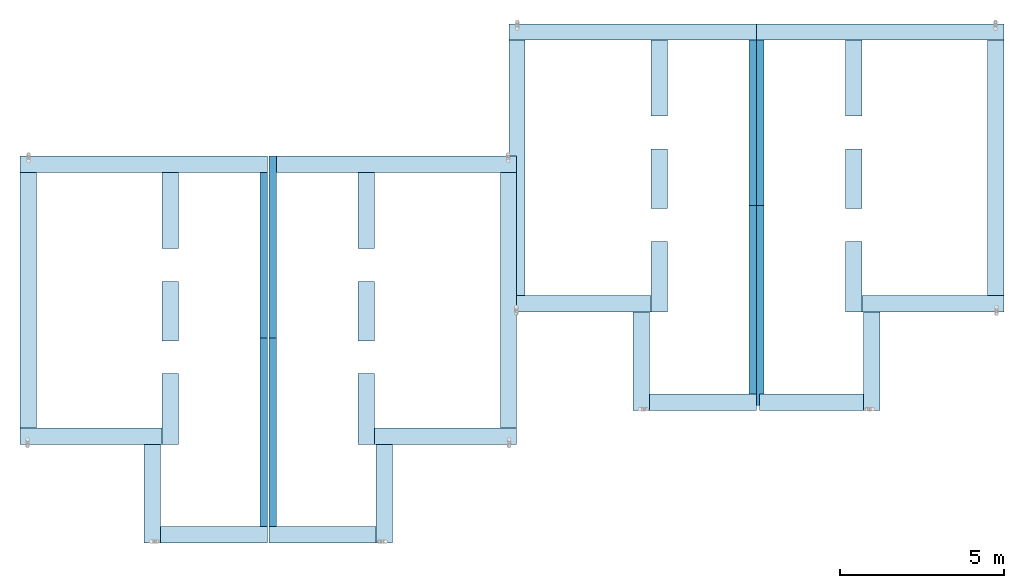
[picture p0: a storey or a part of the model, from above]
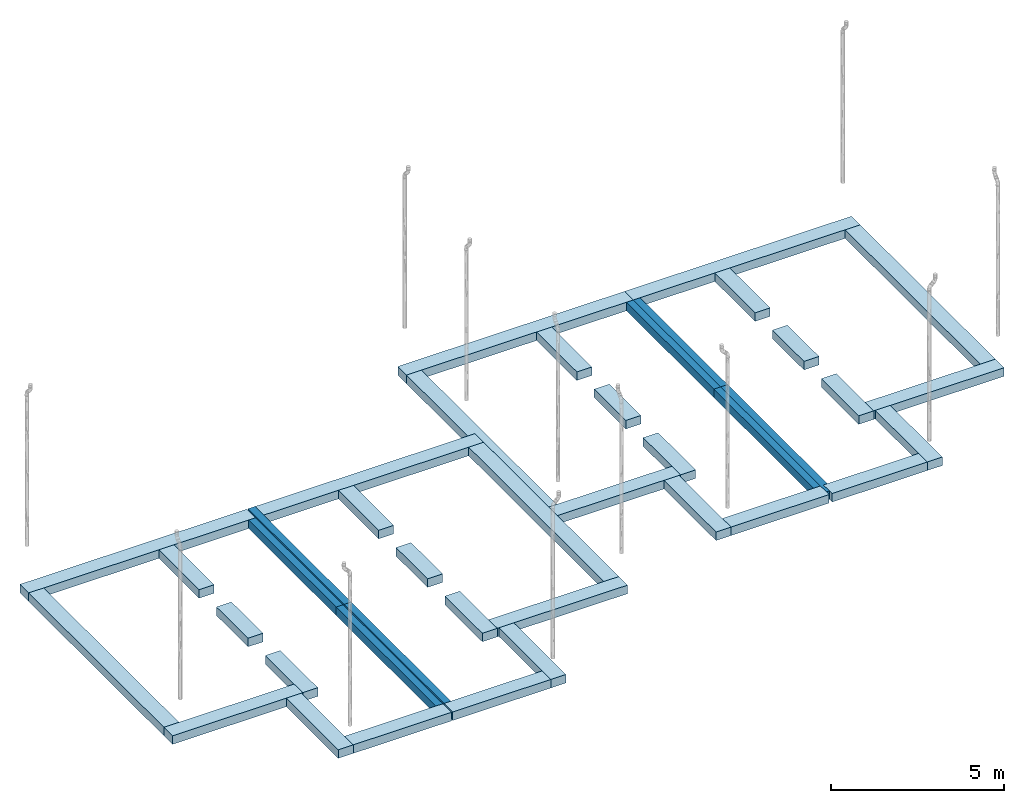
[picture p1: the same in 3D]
Properties of the parts of a building model (IFC2X3), part 1 of 3

# File
Description: ViewDefinition [CoordinationView]
Time: 2020-01-27T23:21:47
Written by: The EXPRESS Data Manager Version 5.02.0100.07 : 28 Aug 2013
Made in: 20150220_1215(x64) - Exporter 16.0.428.0 - Default UI
Comment: STEP Physical File produced by: The EXPRESS Data Manager Version 5.02.0100.07 : 28 Aug 2013 * Module: EDMstepFileFactory/EDMstandAlone * Creation date: Mon Jan 27 23:21:47 2020 * Host: Khodri-Mohamed * Database: C:\Users\KHODRI~1\AppData\Local\Temp\{C74B5687-D98A-45EB-B727-983E96799452}\ifc * Database version: 5507 * Database creation date: Mon Jan 27 23:21:04 2020 * Schema: IFC2X3 * Model: DataRepository.ifc * Model creation date: Mon Jan 27 23:21:07 2020 * Header model: DataRepository.ifc_HeaderModel * Header model creation date: Mon Jan 27 23:21:07 2020 * EDMuser: sdai-user * EDMgroup: sdai-group * License ID and type: 5605 : Permanent license. Expiry date: * EDMstepFileFactory options: 020000

# IfcProject
LongName: F:\sujet 0 CAP PEINTRE 2019\DOSSIER TECHNIQUE LUCE\PROJET DE 4 MAISONS A ROINVILLE DU 26 NOVEMBRE 2019.ifc

# IfcSite, Surface:1258945
RefLatitude: 48, 52, 53, 759999; RefLongitude: 2, 25, 58, 79999; RefElevation: 0 m
Autre - Catégorie: Topographie; Déblais: 0 m3; Déblais/remblais net: 0 m3; Remblais: 0 m3
Cotes - Surface: 126.205 m2; Surface projetée: 126.205 m2
Phase de construction - Phase de création: Nouvelle construction

# IfcBuilding
Pset_BuildingCommon - NumberOfStoreys: 8
Autre - Catégorie: Informations sur le projet

# IfcBuildingStorey (6)
Autre - Catégorie: Niveaux; Famille: Niveau: Ligne du Niveau; Famille et type: Niveau: Ligne du Niveau; ID du type: Niveau: Ligne du Niveau; Type: Niveau: Ligne du Niveau; Nom de la famille: Niveau
Cotes - Hauteur de calcul: 0 m
Données d'identification - Structure: no; Etage de bâtiment: yes; Nom du type: Ligne du Niveau
Contraintes - Base de l'élévation: Point de base du projet
Graphismes - Couleur: 12632256; Epaisseur des lignes: 1; Motif des lignes: Tiret point; Symbole: FR_Marqueur de niveau - Point triangulaire: FR_Marqueur de niveau - Point triangulaire; Valeur par défaut du symbole à l'extrémité 1: no; Valeur par défaut du symbole à l'extrémité 2: yes
Name | LongName = Nom | Elevation (m) = Elévation (m)
Plan de fondation | Plan de fondation | -1
vs | vs | -0.8
TN | TN | -0.05
Plan des fondations Maisons 1 et 2 | Plan des fondations Maisons 1 et 2 | 0
ETAGE | ETAGE | 2.82
Egout | Egout | 5.64

# IfcSpace (12)
InteriorOrExteriorSpace: INTERNAL
Analyse d'énergie - Charge d'éclairage basse sur: <Par défaut>; Charge d'éclairage réelle par surface: 0; Charge d'éclairage spécifiée: 0 W; Charge d'éclairage spécifiée par surface: 10.7639; Charge de puissance basse sur: <Par défaut>; Charge de puissance réelle: 0 W; Charge de puissance réelle par surface: 0; Charge de puissance spécifiée: 0 W; Charge de puissance spécifiée par surface: 13.9931; Charge réelle d'éclairage: 0 W; Contribution à l'éclairage du plénum: 0.2; Gain de chaleur latente par personne: 630.918; Gain de chaleur perceptible par personne: 788.648; Gain de chaleur total par personne: 1419.57; Nombre de personnes: 0; Surface par personne: 28.5714 m2; Unités de charge d'éclairage: Densité de puissance; Unités de charge de puissance: Densité de puissance; Valeurs de charge de chauffage: <Par défaut>
Autre - Catégorie: Pièces; ID de phase: Nouvelle construction
Contraintes - Décalage inférieur: 0 m; Décalage limite: 2.4384 m
Cotes - Hauteur de calcul: 0 m; Hauteur non liée: 2.4384 m
Phase de construction - Phase: Nouvelle construction
Name | In | LongName = Nom | GSA Space Areas (m2) = Surface (m2) | Reference | Limite supérieure | Niveau | Périmètre (m) | Numéro
470 | Plan des fondations Maisons 1 et 2 | SALON - CUISINE | 38.933 | SALON - CUISINE 470 | Niveau: RDC | Niveau: RDC | 31.5901 | 470
471 | Plan des fondations Maisons 1 et 2 | WC | 4.07214 | WC 471 | Niveau: RDC | RDC | 8.47736 | 471
472 | Plan des fondations Maisons 1 et 2 | GARAGE | 15.6284 | GARAGE 472 | Niveau: RDC | RDC | 17.23 | 472
473 | ETAGE | Ch 2 | 12.0823 | Ch 2 473 | Niveau: ETAGE | Niveau: ETAGE | 13.9765 | 473
474 | ETAGE | Ch 1 | 11.1072 | Ch 1 474 | Niveau: ETAGE | ETAGE | 13.3323 | 474
475 | ETAGE | SDB | 9.78736 | SDB 475 | Niveau: ETAGE | Niveau: ETAGE | 14.2316 | 475
476 | ETAGE | WC | 1.59787 | WC 476 | Niveau: ETAGE | Niveau: ETAGE | 5.22997 | 476
477 | ETAGE | Suite parentale | 13.4744 | Suite parentale 477 | Niveau: ETAGE | ETAGE | 18.1208 | 477
478 | ETAGE | Dégt | 3.93396 | Dégt 478 | Niveau: ETAGE | Niveau: ETAGE | 9.4721 | 478
479 | ETAGE | PL | 0.843565 | PL 479 | Niveau: ETAGE | Niveau: ETAGE | 4.24326 | 479
480 | ETAGE | PL | 0.782615 | PL 480 | Niveau: ETAGE | Niveau: ETAGE | 4.01326 | 480
482 | Plan des fondations Maisons 1 et 2 | PL | 0.732961 | PL 482 | Niveau: RDC | Niveau: RDC | 3.45584 | 482

# IfcAnnotation (62)
Name | In
11 x  | Plan des fondations Maisons 1 et 2
8 x  | ETAGE
 | Plan des fondations Maisons 1 et 2 | Group: Groupe de modèles:Pavillon type:1258082
 | Plan des fondations Maisons 1 et 2 | Group: Groupe de modèles:Pavillon type:1258309
39 x  | vs
 | ETAGE | Group: Groupe de modèles:Pavillon type:1258082
 | ETAGE | Group: Groupe de modèles:Pavillon type:1258309

# IfcBeam: Poutre rectangulaire - Béton:20 x 35 ht:892716 (4)
In: Egout
Material: Béton - Béton coulé sur place
Pset_BeamCommon - IsExternal: no; LoadBearing: yes; Slope: 0 deg; Reference: 20 x 35 ht; Span: 3.39 m
Autre - Catégorie: Ossature; Famille: Poutre rectangulaire - Béton: 20 x 35 ht; Famille et type: Poutre rectangulaire - Béton: 20 x 35 ht; ID du type: Poutre rectangulaire - Béton: 20 x 35 ht; Type: Poutre rectangulaire - Béton: 20 x 35 ht; Nom de la famille: Poutre rectangulaire - Béton
Contraintes - Décalage du niveau d'arrivée: 0.07 m; Décalage du niveau de départ: 0.07 m; Elévation du niveau de référence: 5.64 m; Niveau de référence: Niveau: Egout; Rotation de la section: 0 deg
Cotes - Elévation à la base: 5.36 m; Elévation en haut: 5.71 m; Longueur: 3.39 m; Surface: 1.94847 m2; Volume: 0.239078 m3; b: 0.2 m; h: 0.35 m
Matériaux et finitions - Matériau structurel: Béton - Béton coulé sur place
Phase de construction - Phase de création: Nouvelle construction
Position géométrique - Etat de la jonction: Deux jonctions activées; Justification Y: Origine; Justification YZ: Uniforme; Justification Z: Haut; Valeur de décalage Y: 0 m; Valeur de décalage Z: 0 m
Structure - Activer le modèle analytique: yes; Enrobage d'armature - Autres faces: Paramètres de l'enrobage d'armature: Enrobage d'armature 1; Enrobage d'armature - Face inférieure: Paramètres de l'enrobage d'armature: Enrobage d'armature 1; Enrobage d'armature - Face supérieure: Paramètres de l'enrobage d'armature: Enrobage d'armature 1; Longueur de coupe: 3.4154 m; Utilisation structurelle: Autre; Forme de coupe: 0
Données d'identification - Nom du type: 20 x 35 ht
Name (Poutre rectangulaire - Béton:20 x 35 ht:...) | Group
1344637
1344690 | Groupe de modèles:Pavillon type:1258082
1344694 | Groupe de modèles:Pavillon type:1258309
1360945 | Groupe de modèles:Pavillon type:1360776

# IfcBuildingElementProxy: 1372 mm (4)
Type - Material: Métal - Chrome, Métal - Acier, Poli, Métal - Finition peinture - Ivoire, Mat, Peinture - Ivoire, Plastique - Noir, Bois - Mélaminé blanc, Bois - Mélaminé hêtre
Type - Autre - Catégorie: Equipement spécialisé; Nom de la famille: Kitchenette - Moyenne
Type - Cotes - Hauteur: 0.9 m; Hauteur de l'empattement: 0.16 m; Hauteur du lave-vaisselle: 0.9 m; Hauteur du réfrigérateur: 2 m; Largeur: 1.372 m; Largeur de la plaque de cuisson: 0.55 m; Largeur de l'évier: 0.45 m; Largeur du lave-vaisselle: 0.71 m; Largeur du réfrigérateur: 0.66 m; Profondeur: 0.61 m; Profondeur de la plaque de cuisson: 0.45 m; Profondeur de l'empattement: 0.035 m; Profondeur de l'évier: 0.45 m; Profondeur du lave-vaisselle: 0.61 m; Profondeur du réfrigérateur: 0.76 m
Type - Données d'identification - Nom du type: 1372 mm
Type - Matériaux et finitions - Placard: Bois - Mélaminé blanc; Poignée: Plastique - Noir; Porte/tiroir: Bois - Mélaminé blanc
Pset_BuildingElementProxyCommon - Reference: 1372 mm
Autre - Famille: Kitchenette - Moyenne: 1372 mm; Famille et type: Kitchenette - Moyenne: 1372 mm; ID du type: Kitchenette - Moyenne: 1372 mm; Type: Kitchenette - Moyenne: 1372 mm
Contraintes - Niveau: Niveau: Plan des fondations Maisons 1 et 2; Décalage: 0 m; Se déplace avec les éléments voisins: no; Hôte: Niveau : Plan des fondations Maisons 1 et 2
Cotes - Surface: 16.7862 m2; Volume: 1.07185 m3
Phase de construction - Phase de création: Nouvelle construction
Name (Kitchenette - Moyenne:1372 mm:...) | In | Group
1278551 | Plan des fondations Maisons 1 et 2 | Groupe de modèles:Pavillon type:1258082
1278757 | Plan des fondations Maisons 1 et 2 | Groupe de modèles:Pavillon type:1258309
1283199 | 470
1360808 | Plan des fondations Maisons 1 et 2 | Groupe de modèles:Pavillon type:1360776

# IfcBuildingElementProxy: 1455639399409- Car (2)
In: Plan des fondations Maisons 1 et 2
Pset_BuildingElementProxyCommon - Reference: 1455639399409- Car
Autre - Catégorie: Site; Famille: 1455639399409- Car: 1455639399409- Car; Famille et type: 1455639399409- Car: 1455639399409- Car; ID du type: 1455639399409- Car: 1455639399409- Car; Type: 1455639399409- Car: 1455639399409- Car; Nom de la famille: 1455639399409- Car
Contraintes - Niveau: Niveau: Plan des fondations Maisons 1 et 2; Décalage: 0 m; Se déplace avec les éléments voisins: no; Hôte: Niveau : Plan des fondations Maisons 1 et 2
Phase de construction - Phase de création: Nouvelle construction
Données d'identification - Nom du type: 1455639399409- Car
Name (1455639399409- Car:1455639399409- Car:...)
1369798
1369803

# IfcBuildingElementProxy: 3,00 x 1,50 ht portail blanc (4)
In: Plan des fondations Maisons 1 et 2
Material: Peinture - Or, Portail - Chapeaux piliers, PVC - Blanc, Portail - Piliers
Pset_BuildingElementProxyCommon - Reference: 3,00 x 1,50 ht portail blanc
Autre - Catégorie: Site; Famille: Portail métal - Double: 3,00 x 1,50 ht portail blanc; Famille et type: Portail métal - Double: 3,00 x 1,50 ht portail blanc; ID du type: Portail métal - Double: 3,00 x 1,50 ht portail blanc; Type: Portail métal - Double: 3,00 x 1,50 ht portail blanc; Nom de la famille: Portail métal - Double
Contraintes - Décalage: 0 m; Se déplace avec les éléments voisins: no
Cotes - Surface: 5.45238 m2; Volume: 0.174554 m3; Hauteur: 1.5 m; Hauteur de la poignée: 0.9 m; Largeur: 3 m
Phase de construction - Phase de création: Nouvelle construction
Données d'identification - Nom du type: 3,00 x 1,50 ht portail blanc
Graphismes - Cache opaque: yes
Matériaux et finitions - Barrière: PVC - Blanc; Chapeaux: Portail - Chapeaux piliers; Piliers: Portail - Piliers; Poignée: PVC - Blanc; Volutes: Peinture - Or
Name (Portail métal - Double:3,00 x 1,50 ht portail blanc:...) | Hôte | Niveau
1258368 | Niveau : RDC | Niveau: RDC
1258405 | Niveau : RDC | Niveau: RDC
1258469 | Niveau : RDC | Niveau: RDC
1298929 | Niveau : Plan des fondations Maisons 1 et 2 | Niveau: Plan des fondations Maisons 1 et 2

# IfcBuildingElementProxy: 35 x 93 x 19.7 cm (4)
In: Plan des fondations Maisons 1 et 2
Material: Polyester - Beige
Pset_BuildingElementProxyCommon - Reference: 35 x 93 x 19.7 cm
Autre - Catégorie: Site; Famille: Boîtier de raccordement électrique sur base: 35 x 93 x 19.7 cm; Famille et type: Boîtier de raccordement électrique sur base: 35 x 93 x 19.7 cm; ID du type: Boîtier de raccordement électrique sur base: 35 x 93 x 19.7 cm; Type: Boîtier de raccordement électrique sur base: 35 x 93 x 19.7 cm; Nom de la famille: Boîtier de raccordement électrique sur base
Contraintes - Niveau: Niveau: Plan des fondations Maisons 1 et 2; Décalage: 0 m; Se déplace avec les éléments voisins: no; Hôte: Niveau : Plan des fondations Maisons 1 et 2
Cotes - Surface: 0.977252 m2; Volume: 0.0639235 m3
Phase de construction - Phase de création: Nouvelle construction
Données d'identification - Nom du type: 35 x 93 x 19.7 cm
Matériaux et finitions - Caisson: Polyester - Beige
Name (Boîtier de raccordement électrique sur base:35 x 93 x 19.7 cm:...) | Group
1304810 | Groupe de modèles:muret technique:1301639
1304963 | Groupe de modèles:muret technique:1304961
1305110 | Groupe de modèles:muret technique:1305108
1305403 | Groupe de modèles:muret technique:1305401

# IfcBuildingElementProxy: 350mm x 500mm beige (4)
In: Plan des fondations Maisons 1 et 2
Material: Peinture - Noir brillant, Peinture - Gris
Pset_BuildingElementProxyCommon - Reference: 350mm x 500mm beige
Autre - Catégorie: Site; Famille: Boîte aux lettres encastrée: 350mm x 500mm beige; Famille et type: Boîte aux lettres encastrée: 350mm x 500mm beige; ID du type: Boîte aux lettres encastrée: 350mm x 500mm beige; ID hôte: Mur de base: Ext. Parpaing 20 + 2 x 1.5; Type: Boîte aux lettres encastrée: 350mm x 500mm beige; Nom de la famille: Boîte aux lettres encastrée
Contraintes - Niveau: Niveau: Plan des fondations Maisons 1 et 2; Elévation: 0.787402 m
Cotes - Surface: 0.749968 m2; Volume: 0.00726675 m3; Décalage du mur: 0.03 m; Haut de la boîte: 1.1 m; Hauteur de la boîte aux lettres: 0.5 m; Hauteur de la fente: 0.05 m; Largeur de la boîte aux lettres: 0.35 m; Largeur de la fente: 0.25 m; Profondeur de la boîte aux lettres: 0.25 m
Phase de construction - Phase de création: Nouvelle construction
Données d'identification - Nom du type: 350mm x 500mm beige
Matériaux et finitions - Matériau - Boîte aux lettres: Peinture - Gris
Name (Boîte aux lettres encastrée:350mm x 500mm beige:...) | Group
1302522 | Groupe de modèles:muret technique:1301639
1304962 | Groupe de modèles:muret technique:1304961
1305109 | Groupe de modèles:muret technique:1305108
1305402 | Groupe de modèles:muret technique:1305401

# IfcBuildingElementProxy: 600mm x 590mm x 820mm (8)
Type - Material: Peinture - Ivoire, Verre
Type - Autre - Catégorie: Equipement spécialisé; Nom de la famille: Lave linge - Chargement frontal
Type - Cotes - Hauteur: 0.82 m; Largeur: 0.6 m; Profondeur: 0.59 m
Type - Données d'identification - Nom du type: 600mm x 590mm x 820mm
Type - Matériaux et finitions - Finition: Peinture - Ivoire
Pset_BuildingElementProxyCommon - Reference: 600mm x 590mm x 820mm
Autre - Famille: Lave linge - Chargement frontal: 600mm x 590mm x 820mm; Famille et type: Lave linge - Chargement frontal: 600mm x 590mm x 820mm; ID du type: Lave linge - Chargement frontal: 600mm x 590mm x 820mm; Type: Lave linge - Chargement frontal: 600mm x 590mm x 820mm
Contraintes - Décalage: 0 m; Se déplace avec les éléments voisins: no; Niveau: Niveau: ETAGE; Hôte: Niveau : ETAGE
Cotes - Surface: 2.15169 m2; Volume: 0.247328 m3
Phase de construction - Phase de création: Nouvelle construction
Name (Lave linge - Chargement frontal:600mm x 590mm x 820mm:...) | In | Group
1273171 | ETAGE | Groupe de modèles:Pavillon type:1258082
1273182 | ETAGE | Groupe de modèles:Pavillon type:1258309
1281591 | ETAGE | Groupe de modèles:Pavillon type:1258082
1281603 | ETAGE | Groupe de modèles:Pavillon type:1258309
1283187 | 475
1283206 | 475
1360799 | ETAGE | Groupe de modèles:Pavillon type:1360776
1360811 | ETAGE | Groupe de modèles:Pavillon type:1360776

# IfcBuildingElementProxy: Epicéa - 4 m (8)
In: Plan des fondations Maisons 1 et 2
Type - Autre - Catégorie: Plantes; Nom de la famille: Arbre 3D - Epicéa
Type - Cotes - Hauteur: 4 m
Type - Données d'identification - Apparence de rendu: RPC-16-FXGW-0XFX-PJ97-W000-ST1L-LVER-AU; Nom du type: Epicéa - 4 m; Numéro OmniClass: 23.40.05.00; Titre OmniClass: Plants and Planting Products
Pset_BuildingElementProxyCommon - Reference: Epicéa - 4 m
Autre - Famille: Arbre 3D - Epicéa: Epicéa - 4 m; Famille et type: Arbre 3D - Epicéa: Epicéa - 4 m; ID du type: Arbre 3D - Epicéa: Epicéa - 4 m; Type: Arbre 3D - Epicéa: Epicéa - 4 m
Contraintes - Décalage: 0 m; Se déplace avec les éléments voisins: no; Hôte: Surface
Phase de construction - Phase de création: Nouvelle construction
Name (Arbre 3D - Epicéa:Epicéa - 4 m:...) | Niveau
1260726 | Niveau: RDC
1260787 | Niveau: RDC
1260814 | Niveau: RDC
1260837 | Niveau: RDC
1328711 | Niveau: Plan des fondations Maisons 1 et 2
1328720 | Niveau: Plan des fondations Maisons 1 et 2
1328731 | Niveau: Plan des fondations Maisons 1 et 2
1328740 | Niveau: Plan des fondations Maisons 1 et 2

# IfcBuildingElementProxy: seat-ibiza(6j-cupra) (2)
In: Plan des fondations Maisons 1 et 2
Pset_BuildingElementProxyCommon - Reference: seat-ibiza(6j-cupra)
Autre - Catégorie: Site; Famille: seat-ibiza(6j-cupra): seat-ibiza(6j-cupra); Famille et type: seat-ibiza(6j-cupra): seat-ibiza(6j-cupra); ID du type: seat-ibiza(6j-cupra): seat-ibiza(6j-cupra); Type: seat-ibiza(6j-cupra): seat-ibiza(6j-cupra); Nom de la famille: seat-ibiza(6j-cupra)
Contraintes - Niveau: Niveau: Plan des fondations Maisons 1 et 2; Décalage: 0 m; Se déplace avec les éléments voisins: no; Hôte: Niveau : Plan des fondations Maisons 1 et 2
Phase de construction - Phase de création: Nouvelle construction
Données d'identification - Nom du type: seat-ibiza(6j-cupra)
Name (seat-ibiza(6j-cupra):seat-ibiza(6j-cupra):...)
1369801
1369804

# IfcColumn: 20 X 20 (12)
In: TN
Type - ElementType: 20 X 20; PredefinedType: COLUMN; Material: Béton - Béton coulé sur place
Type - Autre - Catégorie: Poteaux porteurs; Nom de la famille: M_Béton-Carré-Poteau
Type - Cotes - b: 0.2 m
Type - Données d'identification - Nom du type: 20 X 20
Type - Structure - Forme de coupe: 0
Pset_ColumnCommon - IsExternal: no; LoadBearing: yes; Reference: 20 X 20
Autre - Famille: M_Béton-Carré-Poteau: 20 X 20; Famille et type: M_Béton-Carré-Poteau: 20 X 20; ID du type: M_Béton-Carré-Poteau: 20 X 20; Type: M_Béton-Carré-Poteau: 20 X 20
Contraintes - Limite de pièce: yes; Niveau: Niveau: TN; Niveau de base: Niveau: TN; Se déplace avec les quadrillages: yes; Style de poteau: Vertical
Matériaux et finitions - Matériau structurel: Béton - Béton coulé sur place
Phase de construction - Phase de création: Nouvelle construction
Structure - Activer le modèle analytique: yes; Enrobage d'armature - Autres faces: Paramètres de l'enrobage d'armature: Enrobage d'armature 1; Enrobage d'armature - Face inférieure: Paramètres de l'enrobage d'armature: Enrobage d'armature 1; Enrobage d'armature - Face supérieure: Paramètres de l'enrobage d'armature: Enrobage d'armature 1
Name (M_Béton-Carré-Poteau:20 X 20:...) | Décalage inférieur (m) | Décalage supérieur (m) | Niveau supérieur | Longueur (m) | Surface (m2) | Volume (m3) | Group
1285215 | 0 | 0 | Niveau: RDC | 0.05 | 0.06 | 0.002 | Pset_ColumnCommon - Slope: 0 deg
1285443 | 0 | 0 | Niveau: Plan des fondations Maisons 1 et 2 | 0.05 | 0.06 | 0.002 | Groupe de modèles:Pavillon type:1258082 | Pset_ColumnCommon - Slope: 0 deg
1285460 | 0 | 0 | Niveau: Plan des fondations Maisons 1 et 2 | 0.05 | 0.06 | 0.002 | Groupe de modèles:Pavillon type:1258309 | Pset_ColumnCommon - Slope: 0 deg
1333031 | -0.95 | 2.8 | Niveau: RDC | 3.8 | 1.56 | 0.152 | Pset_ColumnCommon - Slope: 0 deg
1333209 | -0.95 | 2.8 | Niveau: Plan des fondations Maisons 1 et 2 | 3.8 | 1.56 | 0.152 | Groupe de modèles:Pavillon type:1258082 | Pset_ColumnCommon - Slope: 0 deg
1333213 | -0.95 | 2.8 | Niveau: Plan des fondations Maisons 1 et 2 | 3.8 | 1.56 | 0.152 | Groupe de modèles:Pavillon type:1258309 | Pset_ColumnCommon - Slope: 0 deg
1342184 | -0.95 | 2.8 | Niveau: Plan des fondations Maisons 1 et 2 | 3.8 | 1.56 | 0.152
1343042 | -0.95 | 2.8 | Niveau: Plan des fondations Maisons 1 et 2 | 3.8 | 1.56 | 0.152 | Groupe de modèles:Pavillon type:1258082
1343055 | -0.95 | 2.8 | Niveau: Plan des fondations Maisons 1 et 2 | 3.8 | 1.56 | 0.152 | Groupe de modèles:Pavillon type:1258309
1360830 | 0 | 0 | Niveau: Plan des fondations Maisons 1 et 2 | 0.05 | 0.06 | 0.002 | Groupe de modèles:Pavillon type:1360776
1360924 | -0.95 | 2.8 | Niveau: Plan des fondations Maisons 1 et 2 | 3.8 | 1.56 | 0.152 | Groupe de modèles:Pavillon type:1360776
1360941 | -0.95 | 2.8 | Niveau: Plan des fondations Maisons 1 et 2 | 3.8 | 1.56 | 0.152 | Groupe de modèles:Pavillon type:1360776

# IfcCovering: Plafond composé:Plafond avec isolation (10)
In: ETAGE
PredefinedType: CEILING; Material: Isolant 0.3 m, Faux-Plafond par Défaut 0.02 m
Pset_CoveringCommon - Reference: Plafond avec isolation; TotalThickness: 0.32 m
Autre - Catégorie: Plafonds; Famille: Plafond composé: Plafond avec isolation; Famille et type: Plafond composé: Plafond avec isolation; ID du type: Plafond composé: Plafond avec isolation; Type: Plafond composé: Plafond avec isolation; Nom de la famille: Plafond composé
Contraintes - Limite de pièce: yes; Niveau: Niveau: ETAGE
Phase de construction - Phase de création: Nouvelle construction
Construction - Epaisseur: 0.32 m
Données d'identification - Nom du type: Plafond avec isolation
Graphismes - Couleur vue détail faible: 0
Propriétés analytiques - Rugosité: 1; Coefficient d'absorbance: 0.1
Name (Plafond composé:Plafond avec isolation:...) | Décalage par rapport au niveau (m) | Périmètre (m) | Surface (m2) | Volume (m3)
1265254 | 2.5 | 29.6165 | 45.4142 | 14.5325
1287873 | 2.5 | 18.2558 | 18.3395 | 5.86864
1353384 | 2.52 | 14.2316 | 9.78736 | 3.13195
1353394 | 2.4 | 13.3323 | 11.1072 | 3.5543
1353450 | 2.5 | 13.9765 | 12.0823 | 3.86634
1353458 | 2.5 | 4.01326 | 0.782615 | 0.250437
1353466 | 2.5 | 4.24326 | 0.843565 | 0.269941
1353513 | 2.52 | 5.22997 | 1.59787 | 0.511317
1356266 | 2.52 | 18.11 | 18.0802 | 5.78566
1356773 | 2.52 | 13.255 | 8.2521 | 2.64067

# IfcDoor: 0.70m x 2.04m 2 (2)
In: ETAGE
Type - OperationType: SLIDING_TO_LEFT; ParameterTakesPrecedence: no; Sizeable: no; Material: Porte - Poignée, Porte - Panneau, Porte - Cadre
Type - Autre - Catégorie: Portes; Nom de la famille: Coulissante - Encastrée
Type - Construction - Fonction: Intérieur; Fermeture du mur: Aucun
Type - Cotes - Elév. Poignée: 0.9 m; Epaisseur: 0.04 m; Hauteur: 2.04 m; Largeur: 0.7 m; Largeur du cadre: 0.015 m; Retour: 0.01 m
Type - Données d'identification - Marque de type: 97; Nom du type: 0.70m x 2.04m 2
Type - Matériaux et finitions - Dormants: Porte - Cadre; Panneau: Porte - Panneau; Poignée: Porte - Poignée
Type - Propriétés analytiques - Construction analytique: <Aucun>
Type - Coulissante - Encastrée:0.70m x 2.04m 2:1277804 - PanelOperation: SLIDING
OverallHeight: 2.065 m; OverallWidth: 1.44 m
Pset_DoorCommon - IsExternal: no; Reference: 0.70m x 2.04m 2
Autre - ID hôte: Mur de base: Int. Platre 70 mm en blanc; Famille: Coulissante - Encastrée: 0.70m x 2.04m 2; Famille et type: Coulissante - Encastrée: 0.70m x 2.04m 2; ID du type: Coulissante - Encastrée: 0.70m x 2.04m 2; Type: Coulissante - Encastrée: 0.70m x 2.04m 2; Hauteur sous linteau: 2.04 m
Contraintes - Hauteur de l'appui: 0 m; Niveau: Niveau: ETAGE
Cotes - Surface: 1.9845 m2; Volume: 0.0630189 m3
Phase de construction - Phase de création: Nouvelle construction
Name (Coulissante - Encastrée:0.70m x 2.04m 2:...) | Identifiant | Group
1277804 | 618 | Groupe de modèles:Pavillon type:1258309
1360802 | 641 | Groupe de modèles:Pavillon type:1360776

# IfcDoor: 0.70m x 2.04m 2 (2)
In: ETAGE
Type - OperationType: SLIDING_TO_LEFT; ParameterTakesPrecedence: no; Sizeable: no; Material: Porte - Poignée, Porte - Panneau, Porte - Cadre
Type - Coulissante - Encastrée:0.70m x 2.04m 2:1277792 - PanelOperation: SLIDING
Type - Autre - Catégorie: Portes; Nom de la famille: Coulissante - Encastrée
Type - Construction - Fonction: Intérieur; Fermeture du mur: Aucun
Type - Cotes - Elév. Poignée: 0.9 m; Epaisseur: 0.04 m; Hauteur: 2.04 m; Largeur: 0.7 m; Largeur du cadre: 0.015 m; Retour: 0.01 m
Type - Données d'identification - Marque de type: 97; Nom du type: 0.70m x 2.04m 2
Type - Matériaux et finitions - Dormants: Porte - Cadre; Panneau: Porte - Panneau; Poignée: Porte - Poignée
Type - Propriétés analytiques - Construction analytique: <Aucun>
OverallHeight: 2.065 m; OverallWidth: 1.44 m
Pset_DoorCommon - IsExternal: no; Reference: 0.70m x 2.04m 2
Autre - ID hôte: Mur de base: Int. Platre 70 mm en blanc; Famille: Coulissante - Encastrée: 0.70m x 2.04m 2; Famille et type: Coulissante - Encastrée: 0.70m x 2.04m 2; Hauteur sous linteau: 2.04 m; ID du type: Coulissante - Encastrée: 0.70m x 2.04m 2; Type: Coulissante - Encastrée: 0.70m x 2.04m 2
Contraintes - Hauteur de l'appui: 0 m; Niveau: Niveau: ETAGE
Cotes - Surface: 1.9845 m2; Volume: 0.0630189 m3
Phase de construction - Phase de création: Nouvelle construction
Name (Coulissante - Encastrée:0.70m x 2.04m 2:...) | Identifiant
1277792 | 605 | Group: Groupe de modèles:Pavillon type:1258082
1283190 | 629

# IfcDoor: 100 - 215 - Blanc (4)
In: Plan des fondations Maisons 1 et 2
Type - ParameterTakesPrecedence: no; Sizeable: no; Material: Peinture époxy - Blanc, Verre - Opaque Blanc
Type - Autre - Catégorie: Portes; Nom de la famille: Avec panneau latéral
Type - Construction - Fonction: Extérieur; Fermeture du mur: Extérieur
Type - Cotes - Epaisseur: 0.05 m; Epaisseur d'isolation: 0.1 m; Hauteur: 2.15 m; Hauteur de la poignée: 1 m; Largeur: 1.4 m; Largeur de l'ouverture: 1 m; Largeur du cadre: 0.06 m
Type - Données d'identification - Marque de type: 92; Nom du type: 100 - 215 - Blanc; Numéro OmniClass: 23.30.10.00; Titre OmniClass: Doors
Type - Matériaux et finitions - Cadre: Peinture époxy - Blanc; Panneau: Peinture époxy - Blanc; Poignée: Peinture époxy - Blanc; Vitrage: Verre - Opaque Blanc
Type - Propriétés analytiques - Construction analytique: <Aucun>
OverallHeight: 2.225 m; OverallWidth: 1.52 m
Pset_DoorCommon - IsExternal: yes; Reference: 100 - 215 - Blanc
Autre - Famille: Avec panneau latéral: 100 - 215 - Blanc; Famille et type: Avec panneau latéral: 100 - 215 - Blanc; Hauteur sous linteau: 2.15 m; ID du type: Avec panneau latéral: 100 - 215 - Blanc; ID hôte: Mur de base: Ext. Parpaing 20 + Isolant 10 enduit blanc cassé; Type: Avec panneau latéral: 100 - 215 - Blanc
Contraintes - Hauteur de l'appui: 0 m; Niveau: Niveau: Plan des fondations Maisons 1 et 2
Cotes - Surface: 3.59301 m2; Volume: 0.118016 m3
Graphismes - Angle d'ouverture 2D fixé: yes; Angle d'ouverture 3D: 0 deg
Phase de construction - Phase de création: Nouvelle construction
Name (Avec panneau latéral:100 - 215 - Blanc:...) | Identifiant | Group
1257907 | 595 | Groupe de modèles:Pavillon type:1258082
1258141 | 608 | Groupe de modèles:Pavillon type:1258309
1283007 | 620
1360638 | 632 | Groupe de modèles:Pavillon type:1360776

# IfcDoor: 2.4m x 2m (2)
In: Plan des fondations Maisons 1 et 2
Type - OperationType: ROLLINGUP; ParameterTakesPrecedence: no; Sizeable: no; Material: Plastique - Noir, Peinture - Grise
Type - Autre - Catégorie: Portes; Nom de la famille: Garage basculante
Type - Construction - Fonction: Extérieur; Fermeture du mur: Par hôte
Type - Cotes - Hauteur: 2 m; Hauteur de la poignée: 0.5 m; Largeur: 2.37 m; Largeur du cadre: 0.06 m
Type - Données d'identification - Marque de type: 96; Nom du type: 2.4m x 2m
Type - Matériaux et finitions - Cadre: Peinture - Grise; Panneau: Peinture - Grise; Poignée: Plastique - Noir
Type - Propriétés analytiques - Coefficient d'apport thermique solaire: 0; Coefficient de transfert de chaleur (U): 3.7021; Construction analytique: Métal; Résistance thermique (R): 0.270117; Transmission de la lumière visible: 0
Type - Garage basculante:2.4m x 2m:1258139 - PanelOperation: ROLLINGUP
OverallHeight: 2.015 m; OverallWidth: 2.4 m
Pset_DoorCommon - IsExternal: yes; Reference: 2.4m x 2m; ThermalTransmittance: 3.7021 kg/K/s3
Autre - Famille: Garage basculante: 2.4m x 2m; Famille et type: Garage basculante: 2.4m x 2m; ID du type: Garage basculante: 2.4m x 2m; ID hôte: Mur de base: Ext. Parpaing 2 + 20 + 2 gris; Type: Garage basculante: 2.4m x 2m; Hauteur sous linteau: 2 m
Contraintes - Hauteur de l'appui: 0 m; Niveau: Niveau: Plan des fondations Maisons 1 et 2
Cotes - Surface: 5.6317 m2; Volume: 0.20907 m3
Phase de construction - Phase de création: Nouvelle construction
Name (Garage basculante:2.4m x 2m:...) | Identifiant | Group
1258139 | 606 | Groupe de modèles:Pavillon type:1258309
1360636 | 630 | Groupe de modèles:Pavillon type:1360776

# IfcDoor: 2.4m x 2m (2)
In: Plan des fondations Maisons 1 et 2
Type - OperationType: ROLLINGUP; ParameterTakesPrecedence: no; Sizeable: no; Material: Plastique - Noir, Peinture - Grise
Type - Garage basculante:2.4m x 2m:1257905 - PanelOperation: ROLLINGUP
Type - Autre - Catégorie: Portes; Nom de la famille: Garage basculante
Type - Construction - Fonction: Extérieur; Fermeture du mur: Par hôte
Type - Cotes - Hauteur: 2 m; Hauteur de la poignée: 0.5 m; Largeur: 2.37 m; Largeur du cadre: 0.06 m
Type - Données d'identification - Marque de type: 96; Nom du type: 2.4m x 2m
Type - Matériaux et finitions - Cadre: Peinture - Grise; Panneau: Peinture - Grise; Poignée: Plastique - Noir
Type - Propriétés analytiques - Coefficient d'apport thermique solaire: 0; Coefficient de transfert de chaleur (U): 3.7021; Construction analytique: Métal; Résistance thermique (R): 0.270117; Transmission de la lumière visible: 0
OverallHeight: 2.4 m; OverallWidth: 2.015 m
Pset_DoorCommon - IsExternal: yes; Reference: 2.4m x 2m; ThermalTransmittance: 3.7021 kg/K/s3
Autre - Famille: Garage basculante: 2.4m x 2m; Famille et type: Garage basculante: 2.4m x 2m; Hauteur sous linteau: 2 m; ID du type: Garage basculante: 2.4m x 2m; ID hôte: Mur de base: Ext. Parpaing 2 + 20 + 2 gris; Type: Garage basculante: 2.4m x 2m
Contraintes - Hauteur de l'appui: 0 m; Niveau: Niveau: Plan des fondations Maisons 1 et 2
Cotes - Surface: 5.6317 m2; Volume: 0.20907 m3
Phase de construction - Phase de création: Nouvelle construction
Name (Garage basculante:2.4m x 2m:...) | Identifiant
1257905 | 593 | Group: Groupe de modèles:Pavillon type:1258082
1283005 | 610

# IfcDoor: 73 x 204 - (70) (12)
Type - OperationType: SINGLE_SWING_LEFT; ParameterTakesPrecedence: no; Sizeable: no; Material: Poignée Porte, Dormants Portes, Panneaux Portes
Type - FR_Simple (R):73 x 204 - (70):1257987 - PanelOperation: SWINGING
Type - Autre - Catégorie: Portes; Nom de la famille: FR_Simple (R)
Type - Construction - Fonction: Intérieur; Fermeture du mur: Aucun
Type - Cotes - Elev. Poignée: 0.9 m; Epaisseur: 0.04 m; Hauteur: 2.04 m; Larg. Dormants: 0.035 m; Largeur: 0.73 m; Retour: 0.01 m
Type - Données d'identification - Marque de type: 8; Nom du type: 73 x 204 - (70)
Type - Matériaux et finitions - Dormants: Dormants Portes; Panneau: Panneaux Portes; Poignée: Poignée Porte
Type - Propriétés analytiques - Construction analytique: <Aucun>
OverallHeight: 2.075 m; OverallWidth: 0.8 m
Pset_DoorCommon - IsExternal: no; Reference: 73 x 204 - (70)
Autre - Famille: FR_Simple (R): 73 x 204 - (70); Famille et type: FR_Simple (R): 73 x 204 - (70); Hauteur sous linteau: 2.04 m; ID du type: FR_Simple (R): 73 x 204 - (70); ID hôte: Mur de base: Int. Platre 70 mm en blanc; Type: FR_Simple (R): 73 x 204 - (70)
Contraintes - Hauteur de l'appui: 0 m
Cotes - Surface: 2.19349 m2; Volume: 0.0742568 m3
Phase de construction - Phase de création: Nouvelle construction
Name (FR_Simple (R):73 x 204 - (70):...) | In | Niveau | Identifiant | Group
1257987 | Plan des fondations Maisons 1 et 2 | Niveau: Plan des fondations Maisons 1 et 2 | 596 | Groupe de modèles:Pavillon type:1258082
1258042 | ETAGE | Niveau: ETAGE | 598 | Groupe de modèles:Pavillon type:1258082
1258044 | ETAGE | Niveau: ETAGE | 600 | Groupe de modèles:Pavillon type:1258082
1258045 | ETAGE | Niveau: ETAGE | 601 | Groupe de modèles:Pavillon type:1258082
1258270 | ETAGE | Niveau: ETAGE | 612 | Groupe de modèles:Pavillon type:1258309
1258273 | ETAGE | Niveau: ETAGE | 615 | Groupe de modèles:Pavillon type:1258309
1283086 | Plan des fondations Maisons 1 et 2 | Niveau: Plan des fondations Maisons 1 et 2 | 621
1283125 | ETAGE | Niveau: ETAGE | 622
1283127 | ETAGE | Niveau: ETAGE | 624
1283128 | ETAGE | Niveau: ETAGE | 625
1360746 | ETAGE | Niveau: ETAGE | 635 | Groupe de modèles:Pavillon type:1360776
1360749 | ETAGE | Niveau: ETAGE | 638 | Groupe de modèles:Pavillon type:1360776

# IfcDoor: 73 x 204 - (70) (12)
Type - OperationType: SINGLE_SWING_RIGHT; ParameterTakesPrecedence: no; Sizeable: no; Material: Poignée Porte, Dormants Portes, Panneaux Portes
Type - Autre - Catégorie: Portes; Nom de la famille: FR_Simple (R)
Type - Construction - Fonction: Intérieur; Fermeture du mur: Aucun
Type - Cotes - Elev. Poignée: 0.9 m; Epaisseur: 0.04 m; Hauteur: 2.04 m; Larg. Dormants: 0.035 m; Largeur: 0.73 m; Retour: 0.01 m
Type - Données d'identification - Marque de type: 8; Nom du type: 73 x 204 - (70)
Type - Matériaux et finitions - Dormants: Dormants Portes; Panneau: Panneaux Portes; Poignée: Poignée Porte
Type - Propriétés analytiques - Construction analytique: <Aucun>
Type - FR_Simple (R):73 x 204 - (70):1258043 - PanelOperation: SWINGING
OverallHeight: 2.075 m; OverallWidth: 0.8 m
Pset_DoorCommon - IsExternal: no; Reference: 73 x 204 - (70)
Autre - Famille: FR_Simple (R): 73 x 204 - (70); Famille et type: FR_Simple (R): 73 x 204 - (70); ID du type: FR_Simple (R): 73 x 204 - (70); ID hôte: Mur de base: Int. Platre 70 mm en blanc; Type: FR_Simple (R): 73 x 204 - (70); Hauteur sous linteau: 2.04 m
Contraintes - Hauteur de l'appui: 0 m
Cotes - Surface: 2.19349 m2; Volume: 0.0742568 m3
Phase de construction - Phase de création: Nouvelle construction
Name (FR_Simple (R):73 x 204 - (70):...) | In | Niveau | Identifiant | Group
1258043 | ETAGE | Niveau: ETAGE | 599 | Groupe de modèles:Pavillon type:1258082
1258046 | ETAGE | Niveau: ETAGE | 602 | Groupe de modèles:Pavillon type:1258082
1258220 | Plan des fondations Maisons 1 et 2 | Niveau: Plan des fondations Maisons 1 et 2 | 609 | Groupe de modèles:Pavillon type:1258309
1258269 | ETAGE | Niveau: ETAGE | 611 | Groupe de modèles:Pavillon type:1258309
1258271 | ETAGE | Niveau: ETAGE | 613 | Groupe de modèles:Pavillon type:1258309
1258272 | ETAGE | Niveau: ETAGE | 614 | Groupe de modèles:Pavillon type:1258309
1283126 | ETAGE | Niveau: ETAGE | 623
1283129 | ETAGE | Niveau: ETAGE | 626
1360710 | Plan des fondations Maisons 1 et 2 | Niveau: Plan des fondations Maisons 1 et 2 | 633 | Groupe de modèles:Pavillon type:1360776
1360745 | ETAGE | Niveau: ETAGE | 634 | Groupe de modèles:Pavillon type:1360776
1360747 | ETAGE | Niveau: ETAGE | 636 | Groupe de modèles:Pavillon type:1360776
1360748 | ETAGE | Niveau: ETAGE | 637 | Groupe de modèles:Pavillon type:1360776

# IfcDoor: 83 x 204 - (80) (2)
In: Plan des fondations Maisons 1 et 2
Type - OperationType: SINGLE_SWING_LEFT; ParameterTakesPrecedence: no; Sizeable: no; Material: Poignée Porte, Dormants Portes, Panneaux Portes
Type - Autre - Catégorie: Portes; Nom de la famille: FR_Simple (R)
Type - Construction - Fonction: Intérieur; Fermeture du mur: Par hôte
Type - Cotes - Elev. Poignée: 0.9 m; Epaisseur: 0.04 m; Hauteur: 2.04 m; Larg. Dormants: 0.035 m; Largeur: 0.83 m; Retour: 0.01 m
Type - Données d'identification - Marque de type: 9; Nom du type: 83 x 204 - (80)
Type - Matériaux et finitions - Dormants: Dormants Portes; Panneau: Panneaux Portes; Poignée: Poignée Porte
Type - Propriétés analytiques - Construction analytique: <Aucun>
Type - FR_Simple (R):83 x 204 - (80):1258140 - PanelOperation: SWINGING
OverallHeight: 2.075 m; OverallWidth: 0.9 m
Pset_DoorCommon - IsExternal: no; Reference: 83 x 204 - (80)
Autre - Famille: FR_Simple (R): 83 x 204 - (80); Famille et type: FR_Simple (R): 83 x 204 - (80); ID du type: FR_Simple (R): 83 x 204 - (80); ID hôte: Mur de base: Int. Platre 100 mm en blanc 2; Type: FR_Simple (R): 83 x 204 - (80); Hauteur sous linteau: 2.04 m
Contraintes - Hauteur de l'appui: 0 m; Niveau: Niveau: Plan des fondations Maisons 1 et 2
Cotes - Surface: 2.56404 m2; Volume: 0.0879468 m3
Phase de construction - Phase de création: Nouvelle construction
Name (FR_Simple (R):83 x 204 - (80):...) | Identifiant | Group
1258140 | 607 | Groupe de modèles:Pavillon type:1258309
1360637 | 631 | Groupe de modèles:Pavillon type:1360776

# IfcDoor: 83 x 204 - (80) (2)
In: Plan des fondations Maisons 1 et 2
Type - OperationType: SINGLE_SWING_RIGHT; ParameterTakesPrecedence: no; Sizeable: no; Material: Poignée Porte, Dormants Portes, Panneaux Portes
Type - FR_Simple (R):83 x 204 - (80):1257906 - PanelOperation: SWINGING
Type - Autre - Catégorie: Portes; Nom de la famille: FR_Simple (R)
Type - Construction - Fonction: Intérieur; Fermeture du mur: Par hôte
Type - Cotes - Elev. Poignée: 0.9 m; Epaisseur: 0.04 m; Hauteur: 2.04 m; Larg. Dormants: 0.035 m; Largeur: 0.83 m; Retour: 0.01 m
Type - Données d'identification - Marque de type: 9; Nom du type: 83 x 204 - (80)
Type - Matériaux et finitions - Dormants: Dormants Portes; Panneau: Panneaux Portes; Poignée: Poignée Porte
Type - Propriétés analytiques - Construction analytique: <Aucun>
OverallHeight: 2.075 m; OverallWidth: 0.9 m
Pset_DoorCommon - IsExternal: no; Reference: 83 x 204 - (80)
Autre - Famille: FR_Simple (R): 83 x 204 - (80); Famille et type: FR_Simple (R): 83 x 204 - (80); Hauteur sous linteau: 2.04 m; ID du type: FR_Simple (R): 83 x 204 - (80); ID hôte: Mur de base: Int. Platre 100 mm en blanc 2; Type: FR_Simple (R): 83 x 204 - (80)
Contraintes - Hauteur de l'appui: 0 m; Niveau: Niveau: Plan des fondations Maisons 1 et 2
Cotes - Surface: 2.56404 m2; Volume: 0.0879468 m3
Phase de construction - Phase de création: Nouvelle construction
Name (FR_Simple (R):83 x 204 - (80):...) | Identifiant
1257906 | 594 | Group: Groupe de modèles:Pavillon type:1258082
1283006 | 619

# IfcDoor: Placard coulissante - 2 panneaux (4)
In: ETAGE
Type - OperationType: SLIDING_TO_RIGHT; ParameterTakesPrecedence: no; Sizeable: no; Material: Placard - Profil, Placard - Encadrement, Placard - Porte
Type - Autre - Catégorie: Portes; Nom de la famille: Placard coulissante - 2 panneaux
Type - Construction - Fonction: Intérieur; Fermeture du mur: Aucun
Type - Cotes - Epaisseur: 0.02 m; Hauteur: 2.1 m; Largeur: 1.2 m; Largeur de l'encadrement: 0.05 m
Type - Données d'identification - Marque de type: 62; Nom du type: Placard coulissante - 2 panneaux
Type - Graphismes - Profils: yes
Type - Matériaux et finitions - Encadrement: Placard - Encadrement; Panneau: Placard - Porte; Profil: Placard - Profil
Type - Propriétés analytiques - Construction analytique: <Aucun>
Type - Placard coulissante - 2 panneaux:Placard coulissante - 2 panneaux:1258284 - PanelOperation: SLIDING
OverallHeight: 2.1 m; OverallWidth: 1.2 m
Pset_DoorCommon - IsExternal: no; Reference: Placard coulissante - 2 panneaux
Autre - ID hôte: Mur de base: Int. Platre 70 mm en blanc; Famille: Placard coulissante - 2 panneaux: Placard coulissante - 2 panneaux; Famille et type: Placard coulissante - 2 panneaux: Placard coulissante - 2 panneaux; ID du type: Placard coulissante - 2 panneaux: Placard coulissante - 2 panneaux; Type: Placard coulissante - 2 panneaux: Placard coulissante - 2 panneaux; Hauteur sous linteau: 2.1 m
Contraintes - Hauteur de l'appui: 0 m; Niveau: Niveau: ETAGE
Cotes - Surface: 2.734 m2; Volume: 0.0525 m3
Phase de construction - Phase de création: Nouvelle construction
Name (Placard coulissante - 2 panneaux:Placard coulissante - 2 panneaux:...) | Identifiant | Group
1258284 | 616 | Groupe de modèles:Pavillon type:1258309
1258285 | 617 | Groupe de modèles:Pavillon type:1258309
1360757 | 639 | Groupe de modèles:Pavillon type:1360776
1360758 | 640 | Groupe de modèles:Pavillon type:1360776

# IfcDoor: Placard coulissante - 2 panneaux (4)
In: ETAGE
Type - OperationType: SLIDING_TO_RIGHT; ParameterTakesPrecedence: no; Sizeable: no; Material: Placard - Profil, Placard - Encadrement, Placard - Porte
Type - Placard coulissante - 2 panneaux:Placard coulissante - 2 panneaux:1258057 - PanelOperation: SLIDING
Type - Autre - Catégorie: Portes; Nom de la famille: Placard coulissante - 2 panneaux
Type - Construction - Fonction: Intérieur; Fermeture du mur: Aucun
Type - Cotes - Epaisseur: 0.02 m; Hauteur: 2.1 m; Largeur: 1.2 m; Largeur de l'encadrement: 0.05 m
Type - Données d'identification - Marque de type: 62; Nom du type: Placard coulissante - 2 panneaux
Type - Graphismes - Profils: yes
Type - Matériaux et finitions - Encadrement: Placard - Encadrement; Panneau: Placard - Porte; Profil: Placard - Profil
Type - Propriétés analytiques - Construction analytique: <Aucun>
OverallHeight: 2.1 m; OverallWidth: 1.2 m
Pset_DoorCommon - IsExternal: no; Reference: Placard coulissante - 2 panneaux
Autre - ID hôte: Mur de base: Int. Platre 70 mm en blanc; Famille: Placard coulissante - 2 panneaux: Placard coulissante - 2 panneaux; Famille et type: Placard coulissante - 2 panneaux: Placard coulissante - 2 panneaux; Hauteur sous linteau: 2.1 m; ID du type: Placard coulissante - 2 panneaux: Placard coulissante - 2 panneaux; Type: Placard coulissante - 2 panneaux: Placard coulissante - 2 panneaux
Contraintes - Hauteur de l'appui: 0 m; Niveau: Niveau: ETAGE
Cotes - Surface: 2.734 m2; Volume: 0.0525 m3
Phase de construction - Phase de création: Nouvelle construction
Name (Placard coulissante - 2 panneaux:Placard coulissante - 2 panneaux:...) | Identifiant
1258057 | 603 | Group: Groupe de modèles:Pavillon type:1258082
1258058 | 604 | Group: Groupe de modèles:Pavillon type:1258082
1283138 | 627
1283139 | 628

# IfcFlowTerminal: Baignoire rectangulaire - Mur 70 x 170 (4)
Material: Céramique - Blanche
Pset_DistributionFlowElementCommon - Reference: Baignoire rectangulaire - Mur 70 x 170
Autre - Catégorie: Appareils sanitaires; Famille: Baignoire rectangulaire - Mur: Baignoire rectangulaire - Mur 70 x 170; Famille et type: Baignoire rectangulaire - Mur: Baignoire rectangulaire - Mur 70 x 170; ID du type: Baignoire rectangulaire - Mur: Baignoire rectangulaire - Mur 70 x 170; ID hôte: Mur de base: MITOYEN. Parpaing 10 + Isolant 10+ PLACO 2; Type: Baignoire rectangulaire - Mur: Baignoire rectangulaire - Mur 70 x 170; Nom de la famille: Baignoire rectangulaire - Mur
Contraintes - Niveau: Niveau: ETAGE
Cotes - Surface: 4.39661 m2; Volume: 0.0907752 m3; Hauteur: 0.38 m; Largeur: 1.7 m; Profondeur: 0.7 m
Phase de construction - Phase de création: Nouvelle construction
Données d'identification - Nom du type: Baignoire rectangulaire - Mur 70 x 170
Matériaux et finitions - Baignoire: Céramique - Blanche
Name (Baignoire rectangulaire - Mur:Baignoire rectangulaire - Mur 70 x 170:...) | In | Identifiant | Group
1308454 | 475 | 159
1308814 | ETAGE | 134 | Groupe de modèles:Pavillon type:1258082
1308817 | ETAGE | 143 | Groupe de modèles:Pavillon type:1258309
1360898 | ETAGE | 165 | Groupe de modèles:Pavillon type:1360776

# IfcFlowTerminal: Chauffe eau (4)
In: Plan des fondations Maisons 1 et 2
Pset_DistributionFlowElementCommon - Reference: Chauffe eau
Autre - Catégorie: Appareils sanitaires; Famille: Chauffe eau: Chauffe eau; Famille et type: Chauffe eau: Chauffe eau; ID du type: Chauffe eau: Chauffe eau; Type: Chauffe eau: Chauffe eau; Nom de la famille: Chauffe eau
Contraintes - Niveau: Niveau: Plan des fondations Maisons 1 et 2; Décalage: 0 m; Se déplace avec les éléments voisins: no; Hôte: Niveau : Plan des fondations Maisons 1 et 2
Cotes - Surface: 1.75347 m2; Volume: 0.44567 m3; Diamètre: 0.61 m; Hauteur: 1.525 m
Phase de construction - Phase de création: Nouvelle construction
Données d'identification - Nom du type: Chauffe eau
Texte - Libellé: .
Name (Chauffe eau:Chauffe eau:...) | Identifiant | Group
1278550 | 136 | Groupe de modèles:Pavillon type:1258082
1278756 | 142 | Groupe de modèles:Pavillon type:1258309
1283198 | 145
1360807 | 160 | Groupe de modèles:Pavillon type:1360776

# IfcFlowTerminal: FR_Lavabos (4)
Material: Lavabos - Porcelaine Vitrifiée Blanc, Robinet - Chrome
Pset_DistributionFlowElementCommon - Reference: FR_Lavabos
Autre - Catégorie: Appareils sanitaires; Famille: FR_Lavabos: FR_Lavabos; Famille et type: FR_Lavabos: FR_Lavabos; ID du type: FR_Lavabos: FR_Lavabos; Type: FR_Lavabos: FR_Lavabos; Nom de la famille: FR_Lavabos
Contraintes - Décalage: 0 m; Se déplace avec les éléments voisins: no; Niveau: Niveau: ETAGE; Hôte: Sol : Dalle Béton - 20 cm + FAUX PLAFOND
Cotes - Surface: 1.00609 m2; Volume: 0.023909 m3
Graphismes - Afficher la colonne: yes; Afficher le cache siphon: no
Phase de construction - Phase de création: Nouvelle construction
Données d'identification - Nom du type: FR_Lavabos
Matériaux et finitions - Colonne - Cache: Lavabos - Porcelaine Vitrifiée Blanc; Lavabos: Lavabos - Porcelaine Vitrifiée Blanc; Robinet: Robinet - Chrome
Name (FR_Lavabos:FR_Lavabos:...) | In | Identifiant | Group
1281590 | ETAGE | 133 | Groupe de modèles:Pavillon type:1258082
1281602 | ETAGE | 138 | Groupe de modèles:Pavillon type:1258309
1283205 | 475 | 146
1360810 | ETAGE | 161 | Groupe de modèles:Pavillon type:1360776

# IfcFlowTerminal: Gouttière 5.60 m blanc cassé 2 (12)
In: Plan de fondation
Material: Enduit blanc cassé
Pset_DistributionFlowElementCommon - Reference: Gouttière 5.60 m blanc cassé 2
Autre - Catégorie: Appareils sanitaires; Famille: Gouttière: Gouttière 5.60 m blanc cassé 2; Famille et type: Gouttière: Gouttière 5.60 m blanc cassé 2; ID du type: Gouttière: Gouttière 5.60 m blanc cassé 2; Type: Gouttière: Gouttière 5.60 m blanc cassé 2; Nom de la famille: Gouttière
Contraintes - Se déplace avec les éléments voisins: no; Hôte: Niveau : Terrain naturel; Niveau: Niveau: Terrain naturel
Cotes - Surface: 1.11825 m2; Volume: 0.0664135 m3; Débord toiture: 0.2 m; Diamètre: 0.12 m; Hauteur: 5.8 m; Larg. Regard: 0.2 m
Phase de construction - Phase de création: Nouvelle construction
Données d'identification - Nom du type: Gouttière 5.60 m blanc cassé 2
Matériaux et finitions - Tuyaux: Enduit blanc cassé
Name (Gouttière:Gouttière 5.60 m blanc cassé 2:...) | Décalage (m) | Identifiant | Group
1289670 | 1.25 | 147
1289789 | 0.7 | 148
1289950 | 1.25 | 149
1292380 | 1.25 | 153 | Groupe de modèles:Pavillon type:1258082
1292381 | 0.7 | 154 | Groupe de modèles:Pavillon type:1258082
1292382 | 1.25 | 155 | Groupe de modèles:Pavillon type:1258082
1292481 | 1.25 | 156 | Groupe de modèles:Pavillon type:1258309
1292482 | 0.7 | 157 | Groupe de modèles:Pavillon type:1258309
1292483 | 1.25 | 158 | Groupe de modèles:Pavillon type:1258309
1360838 | 1.25 | 162 | Groupe de modèles:Pavillon type:1360776
1360839 | 0.7 | 163 | Groupe de modèles:Pavillon type:1360776
1360840 | 1.25 | 164 | Groupe de modèles:Pavillon type:1360776

# IfcFlowTerminal: Lavabo encastrable (4)
Material: Métal - Chrome poli, Porcelaine - Blanche
Pset_DistributionFlowElementCommon - Reference: Lavabo encastrable
Autre - Catégorie: Appareils sanitaires; Famille: Lavabo encastrable: Lavabo encastrable; Famille et type: Lavabo encastrable: Lavabo encastrable; ID du type: Lavabo encastrable: Lavabo encastrable; Type: Lavabo encastrable: Lavabo encastrable; Nom de la famille: Lavabo encastrable
Contraintes - Niveau: Niveau: Plan des fondations Maisons 1 et 2; Décalage: 0 m; Se déplace avec les éléments voisins: no; Hôte: Niveau : Plan des fondations Maisons 1 et 2
Cotes - Surface: 0.294456 m2; Volume: 0.00257494 m3
Phase de construction - Phase de création: Nouvelle construction
Données d'identification - Nom du type: Lavabo encastrable
Matériaux et finitions - Matériau - Evier: Porcelaine - Blanche; Matériau - Robinet: Métal - Chrome poli
Name (Lavabo encastrable:Lavabo encastrable:...) | In | Identifiant | Group
1257989 | Plan des fondations Maisons 1 et 2 | 127 | Groupe de modèles:Pavillon type:1258082
1258222 | Plan des fondations Maisons 1 et 2 | 132 | Groupe de modèles:Pavillon type:1258309
1283088 | 471 | 140
1360712 | Plan des fondations Maisons 1 et 2 | 151 | Groupe de modèles:Pavillon type:1360776

# IfcFlowTerminal: M_Cuvette réservoir-3D (8)
Material: Porcelaine - Lin, Stratifié - Lin,Mat
Pset_DistributionFlowElementCommon - Reference: M_Cuvette réservoir-3D
Autre - Catégorie: Appareils sanitaires; Famille: M_Cuvette réservoir-3D: M_Cuvette réservoir-3D; Famille et type: M_Cuvette réservoir-3D: M_Cuvette réservoir-3D; ID du type: M_Cuvette réservoir-3D: M_Cuvette réservoir-3D; Type: M_Cuvette réservoir-3D: M_Cuvette réservoir-3D; Nom de la famille: M_Cuvette réservoir-3D
Contraintes - Décalage: 0 m; Se déplace avec les éléments voisins: no
Cotes - Surface: 1.88455 m2; Volume: 0.0312525 m3
Phase de construction - Phase de création: Nouvelle construction
Données d'identification - Nom du type: M_Cuvette réservoir-3D
Matériaux et finitions - Cuvette: Porcelaine - Lin; Siège: Stratifié - Lin,Mat
Name (M_Cuvette réservoir-3D:M_Cuvette réservoir-3D:...) | In | Niveau | Hôte | Identifiant | Group
1257988 | Plan des fondations Maisons 1 et 2 | Niveau: Plan des fondations Maisons 1 et 2 | Niveau : Plan des fondations Maisons 1 et 2 | 126 | Groupe de modèles:Pavillon type:1258082
1258052 | ETAGE | Niveau: ETAGE | Sol : Dalle Béton - 20 cm + FAUX PLAFOND | 130 | Groupe de modèles:Pavillon type:1258082
1258221 | Plan des fondations Maisons 1 et 2 | Niveau: Plan des fondations Maisons 1 et 2 | Niveau : Plan des fondations Maisons 1 et 2 | 131 | Groupe de modèles:Pavillon type:1258309
1258279 | ETAGE | Niveau: ETAGE | Sol : Dalle Béton - 20 cm + FAUX PLAFOND | 135 | Groupe de modèles:Pavillon type:1258309
1283087 | 471 | Niveau: Plan des fondations Maisons 1 et 2 | Niveau : Plan des fondations Maisons 1 et 2 | 139
1283133 | 476 | Niveau: ETAGE | Sol : Dalle Béton - 20 cm + FAUX PLAFOND | 144
1360711 | Plan des fondations Maisons 1 et 2 | Niveau: Plan des fondations Maisons 1 et 2 | Niveau : Plan des fondations Maisons 1 et 2 | 150 | Groupe de modèles:Pavillon type:1360776
1360752 | ETAGE | Niveau: ETAGE | Sol : Dalle Béton - 20 cm + FAUX PLAFOND | 152 | Groupe de modèles:Pavillon type:1360776

# IfcFooting: Semelle filante:semelle excentrée ht 30 cm larg 40 cm (8)
In: Plan de fondation
PredefinedType: STRIP_FOOTING; Material: Béton
Autre - Catégorie: Fondations; Famille: Semelle filante: semelle excentrée ht 30 cm larg 40 cm; Famille et type: Semelle filante: semelle excentrée ht 30 cm larg 40 cm; ID du type: Semelle filante: semelle excentrée ht 30 cm larg 40 cm; Type: Semelle filante: semelle excentrée ht 30 cm larg 40 cm; Nom de la famille: Semelle filante
Cotes - Elévation à la base: -1.3 m; Elévation en haut: -1 m; Largeur: 0.23 m; Longueur de l'extension de fin par défaut: 0 m; Ne pas couper aux insertions: no; Epaisseur de fondation: 0.3 m; Largeur côté extérieur: 0.13 m; Largeur côté intérieur: 0 m
Phase de construction - Phase de création: Nouvelle construction
Structure - Activer le modèle analytique: no; Enrobage d'armature - Autres faces: Paramètres de l'enrobage d'armature: Enrobage d'armature 1; Enrobage d'armature - Face inférieure: Paramètres de l'enrobage d'armature: Enrobage d'armature 1; Enrobage d'armature - Face supérieure: Paramètres de l'enrobage d'armature: Enrobage d'armature 1; Utilisation structurelle: Soutènement
Données d'identification - Nom du type: semelle excentrée ht 30 cm larg 40 cm
Matériaux et finitions - Matériau structurel: Béton
Name (Semelle filante:semelle excentrée ht 30 cm larg 40 cm:...) | Longueur (m) | Surface (m2) | Volume (m3) | Group
1332323 | 5.19619 | 1.16062 | 0.348187
1332336 | 6.10381 | 1.35838 | 0.407513
1332529 | 5.19619 | 1.27562 | 0.382687 | Groupe de modèles:Pavillon type:1258082
1332531 | 6.10381 | 1.32338 | 0.397013 | Groupe de modèles:Pavillon type:1258082
1332549 | 5.19619 | 1.16062 | 0.348187 | Groupe de modèles:Pavillon type:1258309
1332551 | 6.10381 | 1.32338 | 0.397013 | Groupe de modèles:Pavillon type:1258309
1360920 | 5.19619 | 1.13926 | 0.341779 | Groupe de modèles:Pavillon type:1360776
1360922 | 5.90381 | 1.29902 | 0.389706 | Groupe de modèles:Pavillon type:1360776

# IfcFooting: Semelle filante:semelle ht 30 cm larg 50 cm (24)
In: Plan de fondation
PredefinedType: STRIP_FOOTING; Material: Béton
Autre - Catégorie: Fondations; Famille: Semelle filante: semelle ht 30 cm larg 50 cm; Famille et type: Semelle filante: semelle ht 30 cm larg 50 cm; ID du type: Semelle filante: semelle ht 30 cm larg 50 cm; Type: Semelle filante: semelle ht 30 cm larg 50 cm; Nom de la famille: Semelle filante
Cotes - Elévation à la base: -1.3 m; Elévation en haut: -1 m; Largeur: 0.5 m; Epaisseur de fondation: 0.3 m; Largeur côté extérieur: 0.15 m; Largeur côté intérieur: 0.15 m; Longueur de l'extension de fin par défaut: 0 m; Ne pas couper aux insertions: no
Phase de construction - Phase de création: Nouvelle construction
Structure - Activer le modèle analytique: no; Enrobage d'armature - Autres faces: Paramètres de l'enrobage d'armature: Enrobage d'armature 1; Enrobage d'armature - Face inférieure: Paramètres de l'enrobage d'armature: Enrobage d'armature 1; Enrobage d'armature - Face supérieure: Paramètres de l'enrobage d'armature: Enrobage d'armature 1; Utilisation structurelle: Soutènement
Données d'identification - Nom du type: semelle ht 30 cm larg 50 cm
Matériaux et finitions - Matériau structurel: Béton
Name (Semelle filante:semelle ht 30 cm larg 50 cm:...) | Longueur (m) | Surface (m2) | Volume (m3) | Group
1332244 | 7.40826 | 3.77913 | 1.13374
1332257 | 8.1 | 3.15 | 0.945
1332279 | 4.33826 | 2.16913 | 0.650739
1332292 | 2.8 | 1.5 | 0.45
1332301 | 3.52 | 1.585 | 0.4755
1332310 | 8.3 | 3.9 | 1.17
1332515 | 7.40826 | 3.66413 | 1.09924 | Groupe de modèles:Pavillon type:1258082
1332517 | 8.1 | 3.15 | 0.945 | Groupe de modèles:Pavillon type:1258082
1332521 | 4.33826 | 2.16913 | 0.650739 | Groupe de modèles:Pavillon type:1258082
1332523 | 2.8 | 1.5 | 0.45 | Groupe de modèles:Pavillon type:1258082
1332525 | 3.52 | 1.635 | 0.4905 | Groupe de modèles:Pavillon type:1258082
1332527 | 8.3 | 3.9 | 1.17 | Groupe de modèles:Pavillon type:1258082
1332535 | 7.40826 | 3.77913 | 1.13374 | Groupe de modèles:Pavillon type:1258309
1332537 | 8.1 | 3.15 | 0.945 | Groupe de modèles:Pavillon type:1258309
1332541 | 4.33826 | 2.16913 | 0.650739 | Groupe de modèles:Pavillon type:1258309
1332543 | 2.8 | 1.5 | 0.45 | Groupe de modèles:Pavillon type:1258309
1332545 | 3.52 | 1.635 | 0.4905 | Groupe de modèles:Pavillon type:1258309
1332547 | 8.3 | 3.9 | 1.17 | Groupe de modèles:Pavillon type:1258309
1360908 | 7.40403 | 3.77701 | 1.1331 | Groupe de modèles:Pavillon type:1360776
1360910 | 8.1 | 3.15 | 0.945 | Groupe de modèles:Pavillon type:1360776
1360912 | 4.33826 | 2.04906 | 0.614719 | Groupe de modèles:Pavillon type:1360776
1360914 | 2.8 | 1.5 | 0.45 | Groupe de modèles:Pavillon type:1360776
1360916 | 3.61577 | 1.63288 | 0.489865 | Groupe de modèles:Pavillon type:1360776
1360918 | 8.3 | 2.87698 | 0.863093 | Groupe de modèles:Pavillon type:1360776

# IfcFurnishingElement: 1000 mm x 2000 mm 3 (8)
Type - ElementType: 1000 mm x 2000 mm 3; Material: Textile - Bleu pâle, Bois - Teck, Plastique - Noir
Type - Autre - Catégorie: Mobilier; Nom de la famille: Lit à lattes
Type - Cotes - Largeur: 1 m
Type - Données d'identification - Nom du type: 1000 mm x 2000 mm 3
Type - Matériaux et finitions - Matériau des lattes: Bois - Teck; Matériau des pieds: Plastique - Noir
Autre - Famille: Lit à lattes: 1000 mm x 2000 mm 3; Famille et type: Lit à lattes: 1000 mm x 2000 mm 3; ID du type: Lit à lattes: 1000 mm x 2000 mm 3; Type: Lit à lattes: 1000 mm x 2000 mm 3
Contraintes - Décalage: 0 m; Se déplace avec les éléments voisins: no; Niveau: Niveau: ETAGE; Hôte: Sol : Dalle Béton - 20 cm + FAUX PLAFOND
Cotes - Surface: 5.00052 m2; Volume: 0.343232 m3
Matériaux et finitions - Matériau de matelas: Textile - Bleu pâle
Phase de construction - Phase de création: Nouvelle construction
Name (Lit à lattes:1000 mm x 2000 mm 3:...) | In | Group
1273169 | ETAGE | Groupe de modèles:Pavillon type:1258082
1273180 | ETAGE | Groupe de modèles:Pavillon type:1258309
1277797 | ETAGE | Groupe de modèles:Pavillon type:1258082
1277809 | ETAGE | Groupe de modèles:Pavillon type:1258309
1283186 | 474
1283193 | 473
1360798 | ETAGE | Groupe de modèles:Pavillon type:1360776
1360803 | ETAGE | Groupe de modèles:Pavillon type:1360776

# IfcFurnishingElement: 1100 mm x 1100 mm x 760 mm (4)
Type - ElementType: 1100 mm x 1100 mm x 760 mm; Material: Bois - Exotique
Type - Autre - Catégorie: Mobilier; Nom de la famille: MS-Table et chaises
Type - Contraintes - C1: yes; C2: no
Type - Cotes - Hauteur: 0.76 m; Largeur: 1.1 m; Profondeur: 1.1 m
Type - Données d'identification - Nom du type: 1100 mm x 1100 mm x 760 mm
Type - Matériaux et finitions - Finition: Bois - Exotique
Autre - Famille: MS-Table et chaises: 1100 mm x 1100 mm x 760 mm; Famille et type: MS-Table et chaises: 1100 mm x 1100 mm x 760 mm; ID du type: MS-Table et chaises: 1100 mm x 1100 mm x 760 mm; Type: MS-Table et chaises: 1100 mm x 1100 mm x 760 mm
Contraintes - Niveau: Niveau: Plan des fondations Maisons 1 et 2; Décalage: 0 m; Se déplace avec les éléments voisins: no; Hôte: Niveau : Plan des fondations Maisons 1 et 2
Cotes - Surface: 7.6208 m2; Volume: 0.153515 m3
Phase de construction - Phase de création: Nouvelle construction
Name (MS-Table et chaises:1100 mm x 1100 mm x 760 mm:...) | In | Group
1278547 | Plan des fondations Maisons 1 et 2 | Groupe de modèles:Pavillon type:1258082
1278753 | Plan des fondations Maisons 1 et 2 | Groupe de modèles:Pavillon type:1258309
1283196 | 470
1360805 | Plan des fondations Maisons 1 et 2 | Groupe de modèles:Pavillon type:1360776

# IfcFurnishingElement: 1400 mm x 2000 mm 2, Lit à lattes:1400 mm x 2000 mm 2:1283183
In: 477
Type - ElementType: 1400 mm x 2000 mm 2; Material: Textile - Bleu pâle, Bois - Teck, Plastique - Noir
Type - Autre - Catégorie: Mobilier; Nom de la famille: Lit à lattes
Type - Cotes - Largeur: 1.4 m
Type - Données d'identification - Nom du type: 1400 mm x 2000 mm 2
Type - Matériaux et finitions - Matériau des lattes: Bois - Teck; Matériau des pieds: Plastique - Noir
Autre - Famille: Lit à lattes: 1400 mm x 2000 mm 2; Famille et type: Lit à lattes: 1400 mm x 2000 mm 2; ID du type: Lit à lattes: 1400 mm x 2000 mm 2; Type: Lit à lattes: 1400 mm x 2000 mm 2
Contraintes - Se déplace avec les éléments voisins: no; Niveau: Niveau: ETAGE; Décalage: 0.02 m; Hôte: Sol : Dalle Béton - 20 cm + FAUX PLAFOND
Cotes - Surface: 6.85102 m2; Volume: 0.507944 m3
Matériaux et finitions - Matériau de matelas: Textile - Bleu pâle
Phase de construction - Phase de création: Nouvelle construction

# IfcFurnishingElement: 1525 mm x 600 mm (4)
Type - ElementType: 1525 mm x 600 mm; Material: Bois - Mélaminé ivoire, Métal - Chrome, Bois - Cerisier
Type - Autre - Catégorie: Mobilier; Nom de la famille: Bureau commun
Type - Cotes - Hauteur: 0.762 m; Hauteur de pied: 0.152 m; Largeur: 0.6 m; Longueur: 1.45 m
Type - Données d'identification - Nom du type: 1525 mm x 600 mm
Type - Matériaux et finitions - Bureau: Bois - Mélaminé ivoire; HAUT: Bois - Cerisier; Poignées - pieds: Métal - Chrome
Autre - Famille: Bureau commun: 1525 mm x 600 mm; Famille et type: Bureau commun: 1525 mm x 600 mm; ID du type: Bureau commun: 1525 mm x 600 mm; Type: Bureau commun: 1525 mm x 600 mm
Contraintes - Se déplace avec les éléments voisins: no; Niveau: Niveau: ETAGE; Hôte: Sol : Dalle Béton - 20 cm + FAUX PLAFOND
Cotes - Surface: 3.60045 m2; Volume: 0.343137 m3
Phase de construction - Phase de création: Nouvelle construction
Name (Bureau commun:1525 mm x 600 mm:...) | In | Group
1273168 | ETAGE | Groupe de modèles:Pavillon type:1258082
1273179 | ETAGE | Groupe de modèles:Pavillon type:1258309
1283185 | 474
1360797 | ETAGE | Groupe de modèles:Pavillon type:1360776

# IfcFurnishingElement: 1525 mm x 762 mm (4)
Type - ElementType: 1525 mm x 762 mm; Material: Bois - Mélaminé ivoire, Métal - Chrome, Bois - Cerisier
Type - Autre - Catégorie: Mobilier; Nom de la famille: Bureau commun
Type - Cotes - Hauteur: 0.762 m; Hauteur de pied: 0.152 m; Largeur: 0.762 m; Longueur: 1.525 m
Type - Données d'identification - Nom du type: 1525 mm x 762 mm
Type - Matériaux et finitions - Bureau: Bois - Mélaminé ivoire; HAUT: Bois - Cerisier; Poignées - pieds: Métal - Chrome
Autre - Famille: Bureau commun: 1525 mm x 762 mm; Famille et type: Bureau commun: 1525 mm x 762 mm; ID du type: Bureau commun: 1525 mm x 762 mm; Type: Bureau commun: 1525 mm x 762 mm
Contraintes - Se déplace avec les éléments voisins: no; Niveau: Niveau: ETAGE; Hôte: Sol : Dalle Béton - 20 cm + FAUX PLAFOND
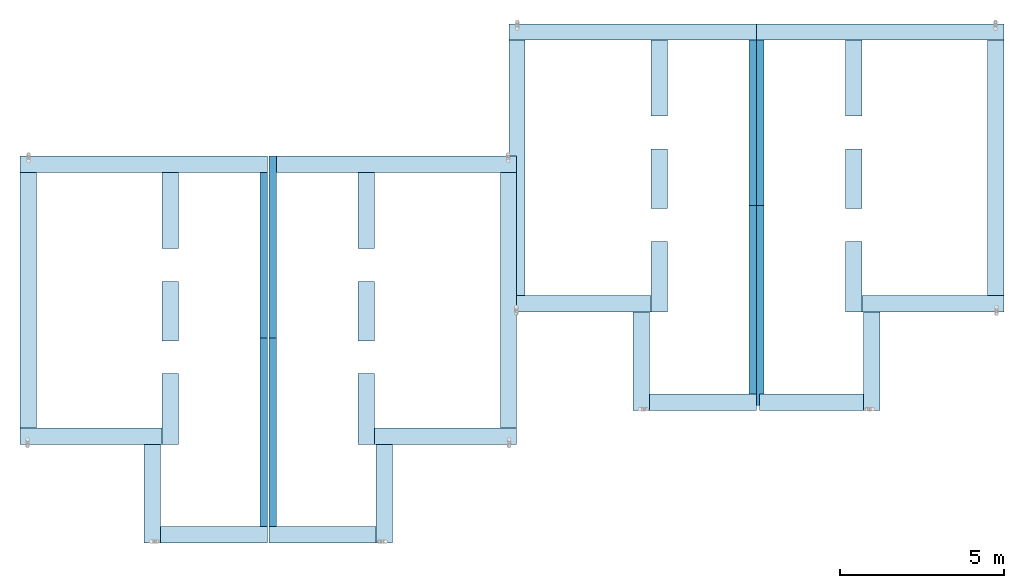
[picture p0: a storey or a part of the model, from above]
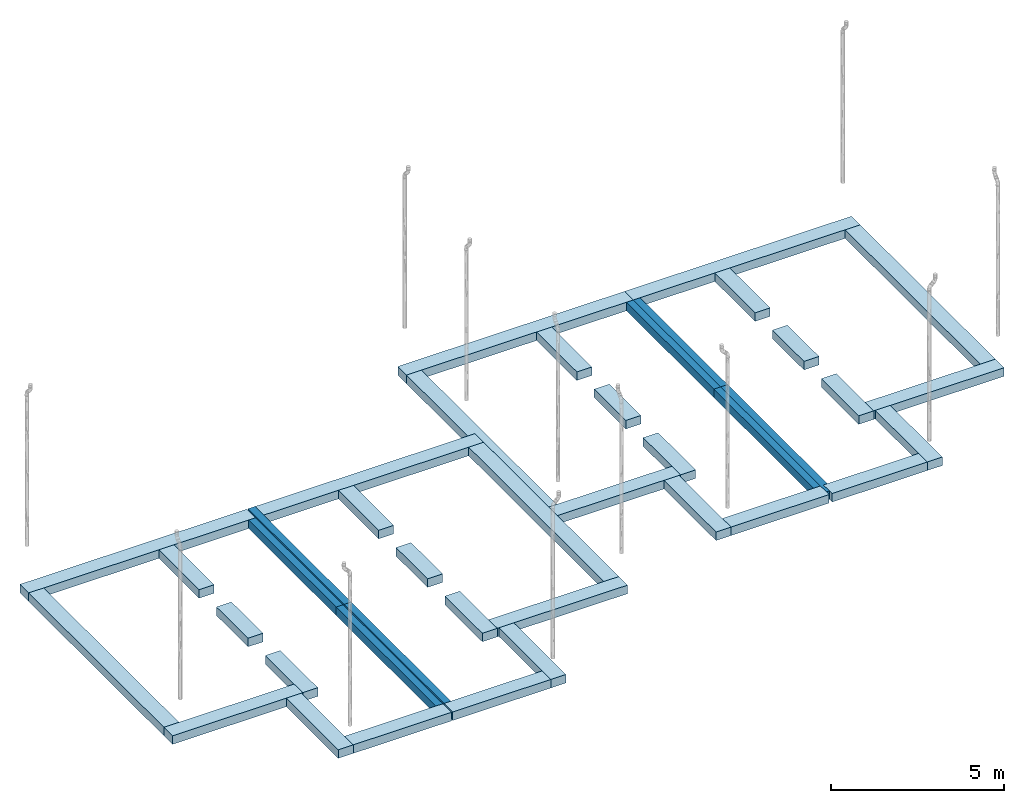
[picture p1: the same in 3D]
Properties of the parts of a building model (IFC2X3), part 2 of 3

# IfcFurnishingElement: 1525 mm x 762 mm (4)
Cotes - Surface: 4.27423 m2; Volume: 0.432091 m3
Phase de construction - Phase de création: Nouvelle construction
Name (Bureau commun:1525 mm x 762 mm:...) | In | Group
1273166 | ETAGE | Groupe de modèles:Pavillon type:1258082
1273177 | ETAGE | Groupe de modèles:Pavillon type:1258309
1283184 | 473
1360796 | ETAGE | Groupe de modèles:Pavillon type:1360776

# IfcFurnishingElement: 1900 mm x 2000 mm (3)
In: ETAGE
Type - ElementType: 1900 mm x 2000 mm; Material: Textile - Bleu pâle, Bois - Teck, Plastique - Noir
Type - Autre - Catégorie: Mobilier; Nom de la famille: Lit à lattes
Type - Cotes - Largeur: 1.9 m
Type - Données d'identification - Nom du type: 1900 mm x 2000 mm
Type - Matériaux et finitions - Matériau des lattes: Bois - Teck; Matériau des pieds: Plastique - Noir
Autre - Famille: Lit à lattes: 1900 mm x 2000 mm; Famille et type: Lit à lattes: 1900 mm x 2000 mm; ID du type: Lit à lattes: 1900 mm x 2000 mm; Type: Lit à lattes: 1900 mm x 2000 mm
Contraintes - Décalage: 0 m; Se déplace avec les éléments voisins: no; Niveau: Niveau: ETAGE; Hôte: Sol : Dalle Béton - 20 cm + FAUX PLAFOND
Cotes - Surface: 9.16415 m2; Volume: 0.713835 m3
Matériaux et finitions - Matériau de matelas: Textile - Bleu pâle
Phase de construction - Phase de création: Nouvelle construction
Name (Lit à lattes:1900 mm x 2000 mm:...) | Group
1273162 | Groupe de modèles:Pavillon type:1258082
1273173 | Groupe de modèles:Pavillon type:1258309
1360795 | Groupe de modèles:Pavillon type:1360776

# IfcFurnishingElement: 3 emplacements (230 x 92 cm) (4)
Type - ElementType: 3 emplacements (230 x 92 cm); Material: Métal - Chrome, Cuir - Bordeaux
Type - Autre - Catégorie: Mobilier; Nom de la famille: Banquette - 3 places
Type - Données d'identification - Nom du type: 3 emplacements (230 x 92 cm)
Type - Matériaux et finitions - Matériau de jambe: Métal - Chrome
Autre - Famille: Banquette - 3 places: 3 emplacements (230 x 92 cm); Famille et type: Banquette - 3 places: 3 emplacements (230 x 92 cm); ID du type: Banquette - 3 places: 3 emplacements (230 x 92 cm); Type: Banquette - 3 places: 3 emplacements (230 x 92 cm)
Contraintes - Niveau: Niveau: Plan des fondations Maisons 1 et 2; Décalage: 0 m; Se déplace avec les éléments voisins: no; Hôte: Niveau : Plan des fondations Maisons 1 et 2
Cotes - Surface: 3.41489 m2; Volume: 0.41266 m3
Matériaux et finitions - Matériau de sofa: Cuir - Bordeaux
Phase de construction - Phase de création: Nouvelle construction
Name (Banquette - 3 places:3 emplacements (230 x 92 cm):...) | In | Group
1278549 | Plan des fondations Maisons 1 et 2 | Groupe de modèles:Pavillon type:1258082
1278755 | Plan des fondations Maisons 1 et 2 | Groupe de modèles:Pavillon type:1258309
1283197 | 470
1360806 | Plan des fondations Maisons 1 et 2 | Groupe de modèles:Pavillon type:1360776

# IfcFurnishingElement: Table basse - Verre (4)
Type - ElementType: Table basse - Verre; Material: Verre - Givré, Métal - Alu brossé
Type - Autre - Catégorie: Mobilier; Nom de la famille: Table basse - Verre
Type - Cotes - Hauteur: 0.385 m; Largeur: 1 m; Profondeur: 0.53 m
Type - Données d'identification - Nom du type: Table basse - Verre
Type - Matériaux et finitions - Structure tubulaire: Métal - Alu brossé; Verre: Verre - Givré
Autre - Famille: Table basse - Verre: Table basse - Verre; Famille et type: Table basse - Verre: Table basse - Verre; ID du type: Table basse - Verre: Table basse - Verre; Type: Table basse - Verre: Table basse - Verre
Contraintes - Niveau: Niveau: Plan des fondations Maisons 1 et 2; Décalage: 0 m; Se déplace avec les éléments voisins: no; Hôte: Niveau : Plan des fondations Maisons 1 et 2
Cotes - Surface: 1.38525 m2; Volume: 0.0150136 m3
Phase de construction - Phase de création: Nouvelle construction
Name (Table basse - Verre:Table basse - Verre:...) | In | Group
1278546 | Plan des fondations Maisons 1 et 2 | Groupe de modèles:Pavillon type:1258082
1278752 | Plan des fondations Maisons 1 et 2 | Groupe de modèles:Pavillon type:1258309
1283195 | 470
1360804 | Plan des fondations Maisons 1 et 2 | Groupe de modèles:Pavillon type:1360776

# IfcGroup: Groupe de modèles:Pavillon type (3)
Autre - Catégorie: Groupes de modèles; Famille: Groupe de modèles: Pavillon type; Famille et type: Groupe de modèles: Pavillon type; ID du type: Groupe de modèles: Pavillon type; Type: Groupe de modèles: Pavillon type; Nom de la famille: Groupe de modèles
Contraintes - Décalage du niveau de l'origine: 0 m; Niveau de référence: Niveau: Plan des fondations Maisons 1 et 2
Données d'identification - Nom du type: Pavillon type
Name (Groupe de modèles:Pavillon type:...)
1258082
1258309
1360776

# IfcGroup: Groupe de modèles:muret technique (4)
Autre - Catégorie: Groupes de modèles; Famille: Groupe de modèles: muret technique; Famille et type: Groupe de modèles: muret technique; ID du type: Groupe de modèles: muret technique; Type: Groupe de modèles: muret technique; Nom de la famille: Groupe de modèles
Contraintes - Décalage du niveau de l'origine: 0 m
Données d'identification - Nom du type: muret technique
Name (Groupe de modèles:muret technique:...) | Niveau de référence
1301639 | Niveau: RDC
1304961 | Niveau: Plan des fondations Maisons 1 et 2
1305108 | Niveau: Plan des fondations Maisons 1 et 2
1305401 | Niveau: Plan des fondations Maisons 1 et 2

# IfcOpeningElement: Opening (93)
Name | In
 | ETAGE | Group: Groupe de modèles:Pavillon type:1258082
 | ETAGE | Group: Groupe de modèles:Pavillon type:1258309
 | ETAGE
2 x Mur de base:modénateurs ep 2 cm gris:804914 | Plan des fondations Maisons 1 et 2
2 x Mur de base:modénateurs ep 2 cm gris:804914 | Plan des fondations Maisons 1 et 2 | Group: Groupe de modèles:Pavillon type:1258082
2 x Mur de base:modénateurs ep 2 cm gris:804914 | Plan des fondations Maisons 1 et 2 | Group: Groupe de modèles:Pavillon type:1258309
Mur de base:Ext. Parpaing 20:1330094 | vs | Autre - Catégorie: Ouverture de mur rectiligne rectangulaire; Contraintes - Contrainte inférieure: Niveau: vs; Contrainte supérieure: Niveau: RDC; Décalage inférieur: -0.193146 m; Décalage supérieur: -0.2 m; Hauteur non contrainte: 0.793146 m; Phase de construction - Phase de création: Nouvelle construction
Mur de base:Ext. Parpaing 20:1332173 | vs | Group: Groupe de modèles:Pavillon type:1258082; Autre - Catégorie: Ouverture de mur rectiligne rectangulaire; Contraintes - Contrainte inférieure: Niveau: vs; Contrainte supérieure: Niveau: Plan des fondations Maisons 1 et 2; Décalage inférieur: -0.193146 m; Décalage supérieur: -0.2 m; Hauteur non contrainte: 0.793146 m; Phase de construction - Phase de création: Nouvelle construction
Mur de base:Ext. Parpaing 20:1332186 | vs | Group: Groupe de modèles:Pavillon type:1258309; Autre - Catégorie: Ouverture de mur rectiligne rectangulaire; Contraintes - Contrainte inférieure: Niveau: vs; Contrainte supérieure: Niveau: Plan des fondations Maisons 1 et 2; Décalage inférieur: -0.193146 m; Décalage supérieur: -0.2 m; Hauteur non contrainte: 0.793146 m; Phase de construction - Phase de création: Nouvelle construction
 | ETAGE | Group: Groupe de modèles:Pavillon type:1360776
2 x Mur de base:modénateurs ep 2 cm gris:804914 | Plan des fondations Maisons 1 et 2 | Group: Groupe de modèles:Pavillon type:1360776
Mur de base:Ext. Parpaing 20:1360907 | vs | Group: Groupe de modèles:Pavillon type:1360776; Autre - Catégorie: Ouverture de mur rectiligne rectangulaire; Contraintes - Contrainte inférieure: Niveau: vs; Contrainte supérieure: Niveau: Plan des fondations Maisons 1 et 2; Décalage inférieur: -0.193146 m; Décalage supérieur: -0.2 m; Hauteur non contrainte: 0.793146 m; Phase de construction - Phase de création: Nouvelle construction
 | Plan des fondations Maisons 1 et 2 | Group: Groupe de modèles:Pavillon type:1360776
2 x Mur de base:Ext. Parpaing 20 + Isolant 10 enduit blanc cassé:1257898 | Plan des fondations Maisons 1 et 2
2 x Mur de base:Ext. Parpaing 20 + Isolant 10 enduit blanc cassé:1257900 | Plan des fondations Maisons 1 et 2
Mur de base:Ext. Parpaing 2 + 20 + 2 gris:1257904 | Plan des fondations Maisons 1 et 2
FR_Simple (R):83 x 204 - (80):1257906:1 | Plan des fondations Maisons 1 et 2
FR_Simple (R):73 x 204 - (70):1257987:1 | Plan des fondations Maisons 1 et 2
2 x Mur de base:Ext. Parpaing 20 + Isolant 10 enduit blanc cassé:1258029 | ETAGE
Mur de base:Ext. Parpaing 20 + Isolant 10 enduit blanc cassé:1258031 | ETAGE
Mur de base:Ext. Parpaing 20 + Isolant 10 enduit gris:1258033 | ETAGE
FR_Simple (R):73 x 204 - (70):1258044:1 | ETAGE
FR_Simple (R):73 x 204 - (70):1258045:1 | ETAGE
FR_Simple (R):73 x 204 - (70):1258043:1 | ETAGE
Placard coulissante - 2 panneaux:Placard coulissante - 2 panneaux:1258058:1 | ETAGE
FR_Simple (R):73 x 204 - (70):1258046:1 | ETAGE
FR_Simple (R):73 x 204 - (70):1258042:1 | ETAGE
Placard coulissante - 2 panneaux:Placard coulissante - 2 panneaux:1258057:1 | ETAGE
2 x Mur de base:Ext. Parpaing 20 + Isolant 10 enduit blanc cassé:1258132 | Plan des fondations Maisons 1 et 2
2 x Mur de base:Ext. Parpaing 20 + Isolant 10 enduit blanc cassé:1258134 | Plan des fondations Maisons 1 et 2
Mur de base:Ext. Parpaing 2 + 20 + 2 gris:1258138 | Plan des fondations Maisons 1 et 2
FR_Simple (R):83 x 204 - (80):1258140:1 | Plan des fondations Maisons 1 et 2
FR_Simple (R):73 x 204 - (70):1258220:1 | Plan des fondations Maisons 1 et 2
2 x Mur de base:Ext. Parpaing 20 + Isolant 10 enduit blanc cassé:1258256 | ETAGE
Mur de base:Ext. Parpaing 20 + Isolant 10 enduit blanc cassé:1258258 | ETAGE
Mur de base:Ext. Parpaing 20 + Isolant 10 enduit gris:1258260 | ETAGE
FR_Simple (R):73 x 204 - (70):1258271:1 | ETAGE
FR_Simple (R):73 x 204 - (70):1258272:1 | ETAGE
FR_Simple (R):73 x 204 - (70):1258270:1 | ETAGE
Placard coulissante - 2 panneaux:Placard coulissante - 2 panneaux:1258285:1 | ETAGE
FR_Simple (R):73 x 204 - (70):1258273:1 | ETAGE
FR_Simple (R):73 x 204 - (70):1258269:1 | ETAGE
Placard coulissante - 2 panneaux:Placard coulissante - 2 panneaux:1258284:1 | ETAGE
Mur de base:Int. Platre 70 mm en blanc:1277791 | ETAGE
Mur de base:Int. Platre 70 mm en blanc:1277803 | ETAGE
2 x Mur de base:Ext. Parpaing 20 + Isolant 10 enduit blanc cassé:1282998 | Plan des fondations Maisons 1 et 2
2 x Mur de base:Ext. Parpaing 20 + Isolant 10 enduit blanc cassé:1283000 | Plan des fondations Maisons 1 et 2
Mur de base:Ext. Parpaing 2 + 20 + 2 gris:1283004 | Plan des fondations Maisons 1 et 2
FR_Simple (R):83 x 204 - (80):1283006:1 | Plan des fondations Maisons 1 et 2
FR_Simple (R):73 x 204 - (70):1283086:1 | Plan des fondations Maisons 1 et 2
2 x Mur de base:Ext. Parpaing 20 + Isolant 10 enduit blanc cassé:1283112 | ETAGE
Mur de base:Ext. Parpaing 20 + Isolant 10 enduit blanc cassé:1283114 | ETAGE
Mur de base:Ext. Parpaing 20 + Isolant 10 enduit gris:1283116 | ETAGE
FR_Simple (R):73 x 204 - (70):1283127:1 | ETAGE
FR_Simple (R):73 x 204 - (70):1283128:1 | ETAGE
FR_Simple (R):73 x 204 - (70):1283126:1 | ETAGE
Placard coulissante - 2 panneaux:Placard coulissante - 2 panneaux:1283139:1 | ETAGE
FR_Simple (R):73 x 204 - (70):1283129:1 | ETAGE
FR_Simple (R):73 x 204 - (70):1283125:1 | ETAGE
Placard coulissante - 2 panneaux:Placard coulissante - 2 panneaux:1283138:1 | ETAGE
Mur de base:Int. Platre 70 mm en blanc:1283189 | ETAGE
2 x Mur de base:Ext. Parpaing 20 + Isolant 10 enduit blanc cassé:1360629 | Plan des fondations Maisons 1 et 2
2 x Mur de base:Ext. Parpaing 20 + Isolant 10 enduit blanc cassé:1360631 | Plan des fondations Maisons 1 et 2
Mur de base:Ext. Parpaing 2 + 20 + 2 gris:1360635 | Plan des fondations Maisons 1 et 2
FR_Simple (R):83 x 204 - (80):1360637:1 | Plan des fondations Maisons 1 et 2
FR_Simple (R):73 x 204 - (70):1360710:1 | Plan des fondations Maisons 1 et 2
2 x Mur de base:Ext. Parpaing 20 + Isolant 10 enduit blanc cassé:1360732 | ETAGE
Mur de base:Ext. Parpaing 20 + Isolant 10 enduit blanc cassé:1360734 | ETAGE
Mur de base:Ext. Parpaing 20 + Isolant 10 enduit gris:1360736 | ETAGE
FR_Simple (R):73 x 204 - (70):1360747:1 | ETAGE
FR_Simple (R):73 x 204 - (70):1360748:1 | ETAGE
FR_Simple (R):73 x 204 - (70):1360746:1 | ETAGE
Placard coulissante - 2 panneaux:Placard coulissante - 2 panneaux:1360758:1 | ETAGE
FR_Simple (R):73 x 204 - (70):1360749:1 | ETAGE
FR_Simple (R):73 x 204 - (70):1360745:1 | ETAGE
Placard coulissante - 2 panneaux:Placard coulissante - 2 panneaux:1360757:1 | ETAGE
Mur de base:Int. Platre 70 mm en blanc:1360801 | ETAGE

# IfcOpeningElement: Recess (4)
In: Plan des fondations Maisons 1 et 2
Autre - Catégorie: Site; Famille: Boîte aux lettres encastrée: 350mm x 500mm beige; Famille et type: Boîte aux lettres encastrée: 350mm x 500mm beige; ID du type: Boîte aux lettres encastrée: 350mm x 500mm beige; ID hôte: Mur de base: Ext. Parpaing 20 + 2 x 1.5; Type: Boîte aux lettres encastrée: 350mm x 500mm beige; Nom de la famille: Boîte aux lettres encastrée
Contraintes - Niveau: Niveau: Plan des fondations Maisons 1 et 2; Elévation: 0.787402 m
Cotes - Surface: 0.749968 m2; Volume: 0.00726675 m3; Décalage du mur: 0.03 m; Haut de la boîte: 1.1 m; Hauteur de la boîte aux lettres: 0.5 m; Hauteur de la fente: 0.05 m; Largeur de la boîte aux lettres: 0.35 m; Largeur de la fente: 0.25 m; Profondeur de la boîte aux lettres: 0.25 m
Phase de construction - Phase de création: Nouvelle construction
Données d'identification - Nom du type: 350mm x 500mm beige
Matériaux et finitions - Matériau - Boîte aux lettres: Peinture - Gris
Name (Mur de base:Ext. Parpaing 20 + 2 x 1.5:...) | Group
1300698 | Groupe de modèles:muret technique:1301639
1304946 | Groupe de modèles:muret technique:1304961
1305093 | Groupe de modèles:muret technique:1305108
1305386 | Groupe de modèles:muret technique:1305401

# IfcRailing: Garde-corps:Type Bateau 1,25 m (4)
In: ETAGE
Material: noir acier, Finition Peinture Grise
Pset_RailingCommon - IsExternal: no; Reference: Type Bateau 1,25 m; Height: 1.2192 m
Autre - Catégorie: Garde-corps; Famille: Garde-corps: Type Bateau 1,25 m; Famille et type: Garde-corps: Type Bateau 1,25 m; ID du type: Garde-corps: Type Bateau 1,25 m; Type: Garde-corps: Type Bateau 1,25 m; Nom de la famille: Garde-corps
Contraintes - Décalage marche/limon à la française: 0 m; Décalage inférieur: -0.1 m; Niveau de base: Niveau: ETAGE
Cotes - Longueur: 0.872481 m
Phase de construction - Phase de création: Nouvelle construction
Construction - Connexion des traverses: Ajuster; Joints d'angle: Ajouter des segments verticaux/horizontaux; Joints tangents: Prolonger la traverse jusqu'à; Réglage de la hauteur du palier: 0 m; Utiliser le réglage de la hauteur du palier: Non; Décalage des barreaux: -0.03 m; Hauteur du garde-corps: 1.25 m
Données d'identification - Nom du type: Type Bateau 1,25 m
Main courante 1 - Position: Aucune; sets with these values: 2
Traverse haute - Hauteur: 1.2192 m
Name (Garde-corps:Type Bateau 1,25 m:...) | Group
1356151
1356236 | Groupe de modèles:Pavillon type:1258082
1356243 | Groupe de modèles:Pavillon type:1258309
1360964 | Groupe de modèles:Pavillon type:1360776

# IfcRailing: Garde-corps:Type Bateau 1,50 m (21)
In: Plan des fondations Maisons 1 et 2
Material: Bois, Finition Peinture Grise
Pset_RailingCommon - IsExternal: no; Reference: Type Bateau 1,50 m; Height: 1.2192 m
Autre - Catégorie: Garde-corps; Famille: Garde-corps: Type Bateau 1,50 m; Famille et type: Garde-corps: Type Bateau 1,50 m; ID du type: Garde-corps: Type Bateau 1,50 m; Type: Garde-corps: Type Bateau 1,50 m; Nom de la famille: Garde-corps
Phase de construction - Phase de création: Nouvelle construction
Construction - Connexion des traverses: Ajuster; Décalage des barreaux: -0.03 m; Hauteur du garde-corps: 1.5 m; Joints d'angle: Ajouter des segments verticaux/horizontaux; Joints tangents: Prolonger la traverse jusqu'à; Réglage de la hauteur du palier: 0 m; Utiliser le réglage de la hauteur du palier: Non
Données d'identification - Nom du type: Type Bateau 1,50 m
Main courante 1 - Position: Aucune; sets with these values: 2
Traverse haute - Hauteur: 1.2192 m
Name (Garde-corps:Type Bateau 1,50 m:...) | Décalage inférieur (m) | Décalage marche/limon à la française (m) | Niveau de base | Longueur (m)
1234129 | -0.1 | 0 | Niveau: RDC | 34.1961
1234277 | -0.1 | 0 | Niveau: RDC | 8.05934
1234325 | -0.1 | 0 | Niveau: RDC | 6.19853
1234450 | -0.1 | 0 | Niveau: RDC | 22.3634
1234554 | -0.1 | 0 | Niveau: RDC | 19.2
1234602 | -0.1 | 0 | Niveau: RDC | 14.5
1234641 | -0.1 | 0 | Niveau: RDC | 8.4646
1234711 | -0.1 | 0 | Niveau: RDC | 8.71964
1234797 | -0.1 | 0 | Niveau: RDC | 8.5
1234925 | -0.1 | 0 | Niveau: RDC | 10
1257930 | 0 | 0.0254 |  | 4.38375
1257934 | 0 | 0.0254 |  | 7.4619
1258164 | 0 | 0.0254 |  | 4.38375
1258168 | 0 | 0.0254 |  | 7.4619
1262855 | -0.1 | 0 | Niveau: RDC | 23.6531
1263026 | -0.1 | 0 | Niveau: RDC | 15.2378
1263073 | -0.1 | 0 | Niveau: RDC | 32.0586
1283030 | 0 | 0.0254 |  | 4.38375
1318380 | -0.1 | 0 | Niveau: RDC | 1.28872
1318442 | -0.1 | 0 | Niveau: RDC | 1.34
1360661 | 0 | 0.0254 |  | 4.38375

# IfcRoof: Toit de base:Toit - 100 brun gris (12)
Pset_RoofCommon - IsExternal: yes; Reference: Toit - 100 brun gris
Autre - Catégorie: Toits; Famille: Toit de base: Toit - 100 brun gris; Famille et type: Toit de base: Toit - 100 brun gris; ID du type: Toit de base: Toit - 100 brun gris; Type: Toit de base: Toit - 100 brun gris; Nom de la famille: Toit de base
Construction - Coupe en chevron: Coupe verticale; Profondeur du bord de toiture: 0 m; Epaisseur par défaut: 0.05 m
Contraintes - Lié au volume: no; Limite de pièce: yes; Décalage de la coupure: 0 m
Cotes - Epaisseur: 0.05 m
Phase de construction - Phase de création: Nouvelle construction
Données d'identification - Nom du type: Toit - 100 brun gris
Graphismes - Couleur vue détail faible: 4210816; Motif vue détail faible: Acier
Propriétés analytiques - Rugosité: 1; Coefficient d'absorbance: 0.1
Name (Toit de base:Toit - 100 brun gris:...) | In | TotalArea (m2) = Surface (m2) | ProjectedArea (m2) | Chevron ou ferme | Hauteur maximale de l'arrête (m) | Décalage inférieur à partir du niveau (m) | Niveau de base | Inclinaison | Volume (m3) | Group
1258065 | Egout | 81.1386 | 66.4648 | Ferme | 9.19092 | 0.5 | Niveau: Egout | 0.700208 | 4.05693 | Groupe de modèles:Pavillon type:1258082
1258072 | Egout | 12.5815 | 12.1857 | Ferme | 6.44469 | -0.1 | Niveau: Egout | 0.256949 | 0.629075 | Groupe de modèles:Pavillon type:1258082
1258292 | Egout | 81.1386 | 66.4648 | Ferme | 9.19092 | 0.5 | Niveau: Egout | 0.700208 | 4.05693 | Groupe de modèles:Pavillon type:1258309
1258299 | Egout | 12.5815 | 12.1857 | Ferme | 6.44469 | -0.1 | Niveau: Egout | 0.256949 | 0.629075 | Groupe de modèles:Pavillon type:1258309
1260396 | Plan des fondations Maisons 1 et 2 | 1.52504 | 1.47308 |  | 2.58779 | 2.25 | Niveau: Plan des fondations Maisons 1 et 2 | 0.267949 | 0.0762521 | Groupe de modèles:Pavillon type:1258082
1260408 | Plan des fondations Maisons 1 et 2 | 1.52504 | 1.47308 |  | 2.58779 | 2.25 | Niveau: Plan des fondations Maisons 1 et 2 | 0.267949 | 0.0762521 | Groupe de modèles:Pavillon type:1258309
1283145 | Egout | 81.1386 | 66.4648 | Ferme | 9.19092 | 0.5 | Niveau: Egout | 0.700208 | 4.05693
1283152 | Egout | 12.5815 | 12.1857 | Ferme | 6.44469 | -0.1 | Niveau: Egout | 0.256949 | 0.629075
1283167 | Plan des fondations Maisons 1 et 2 | 1.52504 | 1.47308 |  | 2.58779 | 2.25 | Niveau: Plan des fondations Maisons 1 et 2 | 0.267949 | 0.0762521
1360764 | Egout | 81.1386 | 66.4648 | Ferme | 9.19092 | 0.5 | Niveau: Egout | 0.700208 | 4.05693 | Groupe de modèles:Pavillon type:1360776
1360771 | Egout | 12.5815 | 12.1857 | Ferme | 6.44469 | -0.1 | Niveau: Egout | 0.256949 | 0.629075 | Groupe de modèles:Pavillon type:1360776
1360779 | Plan des fondations Maisons 1 et 2 | 1.52504 | 1.47308 |  | 2.58779 | 2.25 | Niveau: Plan des fondations Maisons 1 et 2 | 0.267949 | 0.0762521 | Groupe de modèles:Pavillon type:1360776

# IfcSlab: Base rectangulaire:1.00 x 1.00 x .30 (8)
In: vs
PredefinedType: FLOOR; Material: Béton - Béton coulé sur place
Pset_SlabCommon - IsExternal: no; LoadBearing: yes; Reference: 1.00 x 1.00 x .30
Autre - Catégorie: Fondations; Famille: Base rectangulaire: 1.00 x 1.00 x .30; Famille et type: Base rectangulaire: 1.00 x 1.00 x .30; ID du type: Base rectangulaire: 1.00 x 1.00 x .30; Type: Base rectangulaire: 1.00 x 1.00 x .30; Nom de la famille: Base rectangulaire
Contraintes - Se déplace avec les quadrillages: yes; Décalage: -0.2 m; Hôte: Niveau : vs; Niveau: Niveau: vs
Cotes - Elévation à la base: -1.3 m; Elévation en haut: -1 m; Largeur: 1 m; Longueur: 1 m; Surface: 2 m2; Volume: 0.6 m3; Epaisseur: 0.3 m
Matériaux et finitions - Matériau structurel: Béton - Béton coulé sur place
Phase de construction - Phase de création: Nouvelle construction
Structure - Activer le modèle analytique: yes; Enrobage d'armature - Autres faces: Paramètres de l'enrobage d'armature: Enrobage d'armature 1; Enrobage d'armature - Face inférieure: Paramètres de l'enrobage d'armature: Enrobage d'armature 1; Enrobage d'armature - Face supérieure: Paramètres de l'enrobage d'armature: Enrobage d'armature 1
Données d'identification - Nom du type: 1.00 x 1.00 x .30
Name (Base rectangulaire:1.00 x 1.00 x .30:...) | Group
1333656
1333931 | Groupe de modèles:Pavillon type:1258082
1333937 | Groupe de modèles:Pavillon type:1258309
1343296
1343491 | Groupe de modèles:Pavillon type:1258082
1343496 | Groupe de modèles:Pavillon type:1258309
1360935 | Groupe de modèles:Pavillon type:1360776
1360943 | Groupe de modèles:Pavillon type:1360776

# IfcSlab: Sol:Dalle Béton - 10 cm, Sol:Dalle Béton - 10 cm:1262435
In: Plan des fondations Maisons 1 et 2
PredefinedType: FLOOR; Material: Béton 0.1 m
Pset_SlabCommon - IsExternal: no; LoadBearing: yes; PitchAngle: 0 deg; Reference: Dalle Béton - 10 cm
Autre - Catégorie: Sols; Famille: Sol: Dalle Béton - 10 cm; Famille et type: Sol: Dalle Béton - 10 cm; ID du type: Sol: Dalle Béton - 10 cm; Type: Sol: Dalle Béton - 10 cm; Nom de la famille: Sol
Contraintes - Lié au volume: no; Limite de pièce: yes; Niveau: Niveau: RDC; Décalage par rapport au niveau: -0.05 m
Cotes - Elévation à la base: -0.15 m; Elévation en haut: -0.05 m; Epaisseur: 0.1 m; Périmètre: 71.6684 m; Surface: 198.967 m2; Volume: 19.8967 m3
Phase de construction - Phase de création: Nouvelle construction
Structure - Activer le modèle analytique: no; Structure: no
Construction - Fonction: Intérieur; Epaisseur par défaut: 0.1 m
Données d'identification - Nom du type: Dalle Béton - 10 cm
Graphismes - Couleur vue détail faible: 0
Matériaux et finitions - Matériau structurel: Béton
Propriétés analytiques - Rugosité: 1; Coefficient d'absorbance: 0.1

# IfcSlab: Sol:Dalle Béton - 20 cm (4)
In: Plan des fondations Maisons 1 et 2
PredefinedType: FLOOR; Material: Béton 0.2 m
Pset_SlabCommon - IsExternal: no; LoadBearing: yes; Reference: Dalle Béton - 20 cm
Autre - Catégorie: Sols; Famille: Sol: Dalle Béton - 20 cm; Famille et type: Sol: Dalle Béton - 20 cm; ID du type: Sol: Dalle Béton - 20 cm; Type: Sol: Dalle Béton - 20 cm; Nom de la famille: Sol
Contraintes - Lié au volume: no; Limite de pièce: yes; Décalage par rapport au niveau: 0.02 m
Cotes - Elévation à la base: -0.18 m; Elévation en haut: 0.02 m; Epaisseur: 0.2 m; Périmètre: 36.3465 m
Phase de construction - Phase de création: Nouvelle construction
Structure - Activer le modèle analytique: no; Structure: no
Construction - Fonction: Intérieur; Epaisseur par défaut: 0.2 m
Données d'identification - Nom du type: Dalle Béton - 20 cm
Graphismes - Couleur vue détail faible: 0
Matériaux et finitions - Matériau structurel: Béton
Propriétés analytiques - Rugosité: 1; Coefficient d'absorbance: 0.1
Name (Sol:Dalle Béton - 20 cm:...) | PitchAngle (deg) | Niveau | Surface (m2) | Volume (m3) | Group
1333265 | 0 | Niveau: RDC | 67.2286 | 13.4457
1333589 | 0 | Niveau: Plan des fondations Maisons 1 et 2 | 67.2286 | 13.4457 | Groupe de modèles:Pavillon type:1258082
1333599 | 0 | Niveau: Plan des fondations Maisons 1 et 2 | 67.2286 | 13.4457 | Groupe de modèles:Pavillon type:1258309
1360928 |  | Niveau: Plan des fondations Maisons 1 et 2 | 66.9786 | 13.3957 | Groupe de modèles:Pavillon type:1360776

# IfcSlab: Sol:Dalle Béton - 20 cm + FAUX PLAFOND (4)
In: ETAGE
PredefinedType: FLOOR; Material: Béton 0.2 m, Isolant 0.1 m, Plastique - Blanc 0.02 m
Pset_SlabCommon - IsExternal: no; Reference: Dalle Béton - 20 cm + FAUX PLAFOND; LoadBearing: yes
Autre - Catégorie: Sols; Famille: Sol: Dalle Béton - 20 cm + FAUX PLAFOND; Famille et type: Sol: Dalle Béton - 20 cm + FAUX PLAFOND; ID du type: Sol: Dalle Béton - 20 cm + FAUX PLAFOND; Type: Sol: Dalle Béton - 20 cm + FAUX PLAFOND; Nom de la famille: Sol
Contraintes - Lié au volume: no; Limite de pièce: yes; Décalage par rapport au niveau: 0.02 m; Niveau: Niveau: ETAGE
Cotes - Elévation à la base: 2.52 m; Elévation en haut: 2.84 m; Epaisseur: 0.32 m; Périmètre: 36.3965 m; Surface: 63.5384 m2; Volume: 20.3323 m3
Modification de la forme de dalle - Condition de bord incurvé: 0
Phase de construction - Phase de création: Nouvelle construction
Structure - Activer le modèle analytique: no; Structure: no
Construction - Fonction: Intérieur; Epaisseur par défaut: 0.32 m
Données d'identification - Nom du type: Dalle Béton - 20 cm + FAUX PLAFOND
Graphismes - Couleur vue détail faible: 0
Matériaux et finitions - Matériau structurel: Béton
Propriétés analytiques - Rugosité: 1; Coefficient d'absorbance: 0.1
Name (Sol:Dalle Béton - 20 cm + FAUX PLAFOND:...) | Group
1257996 | Groupe de modèles:Pavillon type:1258082
1258229 | Groupe de modèles:Pavillon type:1258309
1283094
1360718 | Groupe de modèles:Pavillon type:1360776

# IfcSlab: Sol:Dalle Béton butume rouge - 10 cm (9)
In: Plan des fondations Maisons 1 et 2
PredefinedType: FLOOR; Material: Métal 0.1 m
Pset_SlabCommon - IsExternal: no; LoadBearing: yes; Reference: Dalle Béton butume rouge - 10 cm; PitchAngle: 0 deg
Autre - Catégorie: Sols; Famille: Sol: Dalle Béton butume rouge - 10 cm; Famille et type: Sol: Dalle Béton butume rouge - 10 cm; ID du type: Sol: Dalle Béton butume rouge - 10 cm; Type: Sol: Dalle Béton butume rouge - 10 cm; Nom de la famille: Sol
Contraintes - Lié au volume: no; Limite de pièce: yes
Cotes - Epaisseur: 0.1 m
Phase de construction - Phase de création: Nouvelle construction
Structure - Activer le modèle analytique: no; Structure: no
Construction - Fonction: Intérieur; Epaisseur par défaut: 0.1 m
Données d'identification - Nom du type: Dalle Béton butume rouge - 10 cm
Graphismes - Couleur vue détail faible: 8388863
Matériaux et finitions - Matériau structurel: Métal
Propriétés analytiques - Rugosité: 1; Coefficient d'absorbance: 0.1
Name (Sol:Dalle Béton butume rouge - 10 cm:...) | Niveau | Décalage par rapport au niveau (m) = Elévation en haut (m) | Elévation à la base (m) | Périmètre (m) | Surface (m2) | Volume (m3)
1259101 | Niveau: RDC | 0 | -0.1 | 37.6127 | 57.2314 | 5.72314
1259423 | Niveau: RDC | 0 | -0.1 | 32.6377 | 44.1606 | 4.41606
1259624 | Niveau: RDC | 0 | -0.1 | 34.7183 | 49.825 | 4.9825
1259930 | Niveau: RDC | 0 | -0.1 | 45.3095 | 74.8456 | 7.48456
1260664 | Niveau: Plan des fondations Maisons 1 et 2 | -0.05 | -0.15 | 20.7565 | 22.1348 | 2.21348 | Group: Groupe de modèles:Pavillon type:1258082
1260672 | Niveau: Plan des fondations Maisons 1 et 2 | -0.05 | -0.15 | 20.7565 | 22.1348 | 2.21348 | Group: Groupe de modèles:Pavillon type:1258309
1283178 | Niveau: Plan des fondations Maisons 1 et 2 | -0.05 | -0.15 | 20.7565 | 22.1348 | 2.21348
1305559 | Niveau: RDC | -0.05 | -0.15 | 40.3614 | 39.4029 | 3.94029
1360790 | Niveau: Plan des fondations Maisons 1 et 2 | -0.05 | -0.15 | 20.7565 | 22.1348 | 2.21348 | Group: Groupe de modèles:Pavillon type:1360776

# IfcSlab: Sol:LAME DE BAMBOU (279)
In: ETAGE
PredefinedType: FLOOR; Material: PARQUET BAMBOU 0.01 m
Pset_SlabCommon - IsExternal: no; LoadBearing: yes; PitchAngle: 0 deg; Reference: LAME DE BAMBOU
Autre - Catégorie: Sols; Famille: Sol: LAME DE BAMBOU; Famille et type: Sol: LAME DE BAMBOU; ID du type: Sol: LAME DE BAMBOU; Type: Sol: LAME DE BAMBOU; Nom de la famille: Sol
Contraintes - Lié au volume: no; Limite de pièce: yes; Niveau: Niveau: ETAGE; Décalage par rapport au niveau: 0.05 m
Cotes - Elévation à la base: 2.86 m; Elévation en haut: 2.87 m; Epaisseur: 0.01 m
Phase de construction - Phase de création: Nouvelle construction
Structure - Activer le modèle analytique: no; Structure: no
Construction - Fonction: Intérieur; Epaisseur par défaut: 0.01 m
Données d'identification - Nom du type: LAME DE BAMBOU
Graphismes - Couleur vue détail faible: 8388863
Matériaux et finitions - Matériau structurel: PARQUET BAMBOU
Propriétés analytiques - Rugosité: 1; Coefficient d'absorbance: 0.1
Name (Sol:LAME DE BAMBOU:...) | Périmètre (m) | Surface (m2) | Volume (m3)
1376428 | 2.18 | 0.09 | 0.0009
1377877 | 2.18 | 0.09 | 0.0009
1377894 | 2.18 | 0.09 | 0.0009
1377908 | 1.13916 | 0.0431622 | 0.000431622
1377965 | 0.86 | 0.0306 | 0.000306
1378024 | 2.18 | 0.09 | 0.0009
1378038 | 2.18 | 0.09 | 0.0009
1378054 | 2.18 | 0.09 | 0.0009
1378068 | 0.459141 | 0.0125613 | 0.000125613
1378203 | 2.18 | 0.09 | 0.0009
1378210 | 2.18 | 0.09 | 0.0009
1378217 | 2.18 | 0.09 | 0.0009
1378224 | 1.13916 | 0.0431622 | 0.000431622
1378231 | 0.86 | 0.0306 | 0.000306
1378238 | 2.18 | 0.09 | 0.0009
1378245 | 2.18 | 0.09 | 0.0009
1378252 | 2.18 | 0.09 | 0.0009
1378259 | 0.459141 | 0.0125613 | 0.000125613
1378275 | 2.18 | 0.09 | 0.0009
1378282 | 2.18 | 0.09 | 0.0009
1378289 | 2.18 | 0.09 | 0.0009
1378296 | 1.13916 | 0.0431622 | 0.000431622
1378303 | 0.86 | 0.0306 | 0.000306
1378310 | 2.18 | 0.09 | 0.0009
1378317 | 2.18 | 0.09 | 0.0009
1378324 | 2.18 | 0.09 | 0.0009
1378331 | 0.459141 | 0.0125613 | 0.000125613
1378347 | 2.18 | 0.09 | 0.0009
1378354 | 2.18 | 0.09 | 0.0009
1378361 | 2.18 | 0.09 | 0.0009
1378368 | 1.13916 | 0.0431622 | 0.000431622
1378375 | 0.86 | 0.0306 | 0.000306
1378382 | 2.18 | 0.09 | 0.0009
1378389 | 2.18 | 0.09 | 0.0009
1378396 | 2.18 | 0.09 | 0.0009
1378403 | 0.459141 | 0.0125613 | 0.000125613
1378425 | 2.18 | 0.09 | 0.0009
1378432 | 2.18 | 0.09 | 0.0009
1378439 | 2.18 | 0.09 | 0.0009
1378446 | 1.13916 | 0.0431622 | 0.000431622
1378453 | 0.86 | 0.0306 | 0.000306
1378460 | 2.18 | 0.09 | 0.0009
1378467 | 2.18 | 0.09 | 0.0009
1378474 | 2.18 | 0.09 | 0.0009
1378481 | 0.459141 | 0.0125613 | 0.000125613
1378488 | 2.18 | 0.09 | 0.0009
1378495 | 2.18 | 0.09 | 0.0009
1378502 | 2.18 | 0.09 | 0.0009
1378509 | 1.13916 | 0.0431622 | 0.000431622
1378516 | 0.86 | 0.0306 | 0.000306
1378523 | 2.18 | 0.09 | 0.0009
1378530 | 2.18 | 0.09 | 0.0009
1378537 | 2.18 | 0.09 | 0.0009
1378544 | 0.459141 | 0.0125613 | 0.000125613
1378551 | 2.18 | 0.09 | 0.0009
1378558 | 2.18 | 0.09 | 0.0009
1378565 | 2.18 | 0.09 | 0.0009
1378572 | 1.13916 | 0.0431622 | 0.000431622
1378579 | 0.86 | 0.0306 | 0.000306
1378586 | 2.18 | 0.09 | 0.0009
1378593 | 2.18 | 0.09 | 0.0009
1378600 | 2.18 | 0.09 | 0.0009
1378607 | 0.459141 | 0.0125613 | 0.000125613
1378614 | 2.18 | 0.09 | 0.0009
1378621 | 2.18 | 0.09 | 0.0009
1378628 | 2.18 | 0.09 | 0.0009
1378635 | 1.13916 | 0.0431622 | 0.000431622
1378642 | 0.86 | 0.0306 | 0.000306
1378649 | 2.18 | 0.09 | 0.0009
1378656 | 2.18 | 0.09 | 0.0009
1378663 | 2.18 | 0.09 | 0.0009
1378670 | 0.459141 | 0.0125613 | 0.000125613
1378692 | 2.18 | 0.09 | 0.0009
1378699 | 2.18 | 0.09 | 0.0009
1378706 | 2.18 | 0.09 | 0.0009
1378713 | 1.13916 | 0.0431622 | 0.000431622
1378720 | 0.86 | 0.0306 | 0.000306
1378727 | 2.18 | 0.09 | 0.0009
1378734 | 2.18 | 0.09 | 0.0009
1378741 | 2.18 | 0.09 | 0.0009
1378748 | 0.459141 | 0.0125613 | 0.000125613
1378755 | 2.18 | 0.09 | 0.0009
1378762 | 2.18 | 0.09 | 0.0009
1378769 | 2.18 | 0.09 | 0.0009
1378776 | 1.13916 | 0.0431622 | 0.000431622
1378783 | 0.86 | 0.0306 | 0.000306
1378790 | 2.18 | 0.09 | 0.0009
1378797 | 2.18 | 0.09 | 0.0009
1378804 | 2.18 | 0.09 | 0.0009
1378811 | 0.459141 | 0.0125613 | 0.000125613
1378818 | 2.18 | 0.09 | 0.0009
1378825 | 2.18 | 0.09 | 0.0009
1378832 | 2.18 | 0.09 | 0.0009
1378839 | 1.13916 | 0.0431622 | 0.000431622
1378846 | 0.86 | 0.0306 | 0.000306
1378853 | 2.18 | 0.09 | 0.0009
1378860 | 2.18 | 0.09 | 0.0009
1378867 | 2.18 | 0.09 | 0.0009
1378874 | 0.459141 | 0.0125613 | 0.000125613
1378881 | 2.18 | 0.09 | 0.0009
1378888 | 2.18 | 0.09 | 0.0009
1378895 | 2.18 | 0.09 | 0.0009
1378902 | 1.13916 | 0.0431622 | 0.000431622
1378909 | 0.86 | 0.0306 | 0.000306
1378916 | 2.18 | 0.09 | 0.0009
1378923 | 2.18 | 0.09 | 0.0009
1378930 | 2.18 | 0.09 | 0.0009
1378937 | 0.459141 | 0.0125613 | 0.000125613
1378959 | 2.18 | 0.09 | 0.0009
1378966 | 2.18 | 0.09 | 0.0009
1378973 | 2.18 | 0.09 | 0.0009
1378980 | 1.13916 | 0.0431622 | 0.000431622
1378987 | 0.86 | 0.0306 | 0.000306
1378994 | 2.18 | 0.09 | 0.0009
1379001 | 2.18 | 0.09 | 0.0009
1379008 | 2.18 | 0.09 | 0.0009
1379015 | 0.459141 | 0.0125613 | 0.000125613
1379022 | 2.18 | 0.09 | 0.0009
1379029 | 2.18 | 0.09 | 0.0009
1379036 | 2.18 | 0.09 | 0.0009
1379043 | 1.13916 | 0.0431622 | 0.000431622
1379050 | 0.86 | 0.0306 | 0.000306
1379057 | 2.18 | 0.09 | 0.0009
1379064 | 2.18 | 0.09 | 0.0009
1379071 | 2.18 | 0.09 | 0.0009
1379085 | 2.18 | 0.09 | 0.0009
1379092 | 2.18 | 0.09 | 0.0009
1379099 | 2.18 | 0.09 | 0.0009
1379113 | 0.86 | 0.0306 | 0.000306
1379120 | 2.18 | 0.09 | 0.0009
1379127 | 2.18 | 0.09 | 0.0009
1379134 | 2.18 | 0.09 | 0.0009
1379148 | 2.18 | 0.09 | 0.0009
1379155 | 2.18 | 0.09 | 0.0009
1379162 | 2.18 | 0.09 | 0.0009
1379176 | 0.86 | 0.0306 | 0.000306
1379183 | 2.18 | 0.09 | 0.0009
1379190 | 2.18 | 0.09 | 0.0009
1379197 | 2.18 | 0.09 | 0.0009
1379283 | 2.18 | 0.09 | 0.0009
1379297 | 2.18 | 0.09 | 0.0009
1379313 | 0.22 | 0.0018 | 0.000018
1379397 | 2.18 | 0.09 | 0.0009
1379411 | 2.18 | 0.09 | 0.0009
1379425 | 0.9 | 0.0324 | 0.000324
1379473 | 2.18 | 0.09 | 0.0009
1379480 | 2.18 | 0.09 | 0.0009
1379487 | 2.18 | 0.09 | 0.0009
1379503 | 2.18 | 0.09 | 0.0009
1379510 | 2.18 | 0.09 | 0.0009
1379517 | 0.97 | 0.03555 | 0.0003555
1379532 | 2.18 | 0.09 | 0.0009
1379539 | 2.18 | 0.09 | 0.0009
1379546 | 0.9 | 0.0324 | 0.000324
1379561 | 2.18 | 0.09 | 0.0009
1379568 | 2.18 | 0.09 | 0.0009
1379575 | 0.22 | 0.0018 | 0.000018
1379683 | 2.18 | 0.09 | 0.0009
1379697 | 2.22 | 0.0918 | 0.000918
1379720 | 0.86 | 0.0306 | 0.000306
1379743 | 2.18 | 0.09 | 0.0009
1379750 | 2.18 | 0.09 | 0.0009
1379757 | 2.18 | 0.09 | 0.0009
1379771 | 2.18 | 0.09 | 0.0009
1379778 | 2.18 | 0.09 | 0.0009
1379785 | 0.29 | 0.00495 | 0.0000495
1380610 | 2.18 | 0.09 | 0.0009
1380617 | 2.18 | 0.09 | 0.0009
1380624 | 0.97 | 0.03555 | 0.0003555
1380702 | 0.86 | 0.0306 | 0.000306
1380709 | 2.18 | 0.09 | 0.0009
1380716 | 2.18 | 0.09 | 0.0009
1380723 | 0.29 | 0.00495 | 0.0000495
1380762 | 2.18 | 0.09 | 0.0009
1380769 | 2.18 | 0.09 | 0.0009
1380776 | 0.97 | 0.03555 | 0.0003555
1380832 | 0.86 | 0.0306 | 0.000306
1380839 | 2.18 | 0.09 | 0.0009
1380846 | 2.18 | 0.09 | 0.0009
1380853 | 0.29 | 0.00495 | 0.0000495
1380860 | 2.18 | 0.09 | 0.0009
1380867 | 2.18 | 0.09 | 0.0009
1380874 | 0.97 | 0.03555 | 0.0003555
1380892 | 0.86 | 0.0306 | 0.000306
1380899 | 2.18 | 0.09 | 0.0009
1380906 | 2.18 | 0.09 | 0.0009
1380913 | 0.29 | 0.00495 | 0.0000495
1380920 | 2.18 | 0.09 | 0.0009
1380927 | 2.18 | 0.09 | 0.0009
1380934 | 0.97 | 0.03555 | 0.0003555
1380970 | 0.86 | 0.0306 | 0.000306
1380977 | 2.18 | 0.09 | 0.0009
1380984 | 2.18 | 0.09 | 0.0009
1380991 | 2.18 | 0.09 | 0.0009
1380998 | 0.459141 | 0.0125613 | 0.000125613
1381050 | 1.2 | 0.0459 | 0.000459
1381057 | 2.18 | 0.09 | 0.0009
1381064 | 0.9 | 0.0324 | 0.000324
1381126 | 1.74 | 0.0702 | 0.000702
1381133 | 2.18 | 0.09 | 0.0009
1381140 | 0.22 | 0.0018 | 0.000018
1381220 | 1.2 | 0.0459 | 0.000459
1381227 | 2.18 | 0.09 | 0.0009
1381234 | 0.9 | 0.0324 | 0.000324
1381265 | 1.74 | 0.0702 | 0.000702
1381272 | 2.18 | 0.09 | 0.0009
1381279 | 0.22 | 0.0018 | 0.000018
1381286 | 1.2 | 0.0459 | 0.000459
1381293 | 2.18 | 0.09 | 0.0009
1381300 | 0.9 | 0.0324 | 0.000324
1381318 | 1.74 | 0.0702 | 0.000702
1381325 | 2.18 | 0.09 | 0.0009
1381332 | 0.22 | 0.0018 | 0.000018
1381339 | 1.2 | 0.0459 | 0.000459
1381346 | 2.18 | 0.09 | 0.0009
1381353 | 0.9 | 0.0324 | 0.000324
1381375 | 1.74 | 0.0702 | 0.000702
1381382 | 2.18 | 0.09 | 0.0009
1381389 | 0.22 | 0.0018 | 0.000018
1381396 | 1.2 | 0.0459 | 0.000459
1381403 | 2.18 | 0.09 | 0.0009
1381410 | 0.9 | 0.0324 | 0.000324
1381432 | 1.74 | 0.0702 | 0.000702
1381439 | 2.18 | 0.09 | 0.0009
1381446 | 0.22 | 0.0018 | 0.000018
1381453 | 1.2 | 0.0459 | 0.000459
1381460 | 2.18 | 0.09 | 0.0009
1381467 | 0.9 | 0.0324 | 0.000324
1381489 | 1.74 | 0.0702 | 0.000702
1381496 | 2.18 | 0.09 | 0.0009
1381503 | 0.22 | 0.0018 | 0.000018
1381510 | 1.2 | 0.0459 | 0.000459
1381517 | 2.18 | 0.09 | 0.0009
1381524 | 0.9 | 0.0324 | 0.000324
1381542 | 1.74 | 0.0702 | 0.000702
1381549 | 2.18 | 0.09 | 0.0009
1381556 | 0.22 | 0.0018 | 0.000018
1381563 | 1.2 | 0.0459 | 0.000459
1381570 | 2.18 | 0.09 | 0.0009
1381577 | 0.9 | 0.0324 | 0.000324
1381597 | 1.74 | 0.0702 | 0.000702
1381604 | 2.18 | 0.09 | 0.0009
1381611 | 0.22 | 0.0018 | 0.000018
1381618 | 1.2 | 0.0459 | 0.000459
1381625 | 2.18 | 0.09 | 0.0009
1381632 | 0.9 | 0.0324 | 0.000324
1381650 | 1.74 | 0.0702 | 0.000702
1381657 | 2.18 | 0.09 | 0.0009
1381664 | 0.22 | 0.0018 | 0.000018
1381671 | 1.2 | 0.0459 | 0.000459
1381678 | 2.18 | 0.09 | 0.0009
1381685 | 0.9 | 0.0324 | 0.000324
1381705 | 1.74 | 0.0702 | 0.000702
1381712 | 2.18 | 0.09 | 0.0009
1381719 | 0.22 | 0.0018 | 0.000018
1381726 | 1.2 | 0.0459 | 0.000459
1381733 | 2.18 | 0.09 | 0.0009
1381740 | 0.9 | 0.0324 | 0.000324
1381762 | 1.74 | 0.0702 | 0.000702
1381769 | 2.18 | 0.09 | 0.0009
1381776 | 0.22 | 0.0018 | 0.000018
1381783 | 1.2 | 0.0459 | 0.000459
1381790 | 2.18 | 0.09 | 0.0009
1381797 | 0.9 | 0.0324 | 0.000324
1381817 | 1.74 | 0.0702 | 0.000702
1381824 | 2.18 | 0.09 | 0.0009
1381831 | 0.22 | 0.0018 | 0.000018
1381838 | 1.2 | 0.0459 | 0.000459
1381845 | 2.18 | 0.09 | 0.0009
1381852 | 0.9 | 0.0324 | 0.000324
1381874 | 1.74 | 0.0702 | 0.000702
1381881 | 2.18 | 0.09 | 0.0009
1381888 | 0.22 | 0.0018 | 0.000018
1381895 | 1.2 | 0.0459 | 0.000459
1381902 | 2.18 | 0.09 | 0.0009
1381909 | 0.9 | 0.0324 | 0.000324
1381927 | 1.74 | 0.0702 | 0.000702
1381934 | 2.18 | 0.09 | 0.0009
1381941 | 0.22 | 0.0018 | 0.000018

# IfcSlab: Toit de base:Toit - 100 brun gris (16)
PredefinedType: ROOF; Material: gris 0.05 m
Pset_SlabCommon - IsExternal: yes; LoadBearing: yes; Reference: Toit - 100 brun gris
Name (Toit de base:Toit - 100 brun gris:...) | In | PitchAngle (deg) | Group
2 x 1258065 | Egout | 35 | Groupe de modèles:Pavillon type:1258082
1258072 | Egout | 14.4103 | Groupe de modèles:Pavillon type:1258082
2 x 1258292 | Egout | 35 | Groupe de modèles:Pavillon type:1258309
1258299 | Egout | 14.4103 | Groupe de modèles:Pavillon type:1258309
1260396 | Plan des fondations Maisons 1 et 2 | 15 | Groupe de modèles:Pavillon type:1258082
1260408 | Plan des fondations Maisons 1 et 2 | 15 | Groupe de modèles:Pavillon type:1258309
2 x 1283145 | Egout | 35
1283152 | Egout | 14.4103
1283167 | Plan des fondations Maisons 1 et 2 | 15
2 x 1360764 | Egout | 35 | Groupe de modèles:Pavillon type:1360776
1360771 | Egout | 14.4103 | Groupe de modèles:Pavillon type:1360776
1360779 | Plan des fondations Maisons 1 et 2 | 15 | Groupe de modèles:Pavillon type:1360776

# IfcStair: Escalier coulé sur place:Monobloc:972371 (4)
In: Plan des fondations Maisons 1 et 2
Pset_StairCommon - Reference: Monobloc; IsExternal: no; NumberOfRiser: 17; NumberOfTreads: 16; RiserHeight: 0.177647 m; TreadLength: 0.274706 m
Autre - Catégorie: Escalier; Famille: Escalier coulé sur place: Monobloc; Famille et type: Escalier coulé sur place: Monobloc; ID du type: Escalier coulé sur place: Monobloc; Type: Escalier coulé sur place: Monobloc; Nom de la famille: Escalier coulé sur place
Contraintes - Décalage inférieur: 0 m; Niveau de base: Niveau: Plan des fondations Maisons 1 et 2; Décalage supérieur: 0.2 m; Hauteur d'escalier souhaitée: 3.02 m; Niveau supérieur: Niveau: ETAGE
Cotes - Hauteur actuelle de la contremarche: 0.177647 m; Nombre de contremarches souhaité: 17; Nombre réel de contremarches: 17; Numéro initial de marche/contremarche: 1; Profondeur actuelle du giron: 0.274706 m
Phase de construction - Phase de création: Nouvelle construction
Structure - Enrobage d'armature: Paramètres de l'enrobage d'armature: Enrobage d'armature 1
Construction - Fonction: Intérieur; Type de palier: Palier monobloc: Epaisseur 150 mm; Type de volée: Volée monobloc: Nez de marche 5 mm
Données d'identification - Nom du type: Monobloc
Graphismes - Type de symbole de coupe: Symbole de coupure d'escalier: Zig-zag simple
Règles de calcul - Hauteur maximum de la contremarche: 0.19 m; Largeur de volée minimale: 1 m; Profondeur de marche minimale: 0.23 m
Supports - Décalage latéral droit: 0 m; Décalage latéral gauche: 0 m; Nombre de supports intermédiaires: 0; Support droit: Aucun; Support gauche: Aucun; Support intermédiaire: no
Name (Escalier coulé sur place:Escalier:...) | Group
1257909 | Groupe de modèles:Pavillon type:1258082
1258143 | Groupe de modèles:Pavillon type:1258309
1283009
1360640 | Groupe de modèles:Pavillon type:1360776

# IfcStair: Escalier:Monobloc 2:150833, Escalier:Monobloc 2:515021
In: Plan des fondations Maisons 1 et 2
Pset_StairCommon - IsExternal: no; Reference: Monobloc 2; NumberOfRiser: 15; NumberOfTreads: 15; RiserHeight: 0.18 m; TreadLength: 0.3 m
Autre - Catégorie: Escalier; Famille: Escalier: Monobloc 2; Famille et type: Escalier: Monobloc 2; ID du type: Escalier: Monobloc 2; Type: Escalier: Monobloc 2; Nom de la famille: Escalier
Contraintes - Décalage inférieur: 0 m; Niveau de base: Niveau: Plan des fondations Maisons 1 et 2; Décalage supérieur: 0 m; Niveau supérieur: Niveau: Etage
Cotes - Hauteur actuelle de la contremarche: 0.18 m; Largeur: 1 m; Nombre de contremarches souhaité: 15; Nombre réel de contremarches: 15; Profondeur actuelle du giron: 0.3 m
Graphismes - Afficher la flèche Haut dans toutes les vues: no; Flèche Bas: no; Flèche Haut: yes; Libellé Bas: no; Libellé Haut: no; Texte Bas: BAS; Texte Haut: HAUT; Symbole de coupure en plan: yes; Police de texte: Arial; Taille du texte: 0.0082021
Phase de construction - Phase de création: Nouvelle construction
Structure - Enrobage d'armature: Paramètres de l'enrobage d'armature: Enrobage d'armature 1
Construction - Décalage du niveau de départ: 0 m; Dessous de paillasse: Lissé; Escalier monobloc: yes; Fonction: Intérieur; Raccord marche palière: 0.076 m
Contremarches - Connexion Marche Contremarche: Marche dessous la contremarche; Débuter avec contremarche: yes; Epaisseur de la contremarche: 0 m; Finir avec contremarche: no; Type de contremarche: Droit
Données d'identification - Nom du type: Monobloc 2
Limons à la française - Ajuster les limons à la française en haut: Correspondance au niveau; Limon à la française droit: Aucun(e); Limon à la française gauche: Aucun(e); Limons à la française centraux: 0; Décalage du limon à la française apparent: 0.05 m; Epaisseur des limons à la française: 0.05 m; Hauteur des limons à la française: 0.27 m; Hauteur du limon à crémaillère: 0.08 m; Hauteur palier intermédiaire: 0.15 m
Marches - Appliquer un nez de marche: Devant seulement; Epaisseur de la marche: 0 m; Longueur du nez de marche: 0.005 m
Matériaux et finitions - Matériau du limon à la française: Bois - Limons
Règles de calcul - Hauteur maximum de la contremarche: 0.19 m; Profondeur de marche minimale: 0.3 m

# IfcStair: Escalier:Monobloc:28673 (22)
In: Plan des fondations Maisons 1 et 2
Pset_StairCommon - Reference: Monobloc; IsExternal: no
Autre - Catégorie: Escalier; Famille: Escalier: Monobloc; Famille et type: Escalier: Monobloc; ID du type: Escalier: Monobloc; Type: Escalier: Monobloc; Nom de la famille: Escalier
Contraintes - Décalage inférieur: 0 m; Niveau de base: Niveau: Plan des fondations Maisons 1 et 2
Graphismes - Afficher la flèche Haut dans toutes les vues: no; Flèche Bas: no; Flèche Haut: yes; Libellé Bas: no; Libellé Haut: no; Texte Bas: BAS; Texte Haut: HAUT; Police de texte: Arial; Symbole de coupure en plan: yes; Taille du texte: 0.0082021
Phase de construction - Phase de création: Nouvelle construction
Structure - Enrobage d'armature: Paramètres de l'enrobage d'armature: Enrobage d'armature 1
Construction - Décalage du niveau de départ: 0 m; Dessous de paillasse: Lissé; Escalier monobloc: yes; Fonction: Intérieur; Raccord marche palière: 0.076 m
Contremarches - Connexion Marche Contremarche: Marche dessous la contremarche; Débuter avec contremarche: yes; Epaisseur de la contremarche: 0 m; Finir avec contremarche: no; Type de contremarche: Aucun(e)
Données d'identification - Nom du type: Monobloc
Limons à la française - Ajuster les limons à la française en haut: Correspondance au niveau; Décalage du limon à la française apparent: 0.05 m; Epaisseur des limons à la française: 0.05 m; Hauteur des limons à la française: 0.27 m; Hauteur du limon à crémaillère: 0.08 m; Hauteur palier intermédiaire: 0.15 m; Limon à la française droit: Aucun(e); Limon à la française gauche: Aucun(e); Limons à la française centraux: 0
Marches - Appliquer un nez de marche: Devant seulement; Epaisseur de la marche: 0 m; Longueur du nez de marche: 0.005 m
Matériaux et finitions - Matériau du limon à la française: Bois - Limons
Règles de calcul - Hauteur maximum de la contremarche: 0.19 m; Profondeur de marche minimale: 0.23 m
Name (Escalier:Monobloc:...) | NumberOfRiser = NumberOfTreads = Nombre réel de contremarches | RiserHeight (m) = Hauteur actuelle de la contremarche (m) | TreadLength (m) = Profondeur actuelle du giron (m) | Décalage supérieur (m) | Niveau supérieur | Largeur (m) | Nombre de contremarches souhaité
78219 | 15 | 0.173333 | 0.283333 | 2.6 | Niveau: Plan des fondations Maisons 1 et 2 | 1 | 15
78348 | 15 | 0.173333 | 0.283333 | 2.6 | Niveau: Plan des fondations Maisons 1 et 2 | 1 | 15
277315 | 17 | 0.158824 | 0.312353 | 0 | Niveau: Etage | 0.9 | 17
277472 | 17 | 0.158824 | 0.312353 | 0 | Niveau: Etage | 0.9 | 17
277700 | 17 | 0.158824 | 0.312353 | 0 | Niveau: Etage | 0.9 | 17
277873 | 17 | 0.158824 | 0.312353 | 0 | Niveau: Etage | 0.9 | 17
342772 | 15 | 0.18 | 0.27 | 0 | Niveau: Etage | 0.8 | 15
342952 | 15 | 0.18 | 0.27 | 0 | Niveau: Etage | 0.8 | 15
343084 | 15 | 0.18 | 0.27 | 0 | Niveau: Etage | 0.8 | 15
343204 | 15 | 0.18 | 0.27 | 0 | Niveau: Etage | 0.8 | 15
352512 | 15 | 0.18 | 0.27 | 0 | Niveau: Etage | 0.8 | 15
353029 | 15 | 0.18 | 0.27 | 0 | Niveau: Etage | 0.8 | 15
368055 | 15 | 0.18 | 0.27 | 0 | Niveau: Etage | 0.8 | 15
368180 | 15 | 0.18 | 0.27 | 0 | Niveau: Etage | 0.8 | 15
368300 | 14 | 0.18 | 0.27 | 0 | Niveau: Etage | 0.8 | 15
369629 | 15 | 0.18 | 0.27 | 0 | Niveau: Etage | 0.8 | 15
373361 | 15 | 0.18 | 0.27 | 0 | Niveau: Etage | 0.8 | 15
373488 | 15 | 0.18 | 0.27 | 0 | Niveau: Etage | 0.8 | 15
376794 | 15 | 0.18 | 0.27 | 0 | Niveau: Etage | 0.8 | 15
384406 | 15 | 0.18 | 0.27 | 0 | Niveau: Etage | 0.8 | 15
384573 | 14 | 0.18 | 0.27 | 0 | Niveau: Etage | 0.8 | 15
384807 | 15 | 0.18 | 0.27 | 0 | Niveau: Etage | 0.8 | 15

# IfcStairFlight: Escalier coulé sur place:Monobloc:972371 (4)
In: Plan des fondations Maisons 1 et 2
NumberOfRiser: 17; NumberOfTreads: 16; RiserHeight: 0.582832 m; TreadLength: 0.901266 m
Pset_StairFlightCommon - Reference: Nez de marche 5 mm; NumberOfRiser: 17; NumberOfTreads: 16; RiserHeight: 0.177647 m; TreadLength: 0.274706 m; TreadLengthAtOffset: 0.274706 m; NosingLength: 0.005 m
Autre - Catégorie: Volées; Famille: Volée monobloc: Nez de marche 5 mm; Famille et type: Volée monobloc: Nez de marche 5 mm; ID du type: Volée monobloc: Nez de marche 5 mm; Type: Volée monobloc: Nez de marche 5 mm; Nom de la famille: Volée monobloc
Construction - Débuter avec contremarche: yes; Etendre la base de contremarche inférieure: 0 m; Finir avec contremarche: yes; Paillasse: Lissée; Profondeur structurelle: 0.08 m
Contraintes - Hauteur de base relative: 0 m; Hauteur de la volée: 3.02 m; Hauteur maximale relative: 3.02 m
Cotes - Hauteur réelle des contremarches: 0.177647 m; Nombre réel de contremarches: 17; Nombre réel de marches: 16
Phase de construction - Phase de création: Nouvelle construction
Contremarches - Epaisseur de la contremarche: 0 m; Connexion contremarche à marche: Marche dessous la contremarche; Contremarche: no; Inclinée: no
Données d'identification - Nom du type: Nez de marche 5 mm
Marches - Appliquer un nez de marche: Devant seulement; Epaisseur de la marche: 0 m; Longueur du nez de marche: 0.005 m; Marche: no
Name (Escalier coulé sur place:Escalier:...) | Group
1257909 Run 1 | Groupe de modèles:Pavillon type:1258082
1258143 Run 1 | Groupe de modèles:Pavillon type:1258309
1283009 Run 1
1360640 Run 1 | Groupe de modèles:Pavillon type:1360776

# IfcWall: Mur de base:peinture biorox 1, Mur de base:peinture biorox 1:1371419
In: ETAGE
Type - PredefinedType: STANDARD; Material: biorox 1 0.002 m
Type - Autre - Catégorie: Murs; Nom de la famille: Mur de base
Type - Construction - Fonction: Extérieur; Retournement aux extrémités: Aucun(e); Retournement aux insertions: Les deux; Largeur: 0.002 m
Type - Données d'identification - Commentaires du type: Ext. Parpaing 20 + Isolant 10; Nom du type: peinture biorox 1
Type - Graphismes - Couleur vue détail faible: 0
Type - Propriétés analytiques - Rugosité: 1; Coefficient d'absorbance: 0.1
Autre - Famille: Mur de base: peinture biorox 1; Famille et type: Mur de base: peinture biorox 1; ID du type: Mur de base: peinture biorox 1; Type: Mur de base: peinture biorox 1
Contraintes - Décalage supérieur: 0 m; Extension inférieure: 0 m; Extension supérieure: 0 m; Lié au volume: no; Ligne de justification: Nu fini: Extérieur; Limite de pièce: yes; Partie inférieure attachée: no; Partie supérieure attachée: no; Contrainte inférieure: Niveau: ETAGE; Décalage inférieur: 0.04 m; Hauteur non contrainte: 2.5 m
Cotes - Longueur: 1.49716 m; Surface: 0.29 m2; Volume: 0.00058 m3
Phase de construction - Phase de création: Nouvelle construction
Structure - Activer le modèle analytique: no; Structure: no; Utilisation structurelle: Non porteur
Pset_WallCommon - LoadBearing: no; ExtendToStructure: no; IsExternal: yes; Reference: peinture biorox 1

# IfcWallStandardCase: Mur de base:Ext. Parpaing 10 (8)
In: vs
Type - PredefinedType: STANDARD; Material: Parpaing 0.1 m
Type - Autre - Catégorie: Murs; Nom de la famille: Mur de base
Type - Construction - Fonction: Extérieur; Retournement aux extrémités: Aucun(e); Retournement aux insertions: Les deux; Largeur: 0.1 m
Type - Données d'identification - Commentaires du type: Ext. Parpaing 20 + Isolant 10; Nom du type: Ext. Parpaing 10
Type - Graphismes - Couleur vue détail faible: 0
Type - Matériaux et finitions - Matériau structurel: Parpaing
Type - Propriétés analytiques - Rugosité: 1; Coefficient d'absorbance: 0.1
Autre - Famille: Mur de base: Ext. Parpaing 10; Famille et type: Mur de base: Ext. Parpaing 10; ID du type: Mur de base: Ext. Parpaing 10; Type: Mur de base: Ext. Parpaing 10
Contraintes - Décalage supérieur: 0 m; Extension inférieure: 0 m; Extension supérieure: 0 m; Lié au volume: no; Ligne de justification: Nu fini: Extérieur; Limite de pièce: yes; Partie inférieure attachée: no; Partie supérieure attachée: no; Contrainte inférieure: Niveau: vs; Décalage inférieur: -0.2 m; Hauteur non contrainte: 1 m
Phase de construction - Phase de création: Nouvelle construction
Structure - Activer le modèle analytique: no; Structure: no; Utilisation structurelle: Non porteur
Pset_WallCommon - LoadBearing: no; ExtendToStructure: no; IsExternal: yes; Reference: Ext. Parpaing 10
Name (Mur de base:Ext. Parpaing 10:...) | Contrainte supérieure | Longueur (m) | Surface (m2) | Volume (m3) | Group
1330088 | Niveau: RDC | 5.29619 | 5.19619 | 0.519619
1330091 | Niveau: RDC | 6.00381 | 6.08581 | 0.608581
1332169 | Niveau: Plan des fondations Maisons 1 et 2 | 5.29619 | 5.19619 | 0.519619 | Groupe de modèles:Pavillon type:1258082
1332170 | Niveau: Plan des fondations Maisons 1 et 2 | 6.00381 | 6.10381 | 0.610381 | Groupe de modèles:Pavillon type:1258082
1332182 | Niveau: Plan des fondations Maisons 1 et 2 | 5.29619 | 5.19619 | 0.519619 | Groupe de modèles:Pavillon type:1258309
1332183 | Niveau: Plan des fondations Maisons 1 et 2 | 6.00381 | 6.10381 | 0.610381 | Groupe de modèles:Pavillon type:1258309
1360903 | Niveau: Plan des fondations Maisons 1 et 2 | 5.29619 | 5.19619 | 0.519619 | Groupe de modèles:Pavillon type:1360776
1360904 | Niveau: Plan des fondations Maisons 1 et 2 | 6.00381 | 5.92181 | 0.592181 | Groupe de modèles:Pavillon type:1360776

# IfcWallStandardCase: Mur de base:Ext. Parpaing 10 + 2 x 1.5 2 (4)
In: Plan des fondations Maisons 1 et 2
Type - PredefinedType: STANDARD; Material: Enduit blanc cassé2 0.015 m, Parpaing 0.1 m, Enduit blanc cassé2 0.015 m
Type - Autre - Catégorie: Murs; Nom de la famille: Mur de base
Type - Construction - Fonction: Extérieur; Retournement aux extrémités: Aucun(e); Retournement aux insertions: Les deux; Largeur: 0.13 m
Type - Données d'identification - Commentaires du type: Ext. Parpaing 20 + Isolant 10; Nom du type: Ext. Parpaing 10 + 2 x 1.5 2
Type - Graphismes - Couleur vue détail faible: 0
Type - Matériaux et finitions - Matériau structurel: Parpaing
Type - Propriétés analytiques - Rugosité: 1; Coefficient d'absorbance: 0.1
Autre - Famille: Mur de base: Ext. Parpaing 10 + 2 x 1.5 2; Famille et type: Mur de base: Ext. Parpaing 10 + 2 x 1.5 2; ID du type: Mur de base: Ext. Parpaing 10 + 2 x 1.5 2; Type: Mur de base: Ext. Parpaing 10 + 2 x 1.5 2
Contraintes - Décalage inférieur: 0 m; Décalage supérieur: 0 m; Contrainte supérieure: Niveau: ETAGE; Extension inférieure: 0 m; Extension supérieure: 0 m; Lié au volume: no; Ligne de justification: Nu fini: Extérieur; Limite de pièce: yes; Partie inférieure attachée: no; Partie supérieure attachée: no; Hauteur non contrainte: 2.82 m
Cotes - Longueur: 5.5 m
Phase de construction - Phase de création: Nouvelle construction
Structure - Activer le modèle analytique: no; Structure: no; Utilisation structurelle: Non porteur
Pset_WallCommon - LoadBearing: no; ExtendToStructure: no; IsExternal: yes; Reference: Ext. Parpaing 10 + 2 x 1.5 2
Name (Mur de base:Ext. Parpaing 10 + 2 x 1.5 2:...) | Contrainte inférieure | Surface (m2) | Volume (m3) | Group
1257903 | Niveau: Plan des fondations Maisons 1 et 2 | 15.7074 | 2.04196 | Groupe de modèles:Pavillon type:1258082
1258137 | Niveau: Plan des fondations Maisons 1 et 2 | 15.7074 | 2.04196 | Groupe de modèles:Pavillon type:1258309
1283003 | Niveau: RDC | 15.8484 | 2.06029
1360634 | Niveau: Plan des fondations Maisons 1 et 2 | 15.0306 | 1.95398 | Groupe de modèles:Pavillon type:1360776

# IfcWallStandardCase: Mur de base:Ext. Parpaing 10 + Isolant 10 enduit blanc cassé (4)
In: Plan des fondations Maisons 1 et 2
Type - PredefinedType: STANDARD; Material: Enduit blanc cassé2 0.02 m, Parpaing 0.1 m, Isolant 0.1 m
Type - Autre - Catégorie: Murs; Nom de la famille: Mur de base
Type - Construction - Fonction: Extérieur; Retournement aux extrémités: Aucun(e); Retournement aux insertions: Les deux; Largeur: 0.22 m
Type - Données d'identification - Commentaires du type: Ext. Parpaing 20 + Isolant 10; Nom du type: Ext. Parpaing 10 + Isolant 10 enduit blanc cassé
Type - Graphismes - Couleur vue détail faible: 0
Type - Matériaux et finitions - Matériau structurel: Parpaing
Type - Propriétés analytiques - Rugosité: 1; Coefficient d'absorbance: 0.1
Autre - Famille: Mur de base: Ext. Parpaing 10 + Isolant 10 enduit blanc cassé; Famille et type: Mur de base: Ext. Parpaing 10 + Isolant 10 enduit blanc cassé; ID du type: Mur de base: Ext. Parpaing 10 + Isolant 10 enduit blanc cassé; Type: Mur de base: Ext. Parpaing 10 + Isolant 10 enduit blanc cassé
Contraintes - Décalage inférieur: 0 m; Décalage supérieur: 0 m; Contrainte supérieure: Niveau: ETAGE; Extension inférieure: 0 m; Extension supérieure: 0 m; Lié au volume: no; Ligne de justification: Nu fini: Extérieur; Limite de pièce: yes; Partie inférieure attachée: no; Partie supérieure attachée: no; Hauteur non contrainte: 2.82 m
Cotes - Longueur: 5.76 m
Phase de construction - Phase de création: Nouvelle construction
Structure - Activer le modèle analytique: no; Structure: no; Utilisation structurelle: Non porteur
Pset_WallCommon - LoadBearing: no; ExtendToStructure: no; IsExternal: yes; Reference: Ext. Parpaing 10 + Isolant 10 enduit blanc cassé
Name (Mur de base:Ext. Parpaing 10 + Isolant 10 enduit blanc cassé:...) | Contrainte inférieure | Surface (m2) | Volume (m3) | Group
1257899 | Niveau: Plan des fondations Maisons 1 et 2 | 15.651 | 3.44322 | Groupe de modèles:Pavillon type:1258082
1258133 | Niveau: Plan des fondations Maisons 1 et 2 | 15.651 | 3.44322 | Groupe de modèles:Pavillon type:1258309
1282999 | Niveau: RDC | 15.792 | 3.47424
1360630 | Niveau: Plan des fondations Maisons 1 et 2 | 15.792 | 3.47424 | Groupe de modèles:Pavillon type:1360776

# IfcWallStandardCase: Mur de base:Ext. Parpaing 2 + 20 + 2 gris (8)
In: Plan des fondations Maisons 1 et 2
Type - PredefinedType: STANDARD; Material: Enduit gris 0.02 m, Parpaing 0.2 m, Enduit gris 0.02 m
Type - Autre - Catégorie: Murs; Nom de la famille: Mur de base
Type - Construction - Fonction: Extérieur; Retournement aux extrémités: Aucun(e); Retournement aux insertions: Les deux; Largeur: 0.24 m
Type - Données d'identification - Commentaires du type: Ext. Parpaing 20 + Isolant 10; Nom du type: Ext. Parpaing 2 + 20 + 2 gris
Type - Graphismes - Couleur vue détail faible: 0
Type - Matériaux et finitions - Matériau structurel: Parpaing
Type - Propriétés analytiques - Rugosité: 1; Coefficient d'absorbance: 0.1
Autre - Famille: Mur de base: Ext. Parpaing 2 + 20 + 2 gris; Famille et type: Mur de base: Ext. Parpaing 2 + 20 + 2 gris; ID du type: Mur de base: Ext. Parpaing 2 + 20 + 2 gris; Type: Mur de base: Ext. Parpaing 2 + 20 + 2 gris
Contraintes - Décalage inférieur: 0 m; Décalage supérieur: 0 m; Contrainte supérieure: Niveau: ETAGE; Extension inférieure: 0 m; Extension supérieure: 0 m; Lié au volume: no; Ligne de justification: Nu fini: Extérieur; Limite de pièce: yes; Partie inférieure attachée: no; Partie supérieure attachée: no; Hauteur non contrainte: 2.82 m
Phase de construction - Phase de création: Nouvelle construction
Structure - Activer le modèle analytique: no; Structure: no; Utilisation structurelle: Non porteur
Pset_WallCommon - LoadBearing: no; ExtendToStructure: no; IsExternal: yes; Reference: Ext. Parpaing 2 + 20 + 2 gris
Name (Mur de base:Ext. Parpaing 2 + 20 + 2 gris:...) | Contrainte inférieure | Longueur (m) | Surface (m2) | Volume (m3) | Group
1257901 | Niveau: Plan des fondations Maisons 1 et 2 | 2.9 | 8.5164 | 2.04394 | Groupe de modèles:Pavillon type:1258082
1257904 | Niveau: Plan des fondations Maisons 1 et 2 | 3.47 | 4.4277 | 1.06265 | Groupe de modèles:Pavillon type:1258082
1258135 | Niveau: Plan des fondations Maisons 1 et 2 | 2.9 | 8.5164 | 2.04394 | Groupe de modèles:Pavillon type:1258309
1258138 | Niveau: Plan des fondations Maisons 1 et 2 | 3.47 | 4.4277 | 1.06265 | Groupe de modèles:Pavillon type:1258309
1283001 | Niveau: RDC | 2.9 | 8.5164 | 2.04394
1283004 | Niveau: RDC | 3.56577 | 4.4277 | 1.06265
1360632 | Niveau: Plan des fondations Maisons 1 et 2 | 2.9 | 8.5164 | 2.04394 | Groupe de modèles:Pavillon type:1360776
1360635 | Niveau: Plan des fondations Maisons 1 et 2 | 3.56577 | 4.69776 | 1.12746 | Groupe de modèles:Pavillon type:1360776

# IfcWallStandardCase: Mur de base:Ext. Parpaing 20 (24)
In: vs
Type - PredefinedType: STANDARD; Material: Parpaing 0.2 m
Type - Autre - Catégorie: Murs; Nom de la famille: Mur de base
Type - Construction - Fonction: Extérieur; Retournement aux extrémités: Aucun(e); Retournement aux insertions: Les deux; Largeur: 0.2 m
Type - Données d'identification - Commentaires du type: Ext. Parpaing 20 + Isolant 10; Nom du type: Ext. Parpaing 20
Type - Graphismes - Couleur vue détail faible: 0
Type - Matériaux et finitions - Matériau structurel: Parpaing
Type - Propriétés analytiques - Rugosité: 1; Coefficient d'absorbance: 0.1
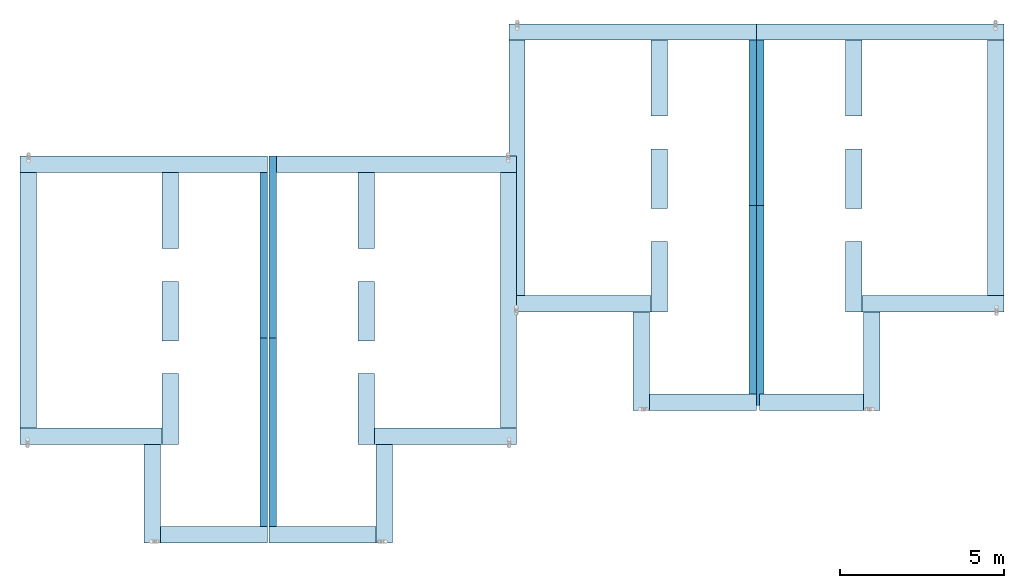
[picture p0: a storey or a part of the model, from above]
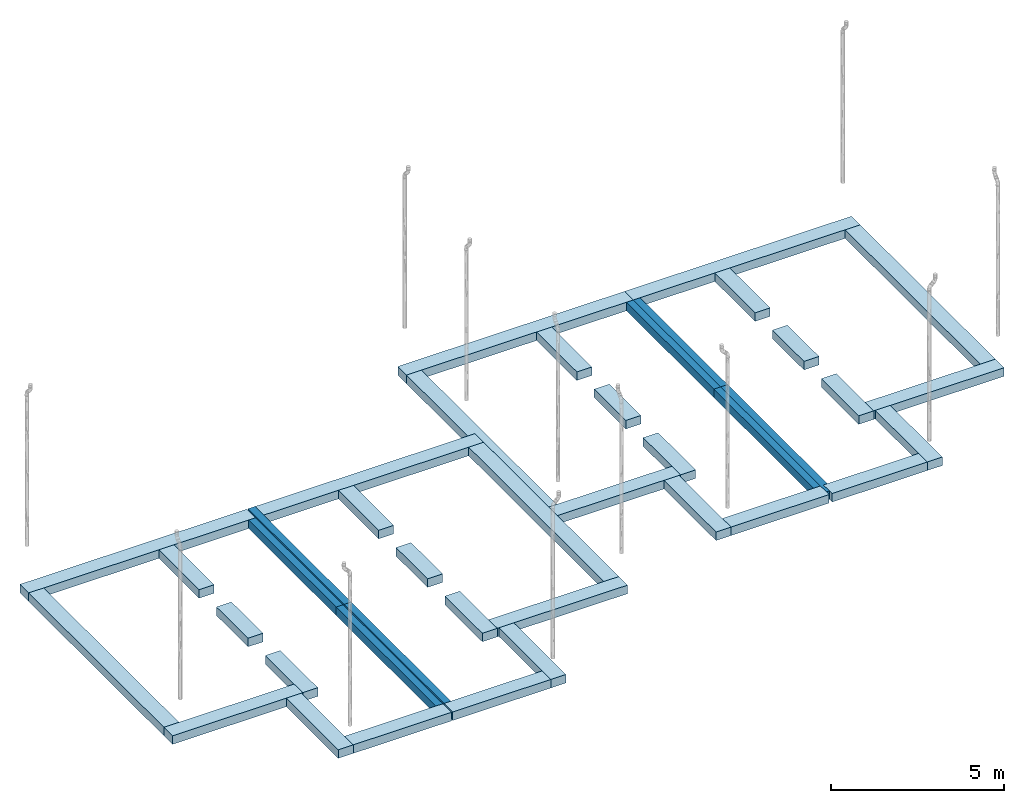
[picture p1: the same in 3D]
Properties of the parts of a building model (IFC2X3), part 3 of 3

# IfcWallStandardCase: Mur de base:Ext. Parpaing 20 (24)
Autre - Famille: Mur de base: Ext. Parpaing 20; Famille et type: Mur de base: Ext. Parpaing 20; ID du type: Mur de base: Ext. Parpaing 20; Type: Mur de base: Ext. Parpaing 20
Contraintes - Décalage supérieur: 0 m; Extension inférieure: 0 m; Extension supérieure: 0 m; Lié au volume: no; Ligne de justification: Nu fini: Extérieur; Limite de pièce: yes; Partie inférieure attachée: no; Contrainte inférieure: Niveau: vs; Décalage inférieur: -0.2 m; Hauteur non contrainte: 1 m
Phase de construction - Phase de création: Nouvelle construction
Structure - Activer le modèle analytique: no; Structure: no; Utilisation structurelle: Non porteur
Pset_WallCommon - LoadBearing: no; IsExternal: yes; Reference: Ext. Parpaing 20
Name (Mur de base:Ext. Parpaing 20:...) | Partie supérieure attachée = ExtendToStructure | Contrainte supérieure | Longueur (m) | Surface (m2) | Volume (m3) | Group
1330083 | no | Niveau: RDC | 7.35403 | 7.40826 | 1.48165
1330084 | yes | Niveau: RDC | 8.3 | 6.806 | 1.3612
1330085 | yes | Niveau: RDC | 4.33826 | 3.55738 | 0.711475
1330092 | yes | Niveau: RDC | 3.56577 | 2.8864 | 0.57728
1330093 | yes | Niveau: RDC | 3 | 2.296 | 0.4592
1330094 | yes | Niveau: RDC | 8.3 | 5.97496 | 1.19499
1332165 | no | Niveau: Plan des fondations Maisons 1 et 2 | 7.25826 | 7.40826 | 1.48165 | Groupe de modèles:Pavillon type:1258082
1332166 | no | Niveau: Plan des fondations Maisons 1 et 2 | 8.3 | 8.3 | 1.66 | Groupe de modèles:Pavillon type:1258082
1332167 | no | Niveau: Plan des fondations Maisons 1 et 2 | 4.33826 | 4.33826 | 0.867653 | Groupe de modèles:Pavillon type:1258082
1332171 | no | Niveau: Plan des fondations Maisons 1 et 2 | 3.47 | 3.52 | 0.704 | Groupe de modèles:Pavillon type:1258082
1332172 | no | Niveau: Plan des fondations Maisons 1 et 2 | 3 | 2.8 | 0.56 | Groupe de modèles:Pavillon type:1258082
1332173 | no | Niveau: Plan des fondations Maisons 1 et 2 | 8.3 | 7.43296 | 1.48659 | Groupe de modèles:Pavillon type:1258082
1332178 | no | Niveau: Plan des fondations Maisons 1 et 2 | 7.25826 | 7.40826 | 1.48165 | Groupe de modèles:Pavillon type:1258309
1332179 | no | Niveau: Plan des fondations Maisons 1 et 2 | 8.3 | 8.3 | 1.66 | Groupe de modèles:Pavillon type:1258309
1332180 | no | Niveau: Plan des fondations Maisons 1 et 2 | 4.33826 | 4.33826 | 0.867653 | Groupe de modèles:Pavillon type:1258309
1332184 | no | Niveau: Plan des fondations Maisons 1 et 2 | 3.47 | 3.52 | 0.704 | Groupe de modèles:Pavillon type:1258309
1332185 | no | Niveau: Plan des fondations Maisons 1 et 2 | 3 | 2.8 | 0.56 | Groupe de modèles:Pavillon type:1258309
1332186 | no | Niveau: Plan des fondations Maisons 1 et 2 | 8.3 | 7.43296 | 1.48659 | Groupe de modèles:Pavillon type:1258309
1360900 | no | Niveau: Plan des fondations Maisons 1 et 2 | 7.35403 | 7.40403 | 1.48081 | Groupe de modèles:Pavillon type:1360776
1360901 | yes | Niveau: Plan des fondations Maisons 1 et 2 | 8.3 | 6.806 | 1.3612 | Groupe de modèles:Pavillon type:1360776
1360902 | yes | Niveau: Plan des fondations Maisons 1 et 2 | 4.33826 | 3.55738 | 0.711475 | Groupe de modèles:Pavillon type:1360776
1360905 | yes | Niveau: Plan des fondations Maisons 1 et 2 | 3.56577 | 2.96493 | 0.592986 | Groupe de modèles:Pavillon type:1360776
1360906 | yes | Niveau: Plan des fondations Maisons 1 et 2 | 3 | 2.296 | 0.4592 | Groupe de modèles:Pavillon type:1360776
1360907 | yes | Niveau: Plan des fondations Maisons 1 et 2 | 8.3 | 5.97496 | 1.19499 | Groupe de modèles:Pavillon type:1360776

# IfcWallStandardCase: Mur de base:Ext. Parpaing 20 + 2 x 1.5 (8)
Type - PredefinedType: STANDARD; Material: Enduit blanc cassé2 0.015 m, Parpaing 0.2 m, Enduit blanc cassé2 0.015 m
Type - Autre - Catégorie: Murs; Nom de la famille: Mur de base
Type - Construction - Fonction: Extérieur; Retournement aux extrémités: Aucun(e); Retournement aux insertions: Les deux; Largeur: 0.23 m
Type - Données d'identification - Commentaires du type: Ext. Parpaing 20 + Isolant 10; Nom du type: Ext. Parpaing 20 + 2 x 1.5
Type - Graphismes - Couleur vue détail faible: 0
Type - Matériaux et finitions - Matériau structurel: Parpaing
Type - Propriétés analytiques - Rugosité: 1; Coefficient d'absorbance: 0.1
Autre - Famille: Mur de base: Ext. Parpaing 20 + 2 x 1.5; Famille et type: Mur de base: Ext. Parpaing 20 + 2 x 1.5; ID du type: Mur de base: Ext. Parpaing 20 + 2 x 1.5; Type: Mur de base: Ext. Parpaing 20 + 2 x 1.5
Contraintes - Décalage supérieur: 0 m; Extension inférieure: 0 m; Extension supérieure: 0 m; Lié au volume: no; Ligne de justification: Nu fini: Extérieur; Limite de pièce: yes; Partie inférieure attachée: no
Phase de construction - Phase de création: Nouvelle construction
Structure - Activer le modèle analytique: no; Structure: no; Utilisation structurelle: Non porteur
Pset_WallCommon - LoadBearing: no; IsExternal: yes; Reference: Ext. Parpaing 20 + 2 x 1.5
Name (Mur de base:Ext. Parpaing 20 + 2 x 1.5:...) | In | Décalage inférieur (m) | Partie supérieure attachée = ExtendToStructure | Contrainte inférieure | Hauteur non contrainte (m) | Longueur (m) | Surface (m2) | Volume (m3) | Group
1300698 | Plan des fondations Maisons 1 et 2 | 0 | no | Niveau: RDC | 1.41793 | 1.5 | 2.12689 | 0.450685 | Groupe de modèles:muret technique:1301639
1304946 | Plan des fondations Maisons 1 et 2 | 0 | no | Niveau: Plan des fondations Maisons 1 et 2 | 1.41793 | 1.5 | 2.12689 | 0.450685 | Groupe de modèles:muret technique:1304961
1305093 | Plan des fondations Maisons 1 et 2 | 0 | no | Niveau: Plan des fondations Maisons 1 et 2 | 1.41793 | 1.5 | 2.12689 | 0.450685 | Groupe de modèles:muret technique:1305108
1305386 | Plan des fondations Maisons 1 et 2 | 0 | no | Niveau: Plan des fondations Maisons 1 et 2 | 1.41793 | 1.5 | 2.12689 | 0.450685 | Groupe de modèles:muret technique:1305401
1349049 | ETAGE | 2.88289 | yes | Niveau: ETAGE | 0.78 | 3.39038 | 2.08549 | 0.458455
1349624 | ETAGE | 2.88289 | yes | Niveau: ETAGE | 0.78 | 3.39038 | 2.08549 | 0.458455 | Groupe de modèles:Pavillon type:1258082
1349628 | ETAGE | 2.88289 | yes | Niveau: ETAGE | 0.78 | 3.39038 | 2.08549 | 0.458455 | Groupe de modèles:Pavillon type:1258309
1360959 | ETAGE | 2.88289 | yes | Niveau: ETAGE | 0.78 | 3.39038 | 2.08549 | 0.458455 | Groupe de modèles:Pavillon type:1360776

# IfcWallStandardCase: Mur de base:Ext. Parpaing 20 + Isolant 10 enduit blanc cassé (24)
Type - PredefinedType: STANDARD; Material: Enduit blanc cassé2 0.02 m, Parpaing 0.2 m, Isolant 0.1 m
Type - Autre - Catégorie: Murs; Nom de la famille: Mur de base
Type - Construction - Fonction: Extérieur; Largeur: 0.32 m; Retournement aux extrémités: Aucun(e); Retournement aux insertions: Les deux
Type - Données d'identification - Commentaires du type: Ext. Parpaing 20 + Isolant 10; Nom du type: Ext. Parpaing 20 + Isolant 10 enduit blanc cassé
Type - Graphismes - Couleur vue détail faible: 0
Type - Matériaux et finitions - Matériau structurel: Parpaing
Type - Propriétés analytiques - Coefficient d'absorbance: 0.1; Rugosité: 1
Autre - Famille: Mur de base: Ext. Parpaing 20 + Isolant 10 enduit blanc cassé; Famille et type: Mur de base: Ext. Parpaing 20 + Isolant 10 enduit blanc cassé; ID du type: Mur de base: Ext. Parpaing 20 + Isolant 10 enduit blanc cassé; Type: Mur de base: Ext. Parpaing 20 + Isolant 10 enduit blanc cassé
Contraintes - Décalage inférieur: 0 m; Décalage supérieur: 0 m; Extension inférieure: 0 m; Extension supérieure: 0 m; Hauteur non contrainte: 2.82 m; Lié au volume: no; Ligne de justification: Nu fini: Extérieur; Limite de pièce: yes; Partie inférieure attachée: no
Phase de construction - Phase de création: Nouvelle construction
Structure - Activer le modèle analytique: no; Structure: no; Utilisation structurelle: Non porteur
Pset_WallCommon - Reference: Ext. Parpaing 20 + Isolant 10 enduit blanc cassé; LoadBearing: no; IsExternal: yes
Name (Mur de base:Ext. Parpaing 20 + Isolant 10 enduit blanc cassé:...) | In | Contrainte inférieure | Contrainte supérieure | Partie supérieure attachée = ExtendToStructure | Longueur (m) | Surface (m2) | Volume (m3) | Group
1257897 | Plan des fondations Maisons 1 et 2 | Niveau: Plan des fondations Maisons 1 et 2 | Niveau: ETAGE | no | 8.22 | 24.0828 | 7.7065 | Groupe de modèles:Pavillon type:1258082
1257898 | Plan des fondations Maisons 1 et 2 | Niveau: Plan des fondations Maisons 1 et 2 | Niveau: ETAGE | no | 7.17826 | 13.1507 | 4.11628 | Groupe de modèles:Pavillon type:1258082
1257900 | Plan des fondations Maisons 1 et 2 | Niveau: Plan des fondations Maisons 1 et 2 | Niveau: ETAGE | no | 4.37826 | 7.94955 | 2.47863 | Groupe de modèles:Pavillon type:1258082
1258029 | ETAGE | Niveau: ETAGE | Niveau: Egout | yes | 7.30615 | 22.4341 | 7.03677 | Groupe de modèles:Pavillon type:1258082
1258030 | ETAGE | Niveau: ETAGE | Niveau: Egout | yes | 8.22 | 40.0214 | 12.8068 | Groupe de modèles:Pavillon type:1258082
1258031 | ETAGE | Niveau: ETAGE | Niveau: Egout | yes | 3.78826 | 11.4127 | 3.579 | Groupe de modèles:Pavillon type:1258082
1258131 | Plan des fondations Maisons 1 et 2 | Niveau: Plan des fondations Maisons 1 et 2 | Niveau: ETAGE | no | 8.22 | 24.0828 | 7.7065 | Groupe de modèles:Pavillon type:1258309
1258132 | Plan des fondations Maisons 1 et 2 | Niveau: Plan des fondations Maisons 1 et 2 | Niveau: ETAGE | no | 7.17826 | 13.1507 | 4.11628 | Groupe de modèles:Pavillon type:1258309
1258134 | Plan des fondations Maisons 1 et 2 | Niveau: Plan des fondations Maisons 1 et 2 | Niveau: ETAGE | no | 4.37826 | 7.94955 | 2.47863 | Groupe de modèles:Pavillon type:1258309
1258256 | ETAGE | Niveau: ETAGE | Niveau: Egout | yes | 7.27038 | 22.3074 | 6.99749 | Groupe de modèles:Pavillon type:1258309
1258257 | ETAGE | Niveau: ETAGE | Niveau: Egout | yes | 8.22 | 40.0214 | 12.8068 | Groupe de modèles:Pavillon type:1258309
1258258 | ETAGE | Niveau: ETAGE | Niveau: Egout | yes | 3.78826 | 11.4127 | 3.579 | Groupe de modèles:Pavillon type:1258309
1282997 | Plan des fondations Maisons 1 et 2 | Niveau: RDC | Niveau: ETAGE | no | 8.22 | 24.0828 | 7.7065
1282998 | Plan des fondations Maisons 1 et 2 | Niveau: RDC | Niveau: ETAGE | no | 7.35403 | 13.1507 | 4.11628
1283000 | Plan des fondations Maisons 1 et 2 | Niveau: RDC | Niveau: ETAGE | no | 4.37826 | 7.94955 | 2.47863
1283112 | ETAGE | Niveau: ETAGE | Niveau: Egout | yes | 7.30615 | 22.4341 | 7.03677
1283113 | ETAGE | Niveau: ETAGE | Niveau: Egout | yes | 8.22 | 40.0214 | 12.8068
1283114 | ETAGE | Niveau: ETAGE | Niveau: Egout | yes | 3.78826 | 11.4127 | 3.579
1360628 | Plan des fondations Maisons 1 et 2 | Niveau: Plan des fondations Maisons 1 et 2 | Niveau: ETAGE | no | 8.22 | 24.0828 | 7.7065 | Groupe de modèles:Pavillon type:1360776
1360629 | Plan des fondations Maisons 1 et 2 | Niveau: Plan des fondations Maisons 1 et 2 | Niveau: ETAGE | no | 7.35403 | 13.026 | 4.07636 | Groupe de modèles:Pavillon type:1360776
1360631 | Plan des fondations Maisons 1 et 2 | Niveau: Plan des fondations Maisons 1 et 2 | Niveau: ETAGE | no | 4.37826 | 7.94955 | 2.47863 | Groupe de modèles:Pavillon type:1360776
1360732 | ETAGE | Niveau: ETAGE | Niveau: Egout | yes | 7.30615 | 22.4341 | 7.03677 | Groupe de modèles:Pavillon type:1360776
1360733 | ETAGE | Niveau: ETAGE | Niveau: Egout | yes | 8.22 | 40.0214 | 12.8068 | Groupe de modèles:Pavillon type:1360776
1360734 | ETAGE | Niveau: ETAGE | Niveau: Egout | yes | 3.78826 | 11.4127 | 3.579 | Groupe de modèles:Pavillon type:1360776

# IfcWallStandardCase: Mur de base:Ext. Parpaing 20 + Isolant 10 enduit gris (8)
In: ETAGE
Type - PredefinedType: STANDARD; Material: Enduit gris 0.02 m, Parpaing 0.2 m, Isolant 0.1 m
Type - Autre - Catégorie: Murs; Nom de la famille: Mur de base
Type - Construction - Fonction: Extérieur; Retournement aux extrémités: Aucun(e); Retournement aux insertions: Les deux; Largeur: 0.32 m
Type - Données d'identification - Commentaires du type: Ext. Parpaing 20 + Isolant 10; Nom du type: Ext. Parpaing 20 + Isolant 10 enduit gris
Type - Graphismes - Couleur vue détail faible: 0
Type - Matériaux et finitions - Matériau structurel: Parpaing
Type - Propriétés analytiques - Rugosité: 1; Coefficient d'absorbance: 0.1
Autre - Famille: Mur de base: Ext. Parpaing 20 + Isolant 10 enduit gris; Famille et type: Mur de base: Ext. Parpaing 20 + Isolant 10 enduit gris; ID du type: Mur de base: Ext. Parpaing 20 + Isolant 10 enduit gris; Type: Mur de base: Ext. Parpaing 20 + Isolant 10 enduit gris
Contraintes - Décalage inférieur: 0 m; Extension inférieure: 0 m; Extension supérieure: 0 m; Lié au volume: no; Ligne de justification: Nu fini: Extérieur; Limite de pièce: yes; Partie inférieure attachée: no; Contrainte inférieure: Niveau: ETAGE; Contrainte supérieure: Niveau: Egout; Partie supérieure attachée: yes; Décalage supérieur: 0.2 m; Hauteur non contrainte: 3.02 m
Phase de construction - Phase de création: Nouvelle construction
Structure - Activer le modèle analytique: no; Structure: no; Utilisation structurelle: Non porteur
Pset_WallCommon - LoadBearing: no; IsExternal: yes; ExtendToStructure: yes; Reference: Ext. Parpaing 20 + Isolant 10 enduit gris
Name (Mur de base:Ext. Parpaing 20 + Isolant 10 enduit gris:...) | Longueur (m) | Surface (m2) | Volume (m3) | Group
1258032 | 3 | 9.31627 | 2.98121 | Groupe de modèles:Pavillon type:1258082
1258033 | 3.39038 | 6.77144 | 2.17557 | Groupe de modèles:Pavillon type:1258082
1258259 | 3 | 9.31627 | 2.98121 | Groupe de modèles:Pavillon type:1258309
1258260 | 3.60962 | 7.36776 | 2.36927 | Groupe de modèles:Pavillon type:1258309
1283115 | 3 | 9.31627 | 2.98121
1283116 | 3.56538 | 7.24744 | 2.33019
1360735 | 3 | 9.31627 | 2.98121 | Groupe de modèles:Pavillon type:1360776
1360736 | 3.39038 | 6.77144 | 2.17557 | Groupe de modèles:Pavillon type:1360776

# IfcWallStandardCase: Mur de base:Int. Platre 100 mm en blanc 2 (8)
In: Plan des fondations Maisons 1 et 2
Type - PredefinedType: STANDARD; Material: Peinture - Blanc 0.1 m
Type - Autre - Catégorie: Murs; Nom de la famille: Mur de base
Type - Construction - Fonction: Intérieur; Retournement aux extrémités: Aucun(e); Largeur: 0.1 m; Retournement aux insertions: Ne pas retourner
Type - Données d'identification - Commentaires du type: Int. Platre 70 mm; Nom du type: Int. Platre 100 mm en blanc 2
Type - Graphismes - Couleur vue détail faible: 16777215
Type - Matériaux et finitions - Matériau structurel: Peinture - Blanc
Type - Propriétés analytiques - Rugosité: 1; Coefficient d'absorbance: 0.1
Autre - Famille: Mur de base: Int. Platre 100 mm en blanc 2; Famille et type: Mur de base: Int. Platre 100 mm en blanc 2; ID du type: Mur de base: Int. Platre 100 mm en blanc 2; Type: Mur de base: Int. Platre 100 mm en blanc 2
Contraintes - Décalage inférieur: 0 m; Décalage supérieur: 0 m; Contrainte supérieure: Niveau: ETAGE; Extension inférieure: 0 m; Extension supérieure: 0 m; Lié au volume: no; Ligne de justification: Nu fini: Extérieur; Limite de pièce: yes; Partie inférieure attachée: no; Partie supérieure attachée: no; Hauteur non contrainte: 2.82 m
Phase de construction - Phase de création: Nouvelle construction
Structure - Activer le modèle analytique: no; Structure: no; Utilisation structurelle: Non porteur
Pset_WallCommon - IsExternal: no; LoadBearing: no; ExtendToStructure: no; Reference: Int. Platre 100 mm en blanc 2
Name (Mur de base:Int. Platre 100 mm en blanc 2:...) | Contrainte inférieure | Longueur (m) | Surface (m2) | Volume (m3) | Group
1257902 | Niveau: Plan des fondations Maisons 1 et 2 | 2.98 | 8.4459 | 0.84459 | Groupe de modèles:Pavillon type:1258082
1258136 | Niveau: Plan des fondations Maisons 1 et 2 | 2.98 | 8.4459 | 0.84459 | Groupe de modèles:Pavillon type:1258309
1282288 | Niveau: Plan des fondations Maisons 1 et 2 | 2.29 | 4.7313 | 0.47313 | Groupe de modèles:Pavillon type:1258082
1282292 | Niveau: Plan des fondations Maisons 1 et 2 | 2.29 | 4.7313 | 0.47313 | Groupe de modèles:Pavillon type:1258309
1283002 | Niveau: RDC | 3.11577 | 8.0793 | 0.795945
1283210 | Niveau: RDC | 2.29 | 4.7313 | 0.47313
1360633 | Niveau: Plan des fondations Maisons 1 et 2 | 3.11577 | 8.34936 | 0.834231 | Groupe de modèles:Pavillon type:1360776
1360814 | Niveau: Plan des fondations Maisons 1 et 2 | 2.29 | 4.7313 | 0.47313 | Groupe de modèles:Pavillon type:1360776

# IfcWallStandardCase: Mur de base:Int. Platre 70 mm en blanc (80)
Type - PredefinedType: STANDARD; Material: Peinture - Blanc 0.07 m
Type - Autre - Catégorie: Murs; Nom de la famille: Mur de base
Type - Construction - Fonction: Intérieur; Retournement aux extrémités: Aucun(e); Retournement aux insertions: Ne pas retourner; Largeur: 0.07 m
Type - Données d'identification - Commentaires du type: Int. Platre 70 mm; Nom du type: Int. Platre 70 mm en blanc
Type - Graphismes - Couleur vue détail faible: 16777215
Type - Matériaux et finitions - Matériau structurel: Peinture - Blanc
Type - Propriétés analytiques - Rugosité: 1; Coefficient d'absorbance: 0.1
Autre - Famille: Mur de base: Int. Platre 70 mm en blanc; Famille et type: Mur de base: Int. Platre 70 mm en blanc; ID du type: Mur de base: Int. Platre 70 mm en blanc; Type: Mur de base: Int. Platre 70 mm en blanc
Contraintes - Décalage inférieur: 0 m; Décalage supérieur: 0 m; Extension inférieure: 0 m; Extension supérieure: 0 m; Lié au volume: no; Limite de pièce: yes; Partie inférieure attachée: no; Partie supérieure attachée: no; Ligne de justification: Axe porteur
Phase de construction - Phase de création: Nouvelle construction
Structure - Activer le modèle analytique: no; Structure: no; Utilisation structurelle: Non porteur
Pset_WallCommon - IsExternal: no; LoadBearing: no; ExtendToStructure: no; Reference: Int. Platre 70 mm en blanc
Name (Mur de base:Int. Platre 70 mm en blanc:...) | In | Contrainte inférieure | Hauteur non contrainte (m) | Longueur (m) | Surface (m2) | Volume (m3) | Group
1257981 | Plan des fondations Maisons 1 et 2 | Niveau: Plan des fondations Maisons 1 et 2 | 2.82 | 3.57712 | 9.87597 | 0.691318 | Groupe de modèles:Pavillon type:1258082 | Contraintes - Contrainte supérieure: Niveau: ETAGE
1257982 | Plan des fondations Maisons 1 et 2 | Niveau: Plan des fondations Maisons 1 et 2 | 2.82 | 1.79313 | 4.85922 | 0.340146 | Groupe de modèles:Pavillon type:1258082 | Contraintes - Contrainte supérieure: Niveau: ETAGE
1257983 | Plan des fondations Maisons 1 et 2 | Niveau: Plan des fondations Maisons 1 et 2 | 2.45351 | 1.48672 | 3.73354 | 0.261348 | Groupe de modèles:Pavillon type:1258082
1257984 | Plan des fondations Maisons 1 et 2 | Niveau: Plan des fondations Maisons 1 et 2 | 1.9 | 1.79 | 3.268 | 0.22876 | Groupe de modèles:Pavillon type:1258082
1257985 | Plan des fondations Maisons 1 et 2 | Niveau: Plan des fondations Maisons 1 et 2 | 2.82 | 0.9554 | 1.13293 | 0.079305 | Groupe de modèles:Pavillon type:1258082 | Contraintes - Contrainte supérieure: Niveau: ETAGE
1258035 | ETAGE | Niveau: ETAGE | 2.52 | 4.645 | 9.554 | 0.66878 | Groupe de modèles:Pavillon type:1258082
1258036 | ETAGE | Niveau: ETAGE | 2.52 | 3.84538 | 7.66497 | 0.536548 | Groupe de modèles:Pavillon type:1258082
1258037 | ETAGE | Niveau: ETAGE | 2.52 | 2.65705 | 6.50676 | 0.455473 | Groupe de modèles:Pavillon type:1258082
1258038 | ETAGE | Niveau: ETAGE | 2.6 | 3.575 | 7.31 | 0.5117 | Groupe de modèles:Pavillon type:1258082
1258039 | ETAGE | Niveau: ETAGE | 2.52 | 3.48115 | 5.76109 | 0.403276 | Groupe de modèles:Pavillon type:1258082
1258040 | ETAGE | Niveau: ETAGE | 2.52 | 2.75212 | 5.27533 | 0.369273 | Groupe de modèles:Pavillon type:1258082
1258041 | ETAGE | Niveau: ETAGE | 2.6 | 1.04332 | 0.870631 | 0.0609441 | Groupe de modèles:Pavillon type:1258082
1258047 | ETAGE | Niveau: ETAGE | 2.6 | 3.33326 | 5.63948 | 0.394764 | Groupe de modèles:Pavillon type:1258082
1258048 | ETAGE | Niveau: ETAGE | 2.6 | 0.6 | 1.378 | 0.09646 | Groupe de modèles:Pavillon type:1258082
1258214 | Plan des fondations Maisons 1 et 2 | Niveau: Plan des fondations Maisons 1 et 2 | 2.82 | 3.57712 | 9.87597 | 0.691318 | Groupe de modèles:Pavillon type:1258309 | Contraintes - Contrainte supérieure: Niveau: ETAGE
1258215 | Plan des fondations Maisons 1 et 2 | Niveau: Plan des fondations Maisons 1 et 2 | 2.82 | 1.79313 | 4.85922 | 0.340146 | Groupe de modèles:Pavillon type:1258309 | Contraintes - Contrainte supérieure: Niveau: ETAGE
1258216 | Plan des fondations Maisons 1 et 2 | Niveau: Plan des fondations Maisons 1 et 2 | 2.45351 | 1.48672 | 3.73354 | 0.261348 | Groupe de modèles:Pavillon type:1258309
1258217 | Plan des fondations Maisons 1 et 2 | Niveau: Plan des fondations Maisons 1 et 2 | 1.9 | 1.79 | 3.268 | 0.22876 | Groupe de modèles:Pavillon type:1258309
1258218 | Plan des fondations Maisons 1 et 2 | Niveau: Plan des fondations Maisons 1 et 2 | 2.82 | 0.9554 | 1.13293 | 0.079305 | Groupe de modèles:Pavillon type:1258309 | Contraintes - Contrainte supérieure: Niveau: ETAGE
1258262 | ETAGE | Niveau: ETAGE | 2.52 | 4.645 | 9.554 | 0.66878 | Groupe de modèles:Pavillon type:1258309
1258263 | ETAGE | Niveau: ETAGE | 2.52 | 3.84538 | 7.66497 | 0.536548 | Groupe de modèles:Pavillon type:1258309
1258264 | ETAGE | Niveau: ETAGE | 2.52 | 2.65705 | 6.50676 | 0.455473 | Groupe de modèles:Pavillon type:1258309
1258265 | ETAGE | Niveau: ETAGE | 2.6 | 3.575 | 7.31 | 0.5117 | Groupe de modèles:Pavillon type:1258309
1258266 | ETAGE | Niveau: ETAGE | 2.52 | 3.48115 | 5.76109 | 0.403276 | Groupe de modèles:Pavillon type:1258309
1258267 | ETAGE | Niveau: ETAGE | 2.52 | 2.75212 | 5.27533 | 0.369273 | Groupe de modèles:Pavillon type:1258309
1258268 | ETAGE | Niveau: ETAGE | 2.6 | 1.04332 | 0.870631 | 0.0609441 | Groupe de modèles:Pavillon type:1258309
1258274 | ETAGE | Niveau: ETAGE | 2.6 | 3.33326 | 5.63948 | 0.394764 | Groupe de modèles:Pavillon type:1258309
1258275 | ETAGE | Niveau: ETAGE | 2.6 | 0.6 | 1.378 | 0.09646 | Groupe de modèles:Pavillon type:1258309
1277790 | ETAGE | Niveau: ETAGE | 2.52 | 2.54538 | 6.22537 | 0.435776 | Groupe de modèles:Pavillon type:1258082
1277791 | ETAGE | Niveau: ETAGE | 2.52 | 1.87 | 3.03585 | 0.140585 | Groupe de modèles:Pavillon type:1258082
1277802 | ETAGE | Niveau: ETAGE | 2.52 | 2.54538 | 6.22537 | 0.435776 | Groupe de modèles:Pavillon type:1258309
1277803 | ETAGE | Niveau: ETAGE | 2.52 | 1.87 | 3.03585 | 0.140585 | Groupe de modèles:Pavillon type:1258309
1283080 | Plan des fondations Maisons 1 et 2 | Niveau: Plan des fondations Maisons 1 et 2 | 2.82 | 3.57712 | 9.87597 | 0.691318 | Contraintes - Contrainte supérieure: Niveau: ETAGE
1283081 | Plan des fondations Maisons 1 et 2 | Niveau: Plan des fondations Maisons 1 et 2 | 2.82 | 1.79313 | 4.85922 | 0.340146 | Contraintes - Contrainte supérieure: Niveau: ETAGE
1283082 | Plan des fondations Maisons 1 et 2 | Niveau: Plan des fondations Maisons 1 et 2 | 2.45351 | 1.48672 | 3.56179 | 0.249326
1283083 | Plan des fondations Maisons 1 et 2 | Niveau: Plan des fondations Maisons 1 et 2 | 1.9 | 1.79 | 3.401 | 0.23807
1283084 | Plan des fondations Maisons 1 et 2 | Niveau: Plan des fondations Maisons 1 et 2 | 2.82 | 0.9554 | 1.13293 | 0.079305 | Contraintes - Contrainte supérieure: Niveau: ETAGE
1283118 | ETAGE | Niveau: ETAGE | 2.52 | 4.645 | 9.554 | 0.66878
1283119 | ETAGE | Niveau: ETAGE | 2.52 | 3.84538 | 7.66497 | 0.536548
1283120 | ETAGE | Niveau: ETAGE | 2.52 | 2.65705 | 6.50676 | 0.455473
1283121 | ETAGE | Niveau: ETAGE | 2.6 | 3.575 | 7.31 | 0.5117
1283122 | ETAGE | Niveau: ETAGE | 2.52 | 3.48115 | 5.76109 | 0.403276
1283123 | ETAGE | Niveau: ETAGE | 2.52 | 2.75212 | 5.27533 | 0.369273
1283124 | ETAGE | Niveau: ETAGE | 2.6 | 1.04332 | 0.870631 | 0.0609441
1283130 | ETAGE | Niveau: ETAGE | 2.6 | 3.33326 | 5.63948 | 0.394764
1283131 | ETAGE | Niveau: ETAGE | 2.6 | 0.6 | 1.378 | 0.09646
1283188 | ETAGE | Niveau: ETAGE | 2.52 | 2.54538 | 6.22537 | 0.435776
1283189 | ETAGE | Niveau: ETAGE | 2.52 | 1.87 | 3.03585 | 0.140585
1286010 | Plan des fondations Maisons 1 et 2 | Niveau: RDC | 2.5 | 1.125 | 2.45 | 0.1715
1286236 | Plan des fondations Maisons 1 et 2 | Niveau: Plan des fondations Maisons 1 et 2 | 2.5 | 1.125 | 2.45 | 0.1715 | Groupe de modèles:Pavillon type:1258082
1286241 | Plan des fondations Maisons 1 et 2 | Niveau: Plan des fondations Maisons 1 et 2 | 2.5 | 1.125 | 2.45 | 0.1715 | Groupe de modèles:Pavillon type:1258309
1286274 | Plan des fondations Maisons 1 et 2 | Niveau: RDC | 2.6 | 0.96 | 2.418 | 0.16926
1286300 | Plan des fondations Maisons 1 et 2 | Niveau: RDC | 2.6 | 0.86 | 2.015 | 0.14105
1286468 | Plan des fondations Maisons 1 et 2 | Niveau: Plan des fondations Maisons 1 et 2 | 2.6 | 0.96 | 2.418 | 0.16926 | Groupe de modèles:Pavillon type:1258082
1286469 | Plan des fondations Maisons 1 et 2 | Niveau: Plan des fondations Maisons 1 et 2 | 2.6 | 0.86 | 2.015 | 0.14105 | Groupe de modèles:Pavillon type:1258082
1286473 | Plan des fondations Maisons 1 et 2 | Niveau: Plan des fondations Maisons 1 et 2 | 2.6 | 0.96 | 2.418 | 0.16926 | Groupe de modèles:Pavillon type:1258309
1286474 | Plan des fondations Maisons 1 et 2 | Niveau: Plan des fondations Maisons 1 et 2 | 2.6 | 0.86 | 2.015 | 0.14105 | Groupe de modèles:Pavillon type:1258309
1308594 | ETAGE | Niveau: ETAGE | 2.6 | 1.04332 | 2.53063 | 0.177144
1308815 | ETAGE | Niveau: ETAGE | 2.6 | 1.04332 | 2.53063 | 0.177144 | Groupe de modèles:Pavillon type:1258082
1308818 | ETAGE | Niveau: ETAGE | 2.6 | 1.04332 | 2.53063 | 0.177144 | Groupe de modèles:Pavillon type:1258309
1360704 | Plan des fondations Maisons 1 et 2 | Niveau: Plan des fondations Maisons 1 et 2 | 2.82 | 3.57712 | 9.87597 | 0.691318 | Groupe de modèles:Pavillon type:1360776 | Contraintes - Contrainte supérieure: Niveau: ETAGE
1360705 | Plan des fondations Maisons 1 et 2 | Niveau: Plan des fondations Maisons 1 et 2 | 2.82 | 1.79313 | 4.85922 | 0.340146 | Groupe de modèles:Pavillon type:1360776 | Contraintes - Contrainte supérieure: Niveau: ETAGE
1360706 | Plan des fondations Maisons 1 et 2 | Niveau: Plan des fondations Maisons 1 et 2 | 2.45351 | 1.48672 | 3.56179 | 0.249326 | Groupe de modèles:Pavillon type:1360776
1360707 | Plan des fondations Maisons 1 et 2 | Niveau: Plan des fondations Maisons 1 et 2 | 1.9 | 1.79 | 3.401 | 0.23807 | Groupe de modèles:Pavillon type:1360776
1360708 | Plan des fondations Maisons 1 et 2 | Niveau: Plan des fondations Maisons 1 et 2 | 2.82 | 0.9554 | 1.13293 | 0.079305 | Groupe de modèles:Pavillon type:1360776 | Contraintes - Contrainte supérieure: Niveau: ETAGE
1360738 | ETAGE | Niveau: ETAGE | 2.52 | 4.645 | 9.554 | 0.66878 | Groupe de modèles:Pavillon type:1360776
1360739 | ETAGE | Niveau: ETAGE | 2.52 | 3.84538 | 7.66497 | 0.536548 | Groupe de modèles:Pavillon type:1360776
1360740 | ETAGE | Niveau: ETAGE | 2.52 | 2.65705 | 6.50676 | 0.455473 | Groupe de modèles:Pavillon type:1360776
1360741 | ETAGE | Niveau: ETAGE | 2.6 | 3.575 | 7.31 | 0.5117 | Groupe de modèles:Pavillon type:1360776
1360742 | ETAGE | Niveau: ETAGE | 2.52 | 3.48115 | 5.76109 | 0.403276 | Groupe de modèles:Pavillon type:1360776
1360743 | ETAGE | Niveau: ETAGE | 2.52 | 2.75212 | 5.27533 | 0.369273 | Groupe de modèles:Pavillon type:1360776
1360744 | ETAGE | Niveau: ETAGE | 2.6 | 1.04332 | 0.870631 | 0.0609441 | Groupe de modèles:Pavillon type:1360776
1360750 | ETAGE | Niveau: ETAGE | 2.6 | 3.33326 | 5.63948 | 0.394764 | Groupe de modèles:Pavillon type:1360776
1360751 | ETAGE | Niveau: ETAGE | 2.6 | 0.6 | 1.378 | 0.09646 | Groupe de modèles:Pavillon type:1360776
1360800 | ETAGE | Niveau: ETAGE | 2.52 | 2.54538 | 6.22537 | 0.435776 | Groupe de modèles:Pavillon type:1360776
1360801 | ETAGE | Niveau: ETAGE | 2.52 | 1.87 | 3.03585 | 0.140585 | Groupe de modèles:Pavillon type:1360776
1360832 | Plan des fondations Maisons 1 et 2 | Niveau: Plan des fondations Maisons 1 et 2 | 2.5 | 1.125 | 2.45 | 0.1715 | Groupe de modèles:Pavillon type:1360776
1360833 | Plan des fondations Maisons 1 et 2 | Niveau: Plan des fondations Maisons 1 et 2 | 2.6 | 0.96 | 2.418 | 0.16926 | Groupe de modèles:Pavillon type:1360776
1360834 | Plan des fondations Maisons 1 et 2 | Niveau: Plan des fondations Maisons 1 et 2 | 2.6 | 0.86 | 2.015 | 0.14105 | Groupe de modèles:Pavillon type:1360776
1360899 | ETAGE | Niveau: ETAGE | 2.6 | 1.04332 | 2.53063 | 0.177144 | Groupe de modèles:Pavillon type:1360776

# IfcWallStandardCase: Mur de base:MITOYEN. Parpaing 10 + Isolant 10+ PLACO 2 (4)
In: ETAGE
Type - PredefinedType: STANDARD; Material: Enduit blanc cassé2 0.02 m, Parpaing 0.1 m, Isolant 0.1 m
Type - Autre - Catégorie: Murs; Nom de la famille: Mur de base
Type - Construction - Fonction: Extérieur; Retournement aux extrémités: Aucun(e); Retournement aux insertions: Les deux; Largeur: 0.22 m
Type - Données d'identification - Commentaires du type: Ext. Parpaing 20 + Isolant 10; Nom du type: MITOYEN. Parpaing 10 + Isolant 10+ PLACO 2
Type - Graphismes - Couleur vue détail faible: 0
Type - Matériaux et finitions - Matériau structurel: Parpaing
Type - Propriétés analytiques - Rugosité: 1; Coefficient d'absorbance: 0.1
Autre - Famille: Mur de base: MITOYEN. Parpaing 10 + Isolant 10+ PLACO 2; Famille et type: Mur de base: MITOYEN. Parpaing 10 + Isolant 10+ PLACO 2; ID du type: Mur de base: MITOYEN. Parpaing 10 + Isolant 10+ PLACO 2; Type: Mur de base: MITOYEN. Parpaing 10 + Isolant 10+ PLACO 2
Contraintes - Décalage inférieur: 0 m; Extension inférieure: 0 m; Extension supérieure: 0 m; Lié au volume: no; Ligne de justification: Nu fini: Extérieur; Limite de pièce: yes; Partie inférieure attachée: no; Contrainte inférieure: Niveau: ETAGE; Contrainte supérieure: Niveau: Egout; Partie supérieure attachée: yes; Décalage supérieur: 0.2 m; Hauteur non contrainte: 3.02 m
Cotes - Longueur: 11.22 m
Phase de construction - Phase de création: Nouvelle construction
Structure - Activer le modèle analytique: no; Structure: no; Utilisation structurelle: Non porteur
Pset_WallCommon - LoadBearing: no; IsExternal: yes; ExtendToStructure: yes; Reference: MITOYEN. Parpaing 10 + Isolant 10+ PLACO 2
Name (Mur de base:MITOYEN. Parpaing 10 + Isolant 10+ PLACO 2:...) | Surface (m2) | Volume (m3) | Group
1258034 | 49.307 | 10.8475 | Groupe de modèles:Pavillon type:1258082
1258261 | 48.4235 | 10.6532 | Groupe de modèles:Pavillon type:1258309
1283117 | 48.4235 | 10.6532
1360737 | 49.307 | 10.8475 | Groupe de modèles:Pavillon type:1360776

# IfcWallStandardCase: Mur de base:Mur exterieure en pierre - Ext. 500 MM (5)
In: Plan des fondations Maisons 1 et 2
Type - PredefinedType: STANDARD; Material: Mur par défaut 0.5 m
Type - Autre - Catégorie: Murs; Nom de la famille: Mur de base
Type - Construction - Fonction: Extérieur; Retournement aux extrémités: Aucun(e); Retournement aux insertions: Ne pas retourner; Largeur: 0.5 m
Type - Données d'identification - Nom du type: Mur exterieure en pierre - Ext. 500 MM
Type - Graphismes - Couleur vue détail faible: 0
Type - Matériaux et finitions - Matériau structurel: Mur par défaut
Type - Propriétés analytiques - Rugosité: 1; Coefficient d'absorbance: 0.1
Autre - Famille: Mur de base: Mur exterieure en pierre - Ext. 500 MM; Famille et type: Mur de base: Mur exterieure en pierre - Ext. 500 MM; ID du type: Mur de base: Mur exterieure en pierre - Ext. 500 MM; Type: Mur de base: Mur exterieure en pierre - Ext. 500 MM
Contraintes - Décalage supérieur: 0 m; Extension inférieure: 0 m; Extension supérieure: 0 m; Lié au volume: no; Ligne de justification: Nu fini: Extérieur; Limite de pièce: yes; Partie inférieure attachée: no; Partie supérieure attachée: no; Décalage inférieur: -0.2 m; Hauteur non contrainte: 2 m
Phase de construction - Phase de création: Nouvelle construction
Structure - Activer le modèle analytique: no; Structure: no; Utilisation structurelle: Non porteur
Pset_WallCommon - LoadBearing: no; ExtendToStructure: no; IsExternal: yes; Reference: Mur exterieure en pierre - Ext. 500 MM
Name (Mur de base:Mur exterieure en pierre - Ext. 500 MM:...) | Contrainte inférieure | Longueur (m) = Volume (m3) | Surface (m2)
1325408 | Niveau: RDC | 16.5087 | 33.0248
1325879 | Niveau: Plan des fondations Maisons 1 et 2 | 3.38 | 6.76751
1326033 | Niveau: Plan des fondations Maisons 1 et 2 | 9.64514 | 19.2915
1326181 | Niveau: Plan des fondations Maisons 1 et 2 | 22.4 | 44.8067
1328455 | Niveau: Plan des fondations Maisons 1 et 2 | 1.39443 | 2.79673

# IfcWallStandardCase: Mur de base:PAPIER PEINT Jardin Sarcelle (2)
In: ETAGE
Type - PredefinedType: STANDARD; Material: papier peint jardin sarcelle 0.002 m
Type - Autre - Catégorie: Murs; Nom de la famille: Mur de base
Type - Construction - Fonction: Extérieur; Retournement aux extrémités: Aucun(e); Retournement aux insertions: Les deux; Largeur: 0.002 m
Type - Données d'identification - Commentaires du type: Ext. Parpaing 20 + Isolant 10; Nom du type: PAPIER PEINT Jardin Sarcelle
Type - Graphismes - Couleur vue détail faible: 0
Type - Propriétés analytiques - Rugosité: 1; Coefficient d'absorbance: 0.1
Autre - Famille: Mur de base: PAPIER PEINT Jardin Sarcelle; Famille et type: Mur de base: PAPIER PEINT Jardin Sarcelle; ID du type: Mur de base: PAPIER PEINT Jardin Sarcelle; Type: Mur de base: PAPIER PEINT Jardin Sarcelle
Contraintes - Décalage supérieur: 0 m; Extension inférieure: 0 m; Extension supérieure: 0 m; Lié au volume: no; Ligne de justification: Nu fini: Extérieur; Limite de pièce: yes; Partie inférieure attachée: no; Partie supérieure attachée: no; Contrainte inférieure: Niveau: ETAGE; Décalage inférieur: 0.04 m
Phase de construction - Phase de création: Nouvelle construction
Structure - Activer le modèle analytique: no; Structure: no; Utilisation structurelle: Non porteur
Pset_WallCommon - LoadBearing: no; ExtendToStructure: no; IsExternal: yes; Reference: PAPIER PEINT Jardin Sarcelle
Name (Mur de base:PAPIER PEINT Jardin Sarcelle:...) | Hauteur non contrainte (m) | Longueur (m) | Surface (m2) | Volume (m3)
1375371 | 2.5 | 3.4655 | 8.66875 | 0.0173375
1382603 | 2.48 | 0.830078 | 1.25454 | 0.00250909

# IfcWallStandardCase: Mur de base:PLINTHE EN BOIS (3)
In: ETAGE
Type - PredefinedType: STANDARD; Material: Blanc - Element de salle de bains 0.002 m
Type - Autre - Catégorie: Murs; Nom de la famille: Mur de base
Type - Construction - Fonction: Extérieur; Retournement aux extrémités: Aucun(e); Retournement aux insertions: Les deux; Largeur: 0.002 m
Type - Données d'identification - Commentaires du type: Ext. Parpaing 20 + Isolant 10; Nom du type: PLINTHE EN BOIS
Type - Graphismes - Couleur vue détail faible: 0
Type - Propriétés analytiques - Rugosité: 1; Coefficient d'absorbance: 0.1
Autre - Famille: Mur de base: PLINTHE EN BOIS; Famille et type: Mur de base: PLINTHE EN BOIS; ID du type: Mur de base: PLINTHE EN BOIS; Type: Mur de base: PLINTHE EN BOIS
Contraintes - Décalage supérieur: 0 m; Extension inférieure: 0 m; Extension supérieure: 0 m; Lié au volume: no; Ligne de justification: Nu fini: Extérieur; Limite de pièce: yes; Partie inférieure attachée: no; Partie supérieure attachée: no; Contrainte inférieure: Niveau: ETAGE; Décalage inférieur: 0.04 m; Hauteur non contrainte: 0.1 m
Phase de construction - Phase de création: Nouvelle construction
Structure - Activer le modèle analytique: no; Structure: no; Utilisation structurelle: Non porteur
Pset_WallCommon - LoadBearing: no; ExtendToStructure: no; IsExternal: yes; Reference: PLINTHE EN BOIS
Name (Mur de base:PLINTHE EN BOIS:...) | Longueur (m) | Surface (m2) | Volume (m3)
1363075 | 5.555 | 0.535 | 0.00107
1377456 | 3.101 | 0.31 | 0.00062
1380331 | 2.5 | 0.2499 | 0.0004998

# IfcWallStandardCase: Mur de base:modénateurs ep 2 cm gris (8)
In: Plan des fondations Maisons 1 et 2
Type - PredefinedType: STANDARD; Material: Enduit blanc cassé 0.01 m, Parpaing 0.01 m, Enduit blanc cassé 0.01 m
Type - Autre - Catégorie: Murs; Nom de la famille: Mur de base
Type - Construction - Fonction: Extérieur; Retournement aux extrémités: Aucun(e); Retournement aux insertions: Les deux; Largeur: 0.03 m
Type - Données d'identification - Commentaires du type: Ext. Parpaing 20 + Isolant 10; Nom du type: modénateurs ep 2 cm gris
Type - Graphismes - Couleur vue détail faible: 0
Type - Matériaux et finitions - Matériau structurel: Parpaing
Type - Propriétés analytiques - Rugosité: 1; Coefficient d'absorbance: 0.1
Autre - Famille: Mur de base: modénateurs ep 2 cm gris; Famille et type: Mur de base: modénateurs ep 2 cm gris; ID du type: Mur de base: modénateurs ep 2 cm gris; Type: Mur de base: modénateurs ep 2 cm gris
Contraintes - Extension inférieure: 0 m; Extension supérieure: 0 m; Lié au volume: no; Ligne de justification: Nu fini: Extérieur; Limite de pièce: yes; Partie inférieure attachée: no; Partie supérieure attachée: no; Contrainte supérieure: Niveau: Etage; Décalage inférieur: 0.8 m; Décalage supérieur: -0.410875 m; Hauteur non contrainte: 1.48913 m
Cotes - Surface: 0.622988 m2; Volume: 0.0186896 m3
Phase de construction - Phase de création: Nouvelle construction
Structure - Activer le modèle analytique: no; Structure: no; Utilisation structurelle: Non porteur
Pset_WallCommon - LoadBearing: no; ExtendToStructure: no; IsExternal: yes; Reference: modénateurs ep 2 cm gris
Name (Mur de base:modénateurs ep 2 cm gris:...) | Contrainte inférieure | Longueur (m) | Group
1290335 | Niveau: RDC | 1.475
1291060 | Niveau: Plan des fondations Maisons 1 et 2 | 1.75778
1292383 | Niveau: Plan des fondations Maisons 1 et 2 | 1.475 | Groupe de modèles:Pavillon type:1258082
1292442 | Niveau: Plan des fondations Maisons 1 et 2 | 1.75778 | Groupe de modèles:Pavillon type:1258082
1292484 | Niveau: Plan des fondations Maisons 1 et 2 | 1.475 | Groupe de modèles:Pavillon type:1258309
1292543 | Niveau: Plan des fondations Maisons 1 et 2 | 1.75778 | Groupe de modèles:Pavillon type:1258309
1360841 | Niveau: Plan des fondations Maisons 1 et 2 | 1.475 | Groupe de modèles:Pavillon type:1360776
1360880 | Niveau: Plan des fondations Maisons 1 et 2 | 1.75778 | Groupe de modèles:Pavillon type:1360776

# IfcWallStandardCase: Mur de base:peinture biorox 1, Mur de base:peinture biorox 1:1369642
In: ETAGE
Type - PredefinedType: STANDARD; Material: biorox 1 0.002 m
Type - Autre - Catégorie: Murs; Nom de la famille: Mur de base
Type - Construction - Fonction: Extérieur; Retournement aux extrémités: Aucun(e); Retournement aux insertions: Les deux; Largeur: 0.002 m
Type - Données d'identification - Commentaires du type: Ext. Parpaing 20 + Isolant 10; Nom du type: peinture biorox 1
Type - Graphismes - Couleur vue détail faible: 0
Type - Propriétés analytiques - Rugosité: 1; Coefficient d'absorbance: 0.1
Autre - Famille: Mur de base: peinture biorox 1; Famille et type: Mur de base: peinture biorox 1; ID du type: Mur de base: peinture biorox 1; Type: Mur de base: peinture biorox 1
Contraintes - Décalage supérieur: 0 m; Extension inférieure: 0 m; Extension supérieure: 0 m; Lié au volume: no; Ligne de justification: Nu fini: Extérieur; Limite de pièce: yes; Partie inférieure attachée: no; Partie supérieure attachée: no; Contrainte inférieure: Niveau: ETAGE; Décalage inférieur: 0.04 m; Hauteur non contrainte: 2.5 m
Cotes - Longueur: 1.17407 m; Surface: 0.504413 m2; Volume: 0.00100883 m3
Phase de construction - Phase de création: Nouvelle construction
Structure - Activer le modèle analytique: no; Structure: no; Utilisation structurelle: Non porteur
Pset_WallCommon - LoadBearing: no; ExtendToStructure: no; IsExternal: yes; Reference: peinture biorox 1

# IfcWallStandardCase: Mur de base:peinture biorox 2 (4)
In: ETAGE
Type - PredefinedType: STANDARD; Material: biorox 2 0.002 m
Type - Autre - Catégorie: Murs; Nom de la famille: Mur de base
Type - Construction - Fonction: Extérieur; Retournement aux extrémités: Aucun(e); Retournement aux insertions: Les deux; Largeur: 0.002 m
Type - Données d'identification - Commentaires du type: Ext. Parpaing 20 + Isolant 10; Nom du type: peinture biorox 2
Type - Graphismes - Couleur vue détail faible: 0
Type - Propriétés analytiques - Rugosité: 1; Coefficient d'absorbance: 0.1
Autre - Famille: Mur de base: peinture biorox 2; Famille et type: Mur de base: peinture biorox 2; ID du type: Mur de base: peinture biorox 2; Type: Mur de base: peinture biorox 2
Contraintes - Décalage supérieur: 0 m; Extension inférieure: 0 m; Extension supérieure: 0 m; Lié au volume: no; Ligne de justification: Nu fini: Extérieur; Limite de pièce: yes; Partie inférieure attachée: no; Partie supérieure attachée: no; Contrainte inférieure: Niveau: ETAGE
Phase de construction - Phase de création: Nouvelle construction
Structure - Activer le modèle analytique: no; Structure: no; Utilisation structurelle: Non porteur
Pset_WallCommon - LoadBearing: no; ExtendToStructure: no; IsExternal: yes; Reference: peinture biorox 2
Name (Mur de base:peinture biorox 2:...) | Décalage inférieur (m) | Hauteur non contrainte (m) | Longueur (m) | Surface (m2) | Volume (m3)
1362745 | 0.139763 | 2.38024 | 2.4292 | 0.239212 | 0.000478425
1364161 | 0.139763 | 2.38024 | 2.4292 | 0.239212 | 0.000478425
1369626 | 0.04 | 2.5 | 1.17407 | 0.504413 | 0.00100883
1371408 | 0.04 | 2.5 | 1.49716 | 2.1 | 0.0042

# IfcWindow: 120 x 135 cm (24)
Type - ParameterTakesPrecedence: no; Sizeable: no; Material: PVC - Blanc, Aluminium - Satiné, Béton - Ordinaire, Verre - Opaque Blanc
Type - Autre - Catégorie: Fenêtres; Nom de la famille: VR-2 Vantaux
Type - Construction - Fermeture du mur: Extérieur
Type - Cotes - Epaisseur d'isolation: 0.1 m; Hauteur: 1.35 m; Hauteur de la poignée: 1.35 m; Hauteur du caisson: 0.18 m; Largeur: 1.2 m; Largeur du cadre: 0.05 m; Largeur du meneau: 0.04 m; Saillie du caisson: 0.08 m
Type - Données d'identification - Marque de type: 145; Nom du type: 120 x 135 cm; Numéro OmniClass: 23.30.20.00; Titre OmniClass: Windows
Type - Matériaux et finitions - Appui: Béton - Ordinaire; Cadre: PVC - Blanc; Poignée: PVC - Blanc; Vitrage: Verre - Opaque Blanc; Volet: PVC - Blanc
Type - Propriétés analytiques - Construction analytique: <Aucun>
OverallHeight: 1.65 m; OverallWidth: 1.3 m
Pset_WindowCommon - IsExternal: yes; Reference: 120 x 135 cm
Autre - Famille: VR-2 Vantaux: 120 x 135 cm; Famille et type: VR-2 Vantaux: 120 x 135 cm; Hauteur sous linteau: 2.15 m; ID du type: VR-2 Vantaux: 120 x 135 cm; Type: VR-2 Vantaux: 120 x 135 cm
Contraintes - Hauteur de l'appui: 0.8 m
Cotes - Fermeture du volet: 0.25 m; Surface: 3.97573 m2; Volume: 0.134252 m3
Phase de construction - Phase de création: Nouvelle construction
Name (VR-2 Vantaux:120 x 135 cm:...) | In | ID hôte | Niveau | Identifiant | Group
1257908 | Plan des fondations Maisons 1 et 2 | Mur de base: Ext. Parpaing 20 + Isolant 10 enduit blanc cassé | Niveau: Plan des fondations Maisons 1 et 2 | 496 | Groupe de modèles:Pavillon type:1258082
1257991 | Plan des fondations Maisons 1 et 2 | Mur de base: Ext. Parpaing 20 + Isolant 10 enduit blanc cassé | Niveau: Plan des fondations Maisons 1 et 2 | 497 | Groupe de modèles:Pavillon type:1258082
1258053 | ETAGE | Mur de base: Ext. Parpaing 20 + Isolant 10 enduit blanc cassé | Niveau: ETAGE | 499 | Groupe de modèles:Pavillon type:1258082
1258054 | ETAGE | Mur de base: Ext. Parpaing 20 + Isolant 10 enduit blanc cassé | Niveau: ETAGE | 500 | Groupe de modèles:Pavillon type:1258082
1258055 | ETAGE | Mur de base: Ext. Parpaing 20 + Isolant 10 enduit blanc cassé | Niveau: ETAGE | 501 | Groupe de modèles:Pavillon type:1258082
1258056 | ETAGE | Mur de base: Ext. Parpaing 20 + Isolant 10 enduit gris | Niveau: ETAGE | 502 | Groupe de modèles:Pavillon type:1258082
1258142 | Plan des fondations Maisons 1 et 2 | Mur de base: Ext. Parpaing 20 + Isolant 10 enduit blanc cassé | Niveau: Plan des fondations Maisons 1 et 2 | 503 | Groupe de modèles:Pavillon type:1258309
1258224 | Plan des fondations Maisons 1 et 2 | Mur de base: Ext. Parpaing 20 + Isolant 10 enduit blanc cassé | Niveau: Plan des fondations Maisons 1 et 2 | 504 | Groupe de modèles:Pavillon type:1258309
1258280 | ETAGE | Mur de base: Ext. Parpaing 20 + Isolant 10 enduit blanc cassé | Niveau: ETAGE | 506 | Groupe de modèles:Pavillon type:1258309
1258281 | ETAGE | Mur de base: Ext. Parpaing 20 + Isolant 10 enduit blanc cassé | Niveau: ETAGE | 507 | Groupe de modèles:Pavillon type:1258309
1258282 | ETAGE | Mur de base: Ext. Parpaing 20 + Isolant 10 enduit blanc cassé | Niveau: ETAGE | 508 | Groupe de modèles:Pavillon type:1258309
1258283 | ETAGE | Mur de base: Ext. Parpaing 20 + Isolant 10 enduit gris | Niveau: ETAGE | 509 | Groupe de modèles:Pavillon type:1258309
1283008 | Plan des fondations Maisons 1 et 2 | Mur de base: Ext. Parpaing 20 + Isolant 10 enduit blanc cassé | Niveau: Plan des fondations Maisons 1 et 2 | 510
1283089 | Plan des fondations Maisons 1 et 2 | Mur de base: Ext. Parpaing 20 + Isolant 10 enduit blanc cassé | Niveau: Plan des fondations Maisons 1 et 2 | 511
1283134 | ETAGE | Mur de base: Ext. Parpaing 20 + Isolant 10 enduit blanc cassé | Niveau: ETAGE | 513
1283135 | ETAGE | Mur de base: Ext. Parpaing 20 + Isolant 10 enduit blanc cassé | Niveau: ETAGE | 514
1283136 | ETAGE | Mur de base: Ext. Parpaing 20 + Isolant 10 enduit blanc cassé | Niveau: ETAGE | 515
1283137 | ETAGE | Mur de base: Ext. Parpaing 20 + Isolant 10 enduit gris | Niveau: ETAGE | 516
1360639 | Plan des fondations Maisons 1 et 2 | Mur de base: Ext. Parpaing 20 + Isolant 10 enduit blanc cassé | Niveau: Plan des fondations Maisons 1 et 2 | 517 | Groupe de modèles:Pavillon type:1360776
1360713 | Plan des fondations Maisons 1 et 2 | Mur de base: Ext. Parpaing 20 + Isolant 10 enduit blanc cassé | Niveau: Plan des fondations Maisons 1 et 2 | 518 | Groupe de modèles:Pavillon type:1360776
1360753 | ETAGE | Mur de base: Ext. Parpaing 20 + Isolant 10 enduit blanc cassé | Niveau: ETAGE | 520 | Groupe de modèles:Pavillon type:1360776
1360754 | ETAGE | Mur de base: Ext. Parpaing 20 + Isolant 10 enduit blanc cassé | Niveau: ETAGE | 521 | Groupe de modèles:Pavillon type:1360776
1360755 | ETAGE | Mur de base: Ext. Parpaing 20 + Isolant 10 enduit blanc cassé | Niveau: ETAGE | 522 | Groupe de modèles:Pavillon type:1360776
1360756 | ETAGE | Mur de base: Ext. Parpaing 20 + Isolant 10 enduit gris | Niveau: ETAGE | 523 | Groupe de modèles:Pavillon type:1360776

# IfcWindow: 240 x 215 cm (4)
In: Plan des fondations Maisons 1 et 2
Type - ParameterTakesPrecedence: no; Sizeable: no; Material: PVC - Blanc, Aluminium - Satiné, Béton - Ordinaire, Verre - Opaque Blanc
Type - Autre - Catégorie: Fenêtres; Nom de la famille: PF-VR-2 Vantaux
Type - Construction - Fermeture du mur: Extérieur
Type - Cotes - Epaisseur d'isolation: 0.1 m; Hauteur: 2.15 m; Hauteur de la poignée: 1 m; Hauteur du caisson: 0.18 m; Largeur: 2.4 m; Largeur du cadre: 0.05 m; Largeur du meneau: 0.04 m; Saillie du caisson: 0.08 m
Type - Données d'identification - Marque de type: 148; Nom du type: 240 x 215 cm; Numéro OmniClass: 23.30.20.00; Titre OmniClass: Windows
Type - Matériaux et finitions - Appui: Béton - Ordinaire; Cadre: PVC - Blanc; Poignée: PVC - Blanc; Vitrage: Verre - Opaque Blanc; Volet: PVC - Blanc
Type - Propriétés analytiques - Construction analytique: <Aucun>
OverallHeight: 2.40456 m; OverallWidth: 2.5 m
Pset_WindowCommon - IsExternal: yes; Reference: 240 x 215 cm
Autre - ID hôte: Mur de base: Ext. Parpaing 20 + Isolant 10 enduit blanc cassé; Famille: PF-VR-2 Vantaux: 240 x 215 cm; Famille et type: PF-VR-2 Vantaux: 240 x 215 cm; Hauteur sous linteau: 2.19 m; ID du type: PF-VR-2 Vantaux: 240 x 215 cm; Type: PF-VR-2 Vantaux: 240 x 215 cm
Contraintes - Niveau: Niveau: Plan des fondations Maisons 1 et 2; Hauteur de l'appui: 0.04 m
Cotes - Fermeture du volet: 0.25 m; Surface: 9.2112 m2; Volume: 0.262873 m3
Phase de construction - Phase de création: Nouvelle construction
Name (PF-VR-2 Vantaux:240 x 215 cm:...) | Identifiant | Group
1257992 | 498 | Groupe de modèles:Pavillon type:1258082
1258225 | 505 | Groupe de modèles:Pavillon type:1258309
1283090 | 512
1360714 | 519 | Groupe de modèles:Pavillon type:1360776
